VERSION 5.8 ;
BUSBITCHARS "[]" ;
DIVIDERCHAR "/" ;
UNITS
    DATABASE MICRONS 1000 ;
END UNITS

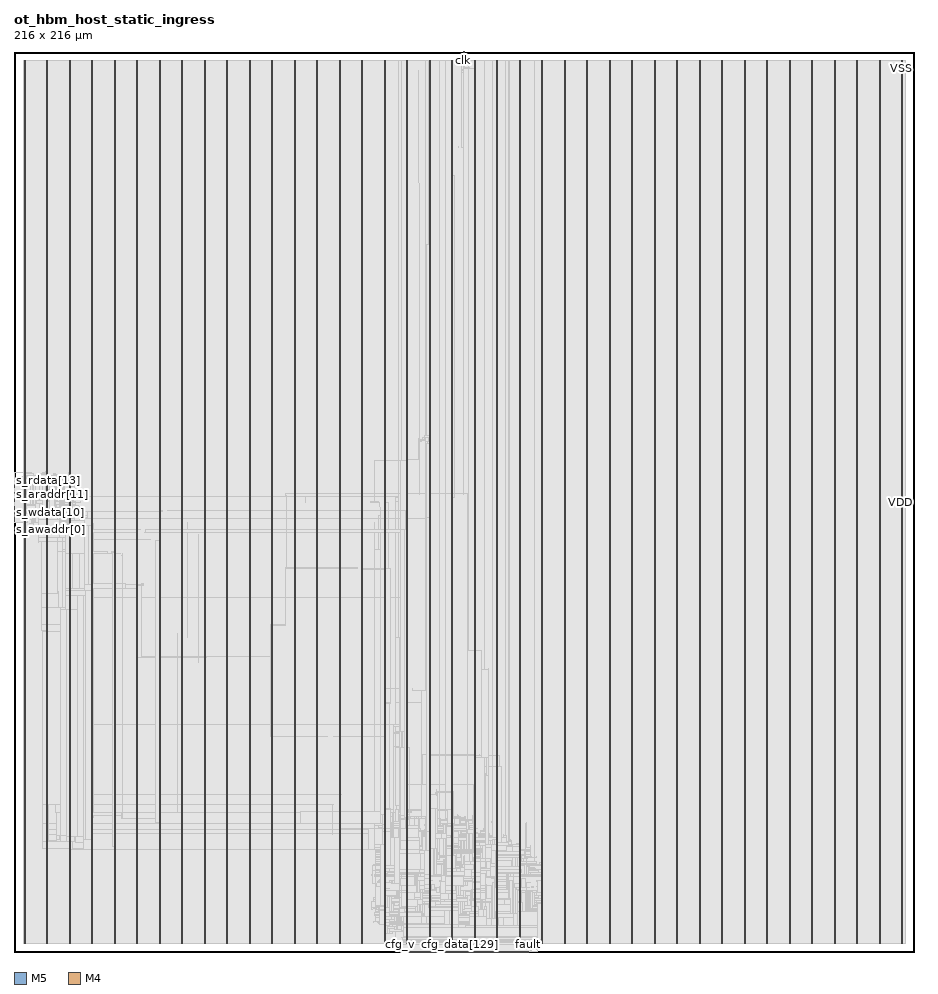
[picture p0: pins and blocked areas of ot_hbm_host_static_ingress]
MACRO ot_hbm_host_static_ingress
  FOREIGN ot_hbm_host_static_ingress 0 0 ;
  CLASS BLOCK ;
  SIZE 216 BY 216 ;
  PIN block_ready
    DIRECTION INPUT ;
    USE SIGNAL ;
    PORT
      LAYER M5 ;
        RECT  108 215.916 108.024 216 ;
    END
  END block_ready
  PIN cfg_addr[0]
    DIRECTION OUTPUT ;
    USE SIGNAL ;
    PORT
      LAYER M5 ;
        RECT  93.504 0 93.528 0.084 ;
    END
  END cfg_addr[0]
  PIN cfg_addr[10]
    DIRECTION OUTPUT ;
    USE SIGNAL ;
    PORT
      LAYER M5 ;
        RECT  94.464 0 94.488 0.084 ;
    END
  END cfg_addr[10]
  PIN cfg_addr[11]
    DIRECTION OUTPUT ;
    USE SIGNAL ;
    PORT
      LAYER M5 ;
        RECT  94.56 0 94.584 0.084 ;
    END
  END cfg_addr[11]
  PIN cfg_addr[1]
    DIRECTION OUTPUT ;
    USE SIGNAL ;
    PORT
      LAYER M5 ;
        RECT  93.6 0 93.624 0.084 ;
    END
  END cfg_addr[1]
  PIN cfg_addr[2]
    DIRECTION OUTPUT ;
    USE SIGNAL ;
    PORT
      LAYER M5 ;
        RECT  93.696 0 93.72 0.084 ;
    END
  END cfg_addr[2]
  PIN cfg_addr[3]
    DIRECTION OUTPUT ;
    USE SIGNAL ;
    PORT
      LAYER M5 ;
        RECT  93.792 0 93.816 0.084 ;
    END
  END cfg_addr[3]
  PIN cfg_addr[4]
    DIRECTION OUTPUT ;
    USE SIGNAL ;
    PORT
      LAYER M5 ;
        RECT  93.888 0 93.912 0.084 ;
    END
  END cfg_addr[4]
  PIN cfg_addr[5]
    DIRECTION OUTPUT ;
    USE SIGNAL ;
    PORT
      LAYER M5 ;
        RECT  93.984 0 94.008 0.084 ;
    END
  END cfg_addr[5]
  PIN cfg_addr[6]
    DIRECTION OUTPUT ;
    USE SIGNAL ;
    PORT
      LAYER M5 ;
        RECT  94.08 0 94.104 0.084 ;
    END
  END cfg_addr[6]
  PIN cfg_addr[7]
    DIRECTION OUTPUT ;
    USE SIGNAL ;
    PORT
      LAYER M5 ;
        RECT  94.176 0 94.2 0.084 ;
    END
  END cfg_addr[7]
  PIN cfg_addr[8]
    DIRECTION OUTPUT ;
    USE SIGNAL ;
    PORT
      LAYER M5 ;
        RECT  94.272 0 94.296 0.084 ;
    END
  END cfg_addr[8]
  PIN cfg_addr[9]
    DIRECTION OUTPUT ;
    USE SIGNAL ;
    PORT
      LAYER M5 ;
        RECT  94.368 0 94.392 0.084 ;
    END
  END cfg_addr[9]
  PIN cfg_data[0]
    DIRECTION OUTPUT ;
    USE SIGNAL ;
    PORT
      LAYER M5 ;
        RECT  94.656 0 94.68 0.084 ;
    END
  END cfg_data[0]
  PIN cfg_data[100]
    DIRECTION OUTPUT ;
    USE SIGNAL ;
    PORT
      LAYER M5 ;
        RECT  104.256 0 104.28 0.084 ;
    END
  END cfg_data[100]
  PIN cfg_data[101]
    DIRECTION OUTPUT ;
    USE SIGNAL ;
    PORT
      LAYER M5 ;
        RECT  104.352 0 104.376 0.084 ;
    END
  END cfg_data[101]
  PIN cfg_data[102]
    DIRECTION OUTPUT ;
    USE SIGNAL ;
    PORT
      LAYER M5 ;
        RECT  104.448 0 104.472 0.084 ;
    END
  END cfg_data[102]
  PIN cfg_data[103]
    DIRECTION OUTPUT ;
    USE SIGNAL ;
    PORT
      LAYER M5 ;
        RECT  104.544 0 104.568 0.084 ;
    END
  END cfg_data[103]
  PIN cfg_data[104]
    DIRECTION OUTPUT ;
    USE SIGNAL ;
    PORT
      LAYER M5 ;
        RECT  104.64 0 104.664 0.084 ;
    END
  END cfg_data[104]
  PIN cfg_data[105]
    DIRECTION OUTPUT ;
    USE SIGNAL ;
    PORT
      LAYER M5 ;
        RECT  104.736 0 104.76 0.084 ;
    END
  END cfg_data[105]
  PIN cfg_data[106]
    DIRECTION OUTPUT ;
    USE SIGNAL ;
    PORT
      LAYER M5 ;
        RECT  104.832 0 104.856 0.084 ;
    END
  END cfg_data[106]
  PIN cfg_data[107]
    DIRECTION OUTPUT ;
    USE SIGNAL ;
    PORT
      LAYER M5 ;
        RECT  104.928 0 104.952 0.084 ;
    END
  END cfg_data[107]
  PIN cfg_data[108]
    DIRECTION OUTPUT ;
    USE SIGNAL ;
    PORT
      LAYER M5 ;
        RECT  105.024 0 105.048 0.084 ;
    END
  END cfg_data[108]
  PIN cfg_data[109]
    DIRECTION OUTPUT ;
    USE SIGNAL ;
    PORT
      LAYER M5 ;
        RECT  105.12 0 105.144 0.084 ;
    END
  END cfg_data[109]
  PIN cfg_data[10]
    DIRECTION OUTPUT ;
    USE SIGNAL ;
    PORT
      LAYER M5 ;
        RECT  95.616 0 95.64 0.084 ;
    END
  END cfg_data[10]
  PIN cfg_data[110]
    DIRECTION OUTPUT ;
    USE SIGNAL ;
    PORT
      LAYER M5 ;
        RECT  105.216 0 105.24 0.084 ;
    END
  END cfg_data[110]
  PIN cfg_data[111]
    DIRECTION OUTPUT ;
    USE SIGNAL ;
    PORT
      LAYER M5 ;
        RECT  105.312 0 105.336 0.084 ;
    END
  END cfg_data[111]
  PIN cfg_data[112]
    DIRECTION OUTPUT ;
    USE SIGNAL ;
    PORT
      LAYER M5 ;
        RECT  105.408 0 105.432 0.084 ;
    END
  END cfg_data[112]
  PIN cfg_data[113]
    DIRECTION OUTPUT ;
    USE SIGNAL ;
    PORT
      LAYER M5 ;
        RECT  105.504 0 105.528 0.084 ;
    END
  END cfg_data[113]
  PIN cfg_data[114]
    DIRECTION OUTPUT ;
    USE SIGNAL ;
    PORT
      LAYER M5 ;
        RECT  105.6 0 105.624 0.084 ;
    END
  END cfg_data[114]
  PIN cfg_data[115]
    DIRECTION OUTPUT ;
    USE SIGNAL ;
    PORT
      LAYER M5 ;
        RECT  105.696 0 105.72 0.084 ;
    END
  END cfg_data[115]
  PIN cfg_data[116]
    DIRECTION OUTPUT ;
    USE SIGNAL ;
    PORT
      LAYER M5 ;
        RECT  105.792 0 105.816 0.084 ;
    END
  END cfg_data[116]
  PIN cfg_data[117]
    DIRECTION OUTPUT ;
    USE SIGNAL ;
    PORT
      LAYER M5 ;
        RECT  105.888 0 105.912 0.084 ;
    END
  END cfg_data[117]
  PIN cfg_data[118]
    DIRECTION OUTPUT ;
    USE SIGNAL ;
    PORT
      LAYER M5 ;
        RECT  105.984 0 106.008 0.084 ;
    END
  END cfg_data[118]
  PIN cfg_data[119]
    DIRECTION OUTPUT ;
    USE SIGNAL ;
    PORT
      LAYER M5 ;
        RECT  106.08 0 106.104 0.084 ;
    END
  END cfg_data[119]
  PIN cfg_data[11]
    DIRECTION OUTPUT ;
    USE SIGNAL ;
    PORT
      LAYER M5 ;
        RECT  95.712 0 95.736 0.084 ;
    END
  END cfg_data[11]
  PIN cfg_data[120]
    DIRECTION OUTPUT ;
    USE SIGNAL ;
    PORT
      LAYER M5 ;
        RECT  106.176 0 106.2 0.084 ;
    END
  END cfg_data[120]
  PIN cfg_data[121]
    DIRECTION OUTPUT ;
    USE SIGNAL ;
    PORT
      LAYER M5 ;
        RECT  106.272 0 106.296 0.084 ;
    END
  END cfg_data[121]
  PIN cfg_data[122]
    DIRECTION OUTPUT ;
    USE SIGNAL ;
    PORT
      LAYER M5 ;
        RECT  106.368 0 106.392 0.084 ;
    END
  END cfg_data[122]
  PIN cfg_data[123]
    DIRECTION OUTPUT ;
    USE SIGNAL ;
    PORT
      LAYER M5 ;
        RECT  106.464 0 106.488 0.084 ;
    END
  END cfg_data[123]
  PIN cfg_data[124]
    DIRECTION OUTPUT ;
    USE SIGNAL ;
    PORT
      LAYER M5 ;
        RECT  106.56 0 106.584 0.084 ;
    END
  END cfg_data[124]
  PIN cfg_data[125]
    DIRECTION OUTPUT ;
    USE SIGNAL ;
    PORT
      LAYER M5 ;
        RECT  106.656 0 106.68 0.084 ;
    END
  END cfg_data[125]
  PIN cfg_data[126]
    DIRECTION OUTPUT ;
    USE SIGNAL ;
    PORT
      LAYER M5 ;
        RECT  106.752 0 106.776 0.084 ;
    END
  END cfg_data[126]
  PIN cfg_data[127]
    DIRECTION OUTPUT ;
    USE SIGNAL ;
    PORT
      LAYER M5 ;
        RECT  106.848 0 106.872 0.084 ;
    END
  END cfg_data[127]
  PIN cfg_data[128]
    DIRECTION OUTPUT ;
    USE SIGNAL ;
    PORT
      LAYER M5 ;
        RECT  106.944 0 106.968 0.084 ;
    END
  END cfg_data[128]
  PIN cfg_data[129]
    DIRECTION OUTPUT ;
    USE SIGNAL ;
    PORT
      LAYER M5 ;
        RECT  107.04 0 107.064 0.084 ;
    END
  END cfg_data[129]
  PIN cfg_data[12]
    DIRECTION OUTPUT ;
    USE SIGNAL ;
    PORT
      LAYER M5 ;
        RECT  95.808 0 95.832 0.084 ;
    END
  END cfg_data[12]
  PIN cfg_data[130]
    DIRECTION OUTPUT ;
    USE SIGNAL ;
    PORT
      LAYER M5 ;
        RECT  107.136 0 107.16 0.084 ;
    END
  END cfg_data[130]
  PIN cfg_data[131]
    DIRECTION OUTPUT ;
    USE SIGNAL ;
    PORT
      LAYER M5 ;
        RECT  107.232 0 107.256 0.084 ;
    END
  END cfg_data[131]
  PIN cfg_data[132]
    DIRECTION OUTPUT ;
    USE SIGNAL ;
    PORT
      LAYER M5 ;
        RECT  107.328 0 107.352 0.084 ;
    END
  END cfg_data[132]
  PIN cfg_data[133]
    DIRECTION OUTPUT ;
    USE SIGNAL ;
    PORT
      LAYER M5 ;
        RECT  107.424 0 107.448 0.084 ;
    END
  END cfg_data[133]
  PIN cfg_data[134]
    DIRECTION OUTPUT ;
    USE SIGNAL ;
    PORT
      LAYER M5 ;
        RECT  107.52 0 107.544 0.084 ;
    END
  END cfg_data[134]
  PIN cfg_data[135]
    DIRECTION OUTPUT ;
    USE SIGNAL ;
    PORT
      LAYER M5 ;
        RECT  107.616 0 107.64 0.084 ;
    END
  END cfg_data[135]
  PIN cfg_data[136]
    DIRECTION OUTPUT ;
    USE SIGNAL ;
    PORT
      LAYER M5 ;
        RECT  107.712 0 107.736 0.084 ;
    END
  END cfg_data[136]
  PIN cfg_data[137]
    DIRECTION OUTPUT ;
    USE SIGNAL ;
    PORT
      LAYER M5 ;
        RECT  107.808 0 107.832 0.084 ;
    END
  END cfg_data[137]
  PIN cfg_data[138]
    DIRECTION OUTPUT ;
    USE SIGNAL ;
    PORT
      LAYER M5 ;
        RECT  107.904 0 107.928 0.084 ;
    END
  END cfg_data[138]
  PIN cfg_data[139]
    DIRECTION OUTPUT ;
    USE SIGNAL ;
    PORT
      LAYER M5 ;
        RECT  108 0 108.024 0.084 ;
    END
  END cfg_data[139]
  PIN cfg_data[13]
    DIRECTION OUTPUT ;
    USE SIGNAL ;
    PORT
      LAYER M5 ;
        RECT  95.904 0 95.928 0.084 ;
    END
  END cfg_data[13]
  PIN cfg_data[140]
    DIRECTION OUTPUT ;
    USE SIGNAL ;
    PORT
      LAYER M5 ;
        RECT  108.096 0 108.12 0.084 ;
    END
  END cfg_data[140]
  PIN cfg_data[141]
    DIRECTION OUTPUT ;
    USE SIGNAL ;
    PORT
      LAYER M5 ;
        RECT  108.192 0 108.216 0.084 ;
    END
  END cfg_data[141]
  PIN cfg_data[142]
    DIRECTION OUTPUT ;
    USE SIGNAL ;
    PORT
      LAYER M5 ;
        RECT  108.288 0 108.312 0.084 ;
    END
  END cfg_data[142]
  PIN cfg_data[143]
    DIRECTION OUTPUT ;
    USE SIGNAL ;
    PORT
      LAYER M5 ;
        RECT  108.384 0 108.408 0.084 ;
    END
  END cfg_data[143]
  PIN cfg_data[144]
    DIRECTION OUTPUT ;
    USE SIGNAL ;
    PORT
      LAYER M5 ;
        RECT  108.48 0 108.504 0.084 ;
    END
  END cfg_data[144]
  PIN cfg_data[145]
    DIRECTION OUTPUT ;
    USE SIGNAL ;
    PORT
      LAYER M5 ;
        RECT  108.576 0 108.6 0.084 ;
    END
  END cfg_data[145]
  PIN cfg_data[146]
    DIRECTION OUTPUT ;
    USE SIGNAL ;
    PORT
      LAYER M5 ;
        RECT  108.672 0 108.696 0.084 ;
    END
  END cfg_data[146]
  PIN cfg_data[147]
    DIRECTION OUTPUT ;
    USE SIGNAL ;
    PORT
      LAYER M5 ;
        RECT  108.768 0 108.792 0.084 ;
    END
  END cfg_data[147]
  PIN cfg_data[148]
    DIRECTION OUTPUT ;
    USE SIGNAL ;
    PORT
      LAYER M5 ;
        RECT  108.864 0 108.888 0.084 ;
    END
  END cfg_data[148]
  PIN cfg_data[149]
    DIRECTION OUTPUT ;
    USE SIGNAL ;
    PORT
      LAYER M5 ;
        RECT  108.96 0 108.984 0.084 ;
    END
  END cfg_data[149]
  PIN cfg_data[14]
    DIRECTION OUTPUT ;
    USE SIGNAL ;
    PORT
      LAYER M5 ;
        RECT  96 0 96.024 0.084 ;
    END
  END cfg_data[14]
  PIN cfg_data[150]
    DIRECTION OUTPUT ;
    USE SIGNAL ;
    PORT
      LAYER M5 ;
        RECT  109.056 0 109.08 0.084 ;
    END
  END cfg_data[150]
  PIN cfg_data[151]
    DIRECTION OUTPUT ;
    USE SIGNAL ;
    PORT
      LAYER M5 ;
        RECT  109.152 0 109.176 0.084 ;
    END
  END cfg_data[151]
  PIN cfg_data[152]
    DIRECTION OUTPUT ;
    USE SIGNAL ;
    PORT
      LAYER M5 ;
        RECT  109.248 0 109.272 0.084 ;
    END
  END cfg_data[152]
  PIN cfg_data[153]
    DIRECTION OUTPUT ;
    USE SIGNAL ;
    PORT
      LAYER M5 ;
        RECT  109.344 0 109.368 0.084 ;
    END
  END cfg_data[153]
  PIN cfg_data[154]
    DIRECTION OUTPUT ;
    USE SIGNAL ;
    PORT
      LAYER M5 ;
        RECT  109.44 0 109.464 0.084 ;
    END
  END cfg_data[154]
  PIN cfg_data[155]
    DIRECTION OUTPUT ;
    USE SIGNAL ;
    PORT
      LAYER M5 ;
        RECT  109.536 0 109.56 0.084 ;
    END
  END cfg_data[155]
  PIN cfg_data[156]
    DIRECTION OUTPUT ;
    USE SIGNAL ;
    PORT
      LAYER M5 ;
        RECT  109.632 0 109.656 0.084 ;
    END
  END cfg_data[156]
  PIN cfg_data[157]
    DIRECTION OUTPUT ;
    USE SIGNAL ;
    PORT
      LAYER M5 ;
        RECT  109.728 0 109.752 0.084 ;
    END
  END cfg_data[157]
  PIN cfg_data[158]
    DIRECTION OUTPUT ;
    USE SIGNAL ;
    PORT
      LAYER M5 ;
        RECT  109.824 0 109.848 0.084 ;
    END
  END cfg_data[158]
  PIN cfg_data[159]
    DIRECTION OUTPUT ;
    USE SIGNAL ;
    PORT
      LAYER M5 ;
        RECT  109.92 0 109.944 0.084 ;
    END
  END cfg_data[159]
  PIN cfg_data[15]
    DIRECTION OUTPUT ;
    USE SIGNAL ;
    PORT
      LAYER M5 ;
        RECT  96.096 0 96.12 0.084 ;
    END
  END cfg_data[15]
  PIN cfg_data[160]
    DIRECTION OUTPUT ;
    USE SIGNAL ;
    PORT
      LAYER M5 ;
        RECT  110.016 0 110.04 0.084 ;
    END
  END cfg_data[160]
  PIN cfg_data[161]
    DIRECTION OUTPUT ;
    USE SIGNAL ;
    PORT
      LAYER M5 ;
        RECT  110.112 0 110.136 0.084 ;
    END
  END cfg_data[161]
  PIN cfg_data[162]
    DIRECTION OUTPUT ;
    USE SIGNAL ;
    PORT
      LAYER M5 ;
        RECT  110.208 0 110.232 0.084 ;
    END
  END cfg_data[162]
  PIN cfg_data[163]
    DIRECTION OUTPUT ;
    USE SIGNAL ;
    PORT
      LAYER M5 ;
        RECT  110.304 0 110.328 0.084 ;
    END
  END cfg_data[163]
  PIN cfg_data[164]
    DIRECTION OUTPUT ;
    USE SIGNAL ;
    PORT
      LAYER M5 ;
        RECT  110.4 0 110.424 0.084 ;
    END
  END cfg_data[164]
  PIN cfg_data[165]
    DIRECTION OUTPUT ;
    USE SIGNAL ;
    PORT
      LAYER M5 ;
        RECT  110.496 0 110.52 0.084 ;
    END
  END cfg_data[165]
  PIN cfg_data[166]
    DIRECTION OUTPUT ;
    USE SIGNAL ;
    PORT
      LAYER M5 ;
        RECT  110.592 0 110.616 0.084 ;
    END
  END cfg_data[166]
  PIN cfg_data[167]
    DIRECTION OUTPUT ;
    USE SIGNAL ;
    PORT
      LAYER M5 ;
        RECT  110.688 0 110.712 0.084 ;
    END
  END cfg_data[167]
  PIN cfg_data[168]
    DIRECTION OUTPUT ;
    USE SIGNAL ;
    PORT
      LAYER M5 ;
        RECT  110.784 0 110.808 0.084 ;
    END
  END cfg_data[168]
  PIN cfg_data[169]
    DIRECTION OUTPUT ;
    USE SIGNAL ;
    PORT
      LAYER M5 ;
        RECT  110.88 0 110.904 0.084 ;
    END
  END cfg_data[169]
  PIN cfg_data[16]
    DIRECTION OUTPUT ;
    USE SIGNAL ;
    PORT
      LAYER M5 ;
        RECT  96.192 0 96.216 0.084 ;
    END
  END cfg_data[16]
  PIN cfg_data[170]
    DIRECTION OUTPUT ;
    USE SIGNAL ;
    PORT
      LAYER M5 ;
        RECT  110.976 0 111 0.084 ;
    END
  END cfg_data[170]
  PIN cfg_data[171]
    DIRECTION OUTPUT ;
    USE SIGNAL ;
    PORT
      LAYER M5 ;
        RECT  111.072 0 111.096 0.084 ;
    END
  END cfg_data[171]
  PIN cfg_data[172]
    DIRECTION OUTPUT ;
    USE SIGNAL ;
    PORT
      LAYER M5 ;
        RECT  111.168 0 111.192 0.084 ;
    END
  END cfg_data[172]
  PIN cfg_data[173]
    DIRECTION OUTPUT ;
    USE SIGNAL ;
    PORT
      LAYER M5 ;
        RECT  111.264 0 111.288 0.084 ;
    END
  END cfg_data[173]
  PIN cfg_data[174]
    DIRECTION OUTPUT ;
    USE SIGNAL ;
    PORT
      LAYER M5 ;
        RECT  111.36 0 111.384 0.084 ;
    END
  END cfg_data[174]
  PIN cfg_data[175]
    DIRECTION OUTPUT ;
    USE SIGNAL ;
    PORT
      LAYER M5 ;
        RECT  111.456 0 111.48 0.084 ;
    END
  END cfg_data[175]
  PIN cfg_data[176]
    DIRECTION OUTPUT ;
    USE SIGNAL ;
    PORT
      LAYER M5 ;
        RECT  111.552 0 111.576 0.084 ;
    END
  END cfg_data[176]
  PIN cfg_data[177]
    DIRECTION OUTPUT ;
    USE SIGNAL ;
    PORT
      LAYER M5 ;
        RECT  111.648 0 111.672 0.084 ;
    END
  END cfg_data[177]
  PIN cfg_data[178]
    DIRECTION OUTPUT ;
    USE SIGNAL ;
    PORT
      LAYER M5 ;
        RECT  111.744 0 111.768 0.084 ;
    END
  END cfg_data[178]
  PIN cfg_data[179]
    DIRECTION OUTPUT ;
    USE SIGNAL ;
    PORT
      LAYER M5 ;
        RECT  111.84 0 111.864 0.084 ;
    END
  END cfg_data[179]
  PIN cfg_data[17]
    DIRECTION OUTPUT ;
    USE SIGNAL ;
    PORT
      LAYER M5 ;
        RECT  96.288 0 96.312 0.084 ;
    END
  END cfg_data[17]
  PIN cfg_data[180]
    DIRECTION OUTPUT ;
    USE SIGNAL ;
    PORT
      LAYER M5 ;
        RECT  111.936 0 111.96 0.084 ;
    END
  END cfg_data[180]
  PIN cfg_data[181]
    DIRECTION OUTPUT ;
    USE SIGNAL ;
    PORT
      LAYER M5 ;
        RECT  112.032 0 112.056 0.084 ;
    END
  END cfg_data[181]
  PIN cfg_data[182]
    DIRECTION OUTPUT ;
    USE SIGNAL ;
    PORT
      LAYER M5 ;
        RECT  112.128 0 112.152 0.084 ;
    END
  END cfg_data[182]
  PIN cfg_data[183]
    DIRECTION OUTPUT ;
    USE SIGNAL ;
    PORT
      LAYER M5 ;
        RECT  112.224 0 112.248 0.084 ;
    END
  END cfg_data[183]
  PIN cfg_data[184]
    DIRECTION OUTPUT ;
    USE SIGNAL ;
    PORT
      LAYER M5 ;
        RECT  112.32 0 112.344 0.084 ;
    END
  END cfg_data[184]
  PIN cfg_data[185]
    DIRECTION OUTPUT ;
    USE SIGNAL ;
    PORT
      LAYER M5 ;
        RECT  112.416 0 112.44 0.084 ;
    END
  END cfg_data[185]
  PIN cfg_data[186]
    DIRECTION OUTPUT ;
    USE SIGNAL ;
    PORT
      LAYER M5 ;
        RECT  112.512 0 112.536 0.084 ;
    END
  END cfg_data[186]
  PIN cfg_data[187]
    DIRECTION OUTPUT ;
    USE SIGNAL ;
    PORT
      LAYER M5 ;
        RECT  112.608 0 112.632 0.084 ;
    END
  END cfg_data[187]
  PIN cfg_data[188]
    DIRECTION OUTPUT ;
    USE SIGNAL ;
    PORT
      LAYER M5 ;
        RECT  112.704 0 112.728 0.084 ;
    END
  END cfg_data[188]
  PIN cfg_data[189]
    DIRECTION OUTPUT ;
    USE SIGNAL ;
    PORT
      LAYER M5 ;
        RECT  112.8 0 112.824 0.084 ;
    END
  END cfg_data[189]
  PIN cfg_data[18]
    DIRECTION OUTPUT ;
    USE SIGNAL ;
    PORT
      LAYER M5 ;
        RECT  96.384 0 96.408 0.084 ;
    END
  END cfg_data[18]
  PIN cfg_data[190]
    DIRECTION OUTPUT ;
    USE SIGNAL ;
    PORT
      LAYER M5 ;
        RECT  112.896 0 112.92 0.084 ;
    END
  END cfg_data[190]
  PIN cfg_data[191]
    DIRECTION OUTPUT ;
    USE SIGNAL ;
    PORT
      LAYER M5 ;
        RECT  112.992 0 113.016 0.084 ;
    END
  END cfg_data[191]
  PIN cfg_data[192]
    DIRECTION OUTPUT ;
    USE SIGNAL ;
    PORT
      LAYER M5 ;
        RECT  113.088 0 113.112 0.084 ;
    END
  END cfg_data[192]
  PIN cfg_data[193]
    DIRECTION OUTPUT ;
    USE SIGNAL ;
    PORT
      LAYER M5 ;
        RECT  113.184 0 113.208 0.084 ;
    END
  END cfg_data[193]
  PIN cfg_data[194]
    DIRECTION OUTPUT ;
    USE SIGNAL ;
    PORT
      LAYER M5 ;
        RECT  113.28 0 113.304 0.084 ;
    END
  END cfg_data[194]
  PIN cfg_data[195]
    DIRECTION OUTPUT ;
    USE SIGNAL ;
    PORT
      LAYER M5 ;
        RECT  113.376 0 113.4 0.084 ;
    END
  END cfg_data[195]
  PIN cfg_data[196]
    DIRECTION OUTPUT ;
    USE SIGNAL ;
    PORT
      LAYER M5 ;
        RECT  113.472 0 113.496 0.084 ;
    END
  END cfg_data[196]
  PIN cfg_data[197]
    DIRECTION OUTPUT ;
    USE SIGNAL ;
    PORT
      LAYER M5 ;
        RECT  113.568 0 113.592 0.084 ;
    END
  END cfg_data[197]
  PIN cfg_data[198]
    DIRECTION OUTPUT ;
    USE SIGNAL ;
    PORT
      LAYER M5 ;
        RECT  113.664 0 113.688 0.084 ;
    END
  END cfg_data[198]
  PIN cfg_data[199]
    DIRECTION OUTPUT ;
    USE SIGNAL ;
    PORT
      LAYER M5 ;
        RECT  113.76 0 113.784 0.084 ;
    END
  END cfg_data[199]
  PIN cfg_data[19]
    DIRECTION OUTPUT ;
    USE SIGNAL ;
    PORT
      LAYER M5 ;
        RECT  96.48 0 96.504 0.084 ;
    END
  END cfg_data[19]
  PIN cfg_data[1]
    DIRECTION OUTPUT ;
    USE SIGNAL ;
    PORT
      LAYER M5 ;
        RECT  94.752 0 94.776 0.084 ;
    END
  END cfg_data[1]
  PIN cfg_data[200]
    DIRECTION OUTPUT ;
    USE SIGNAL ;
    PORT
      LAYER M5 ;
        RECT  113.856 0 113.88 0.084 ;
    END
  END cfg_data[200]
  PIN cfg_data[201]
    DIRECTION OUTPUT ;
    USE SIGNAL ;
    PORT
      LAYER M5 ;
        RECT  113.952 0 113.976 0.084 ;
    END
  END cfg_data[201]
  PIN cfg_data[202]
    DIRECTION OUTPUT ;
    USE SIGNAL ;
    PORT
      LAYER M5 ;
        RECT  114.048 0 114.072 0.084 ;
    END
  END cfg_data[202]
  PIN cfg_data[203]
    DIRECTION OUTPUT ;
    USE SIGNAL ;
    PORT
      LAYER M5 ;
        RECT  114.144 0 114.168 0.084 ;
    END
  END cfg_data[203]
  PIN cfg_data[204]
    DIRECTION OUTPUT ;
    USE SIGNAL ;
    PORT
      LAYER M5 ;
        RECT  114.24 0 114.264 0.084 ;
    END
  END cfg_data[204]
  PIN cfg_data[205]
    DIRECTION OUTPUT ;
    USE SIGNAL ;
    PORT
      LAYER M5 ;
        RECT  114.336 0 114.36 0.084 ;
    END
  END cfg_data[205]
  PIN cfg_data[206]
    DIRECTION OUTPUT ;
    USE SIGNAL ;
    PORT
      LAYER M5 ;
        RECT  114.432 0 114.456 0.084 ;
    END
  END cfg_data[206]
  PIN cfg_data[207]
    DIRECTION OUTPUT ;
    USE SIGNAL ;
    PORT
      LAYER M5 ;
        RECT  114.528 0 114.552 0.084 ;
    END
  END cfg_data[207]
  PIN cfg_data[208]
    DIRECTION OUTPUT ;
    USE SIGNAL ;
    PORT
      LAYER M5 ;
        RECT  114.624 0 114.648 0.084 ;
    END
  END cfg_data[208]
  PIN cfg_data[209]
    DIRECTION OUTPUT ;
    USE SIGNAL ;
    PORT
      LAYER M5 ;
        RECT  114.72 0 114.744 0.084 ;
    END
  END cfg_data[209]
  PIN cfg_data[20]
    DIRECTION OUTPUT ;
    USE SIGNAL ;
    PORT
      LAYER M5 ;
        RECT  96.576 0 96.6 0.084 ;
    END
  END cfg_data[20]
  PIN cfg_data[210]
    DIRECTION OUTPUT ;
    USE SIGNAL ;
    PORT
      LAYER M5 ;
        RECT  114.816 0 114.84 0.084 ;
    END
  END cfg_data[210]
  PIN cfg_data[211]
    DIRECTION OUTPUT ;
    USE SIGNAL ;
    PORT
      LAYER M5 ;
        RECT  114.912 0 114.936 0.084 ;
    END
  END cfg_data[211]
  PIN cfg_data[212]
    DIRECTION OUTPUT ;
    USE SIGNAL ;
    PORT
      LAYER M5 ;
        RECT  115.008 0 115.032 0.084 ;
    END
  END cfg_data[212]
  PIN cfg_data[213]
    DIRECTION OUTPUT ;
    USE SIGNAL ;
    PORT
      LAYER M5 ;
        RECT  115.104 0 115.128 0.084 ;
    END
  END cfg_data[213]
  PIN cfg_data[214]
    DIRECTION OUTPUT ;
    USE SIGNAL ;
    PORT
      LAYER M5 ;
        RECT  115.2 0 115.224 0.084 ;
    END
  END cfg_data[214]
  PIN cfg_data[215]
    DIRECTION OUTPUT ;
    USE SIGNAL ;
    PORT
      LAYER M5 ;
        RECT  115.296 0 115.32 0.084 ;
    END
  END cfg_data[215]
  PIN cfg_data[216]
    DIRECTION OUTPUT ;
    USE SIGNAL ;
    PORT
      LAYER M5 ;
        RECT  115.392 0 115.416 0.084 ;
    END
  END cfg_data[216]
  PIN cfg_data[217]
    DIRECTION OUTPUT ;
    USE SIGNAL ;
    PORT
      LAYER M5 ;
        RECT  115.488 0 115.512 0.084 ;
    END
  END cfg_data[217]
  PIN cfg_data[218]
    DIRECTION OUTPUT ;
    USE SIGNAL ;
    PORT
      LAYER M5 ;
        RECT  115.584 0 115.608 0.084 ;
    END
  END cfg_data[218]
  PIN cfg_data[219]
    DIRECTION OUTPUT ;
    USE SIGNAL ;
    PORT
      LAYER M5 ;
        RECT  115.68 0 115.704 0.084 ;
    END
  END cfg_data[219]
  PIN cfg_data[21]
    DIRECTION OUTPUT ;
    USE SIGNAL ;
    PORT
      LAYER M5 ;
        RECT  96.672 0 96.696 0.084 ;
    END
  END cfg_data[21]
  PIN cfg_data[220]
    DIRECTION OUTPUT ;
    USE SIGNAL ;
    PORT
      LAYER M5 ;
        RECT  115.776 0 115.8 0.084 ;
    END
  END cfg_data[220]
  PIN cfg_data[221]
    DIRECTION OUTPUT ;
    USE SIGNAL ;
    PORT
      LAYER M5 ;
        RECT  115.872 0 115.896 0.084 ;
    END
  END cfg_data[221]
  PIN cfg_data[222]
    DIRECTION OUTPUT ;
    USE SIGNAL ;
    PORT
      LAYER M5 ;
        RECT  115.968 0 115.992 0.084 ;
    END
  END cfg_data[222]
  PIN cfg_data[223]
    DIRECTION OUTPUT ;
    USE SIGNAL ;
    PORT
      LAYER M5 ;
        RECT  116.064 0 116.088 0.084 ;
    END
  END cfg_data[223]
  PIN cfg_data[224]
    DIRECTION OUTPUT ;
    USE SIGNAL ;
    PORT
      LAYER M5 ;
        RECT  116.16 0 116.184 0.084 ;
    END
  END cfg_data[224]
  PIN cfg_data[225]
    DIRECTION OUTPUT ;
    USE SIGNAL ;
    PORT
      LAYER M5 ;
        RECT  116.256 0 116.28 0.084 ;
    END
  END cfg_data[225]
  PIN cfg_data[226]
    DIRECTION OUTPUT ;
    USE SIGNAL ;
    PORT
      LAYER M5 ;
        RECT  116.352 0 116.376 0.084 ;
    END
  END cfg_data[226]
  PIN cfg_data[227]
    DIRECTION OUTPUT ;
    USE SIGNAL ;
    PORT
      LAYER M5 ;
        RECT  116.448 0 116.472 0.084 ;
    END
  END cfg_data[227]
  PIN cfg_data[228]
    DIRECTION OUTPUT ;
    USE SIGNAL ;
    PORT
      LAYER M5 ;
        RECT  116.544 0 116.568 0.084 ;
    END
  END cfg_data[228]
  PIN cfg_data[229]
    DIRECTION OUTPUT ;
    USE SIGNAL ;
    PORT
      LAYER M5 ;
        RECT  116.64 0 116.664 0.084 ;
    END
  END cfg_data[229]
  PIN cfg_data[22]
    DIRECTION OUTPUT ;
    USE SIGNAL ;
    PORT
      LAYER M5 ;
        RECT  96.768 0 96.792 0.084 ;
    END
  END cfg_data[22]
  PIN cfg_data[230]
    DIRECTION OUTPUT ;
    USE SIGNAL ;
    PORT
      LAYER M5 ;
        RECT  116.736 0 116.76 0.084 ;
    END
  END cfg_data[230]
  PIN cfg_data[231]
    DIRECTION OUTPUT ;
    USE SIGNAL ;
    PORT
      LAYER M5 ;
        RECT  116.832 0 116.856 0.084 ;
    END
  END cfg_data[231]
  PIN cfg_data[232]
    DIRECTION OUTPUT ;
    USE SIGNAL ;
    PORT
      LAYER M5 ;
        RECT  116.928 0 116.952 0.084 ;
    END
  END cfg_data[232]
  PIN cfg_data[233]
    DIRECTION OUTPUT ;
    USE SIGNAL ;
    PORT
      LAYER M5 ;
        RECT  117.024 0 117.048 0.084 ;
    END
  END cfg_data[233]
  PIN cfg_data[234]
    DIRECTION OUTPUT ;
    USE SIGNAL ;
    PORT
      LAYER M5 ;
        RECT  117.12 0 117.144 0.084 ;
    END
  END cfg_data[234]
  PIN cfg_data[235]
    DIRECTION OUTPUT ;
    USE SIGNAL ;
    PORT
      LAYER M5 ;
        RECT  117.216 0 117.24 0.084 ;
    END
  END cfg_data[235]
  PIN cfg_data[236]
    DIRECTION OUTPUT ;
    USE SIGNAL ;
    PORT
      LAYER M5 ;
        RECT  117.312 0 117.336 0.084 ;
    END
  END cfg_data[236]
  PIN cfg_data[237]
    DIRECTION OUTPUT ;
    USE SIGNAL ;
    PORT
      LAYER M5 ;
        RECT  117.408 0 117.432 0.084 ;
    END
  END cfg_data[237]
  PIN cfg_data[238]
    DIRECTION OUTPUT ;
    USE SIGNAL ;
    PORT
      LAYER M5 ;
        RECT  117.504 0 117.528 0.084 ;
    END
  END cfg_data[238]
  PIN cfg_data[239]
    DIRECTION OUTPUT ;
    USE SIGNAL ;
    PORT
      LAYER M5 ;
        RECT  117.6 0 117.624 0.084 ;
    END
  END cfg_data[239]
  PIN cfg_data[23]
    DIRECTION OUTPUT ;
    USE SIGNAL ;
    PORT
      LAYER M5 ;
        RECT  96.864 0 96.888 0.084 ;
    END
  END cfg_data[23]
  PIN cfg_data[240]
    DIRECTION OUTPUT ;
    USE SIGNAL ;
    PORT
      LAYER M5 ;
        RECT  117.696 0 117.72 0.084 ;
    END
  END cfg_data[240]
  PIN cfg_data[241]
    DIRECTION OUTPUT ;
    USE SIGNAL ;
    PORT
      LAYER M5 ;
        RECT  117.792 0 117.816 0.084 ;
    END
  END cfg_data[241]
  PIN cfg_data[242]
    DIRECTION OUTPUT ;
    USE SIGNAL ;
    PORT
      LAYER M5 ;
        RECT  117.888 0 117.912 0.084 ;
    END
  END cfg_data[242]
  PIN cfg_data[243]
    DIRECTION OUTPUT ;
    USE SIGNAL ;
    PORT
      LAYER M5 ;
        RECT  117.984 0 118.008 0.084 ;
    END
  END cfg_data[243]
  PIN cfg_data[244]
    DIRECTION OUTPUT ;
    USE SIGNAL ;
    PORT
      LAYER M5 ;
        RECT  118.08 0 118.104 0.084 ;
    END
  END cfg_data[244]
  PIN cfg_data[245]
    DIRECTION OUTPUT ;
    USE SIGNAL ;
    PORT
      LAYER M5 ;
        RECT  118.176 0 118.2 0.084 ;
    END
  END cfg_data[245]
  PIN cfg_data[246]
    DIRECTION OUTPUT ;
    USE SIGNAL ;
    PORT
      LAYER M5 ;
        RECT  118.272 0 118.296 0.084 ;
    END
  END cfg_data[246]
  PIN cfg_data[247]
    DIRECTION OUTPUT ;
    USE SIGNAL ;
    PORT
      LAYER M5 ;
        RECT  118.368 0 118.392 0.084 ;
    END
  END cfg_data[247]
  PIN cfg_data[248]
    DIRECTION OUTPUT ;
    USE SIGNAL ;
    PORT
      LAYER M5 ;
        RECT  118.464 0 118.488 0.084 ;
    END
  END cfg_data[248]
  PIN cfg_data[249]
    DIRECTION OUTPUT ;
    USE SIGNAL ;
    PORT
      LAYER M5 ;
        RECT  118.56 0 118.584 0.084 ;
    END
  END cfg_data[249]
  PIN cfg_data[24]
    DIRECTION OUTPUT ;
    USE SIGNAL ;
    PORT
      LAYER M5 ;
        RECT  96.96 0 96.984 0.084 ;
    END
  END cfg_data[24]
  PIN cfg_data[250]
    DIRECTION OUTPUT ;
    USE SIGNAL ;
    PORT
      LAYER M5 ;
        RECT  118.656 0 118.68 0.084 ;
    END
  END cfg_data[250]
  PIN cfg_data[251]
    DIRECTION OUTPUT ;
    USE SIGNAL ;
    PORT
      LAYER M5 ;
        RECT  118.752 0 118.776 0.084 ;
    END
  END cfg_data[251]
  PIN cfg_data[252]
    DIRECTION OUTPUT ;
    USE SIGNAL ;
    PORT
      LAYER M5 ;
        RECT  118.848 0 118.872 0.084 ;
    END
  END cfg_data[252]
  PIN cfg_data[253]
    DIRECTION OUTPUT ;
    USE SIGNAL ;
    PORT
      LAYER M5 ;
        RECT  118.944 0 118.968 0.084 ;
    END
  END cfg_data[253]
  PIN cfg_data[254]
    DIRECTION OUTPUT ;
    USE SIGNAL ;
    PORT
      LAYER M5 ;
        RECT  119.04 0 119.064 0.084 ;
    END
  END cfg_data[254]
  PIN cfg_data[255]
    DIRECTION OUTPUT ;
    USE SIGNAL ;
    PORT
      LAYER M5 ;
        RECT  119.136 0 119.16 0.084 ;
    END
  END cfg_data[255]
  PIN cfg_data[25]
    DIRECTION OUTPUT ;
    USE SIGNAL ;
    PORT
      LAYER M5 ;
        RECT  97.056 0 97.08 0.084 ;
    END
  END cfg_data[25]
  PIN cfg_data[26]
    DIRECTION OUTPUT ;
    USE SIGNAL ;
    PORT
      LAYER M5 ;
        RECT  97.152 0 97.176 0.084 ;
    END
  END cfg_data[26]
  PIN cfg_data[27]
    DIRECTION OUTPUT ;
    USE SIGNAL ;
    PORT
      LAYER M5 ;
        RECT  97.248 0 97.272 0.084 ;
    END
  END cfg_data[27]
  PIN cfg_data[28]
    DIRECTION OUTPUT ;
    USE SIGNAL ;
    PORT
      LAYER M5 ;
        RECT  97.344 0 97.368 0.084 ;
    END
  END cfg_data[28]
  PIN cfg_data[29]
    DIRECTION OUTPUT ;
    USE SIGNAL ;
    PORT
      LAYER M5 ;
        RECT  97.44 0 97.464 0.084 ;
    END
  END cfg_data[29]
  PIN cfg_data[2]
    DIRECTION OUTPUT ;
    USE SIGNAL ;
    PORT
      LAYER M5 ;
        RECT  94.848 0 94.872 0.084 ;
    END
  END cfg_data[2]
  PIN cfg_data[30]
    DIRECTION OUTPUT ;
    USE SIGNAL ;
    PORT
      LAYER M5 ;
        RECT  97.536 0 97.56 0.084 ;
    END
  END cfg_data[30]
  PIN cfg_data[31]
    DIRECTION OUTPUT ;
    USE SIGNAL ;
    PORT
      LAYER M5 ;
        RECT  97.632 0 97.656 0.084 ;
    END
  END cfg_data[31]
  PIN cfg_data[32]
    DIRECTION OUTPUT ;
    USE SIGNAL ;
    PORT
      LAYER M5 ;
        RECT  97.728 0 97.752 0.084 ;
    END
  END cfg_data[32]
  PIN cfg_data[33]
    DIRECTION OUTPUT ;
    USE SIGNAL ;
    PORT
      LAYER M5 ;
        RECT  97.824 0 97.848 0.084 ;
    END
  END cfg_data[33]
  PIN cfg_data[34]
    DIRECTION OUTPUT ;
    USE SIGNAL ;
    PORT
      LAYER M5 ;
        RECT  97.92 0 97.944 0.084 ;
    END
  END cfg_data[34]
  PIN cfg_data[35]
    DIRECTION OUTPUT ;
    USE SIGNAL ;
    PORT
      LAYER M5 ;
        RECT  98.016 0 98.04 0.084 ;
    END
  END cfg_data[35]
  PIN cfg_data[36]
    DIRECTION OUTPUT ;
    USE SIGNAL ;
    PORT
      LAYER M5 ;
        RECT  98.112 0 98.136 0.084 ;
    END
  END cfg_data[36]
  PIN cfg_data[37]
    DIRECTION OUTPUT ;
    USE SIGNAL ;
    PORT
      LAYER M5 ;
        RECT  98.208 0 98.232 0.084 ;
    END
  END cfg_data[37]
  PIN cfg_data[38]
    DIRECTION OUTPUT ;
    USE SIGNAL ;
    PORT
      LAYER M5 ;
        RECT  98.304 0 98.328 0.084 ;
    END
  END cfg_data[38]
  PIN cfg_data[39]
    DIRECTION OUTPUT ;
    USE SIGNAL ;
    PORT
      LAYER M5 ;
        RECT  98.4 0 98.424 0.084 ;
    END
  END cfg_data[39]
  PIN cfg_data[3]
    DIRECTION OUTPUT ;
    USE SIGNAL ;
    PORT
      LAYER M5 ;
        RECT  94.944 0 94.968 0.084 ;
    END
  END cfg_data[3]
  PIN cfg_data[40]
    DIRECTION OUTPUT ;
    USE SIGNAL ;
    PORT
      LAYER M5 ;
        RECT  98.496 0 98.52 0.084 ;
    END
  END cfg_data[40]
  PIN cfg_data[41]
    DIRECTION OUTPUT ;
    USE SIGNAL ;
    PORT
      LAYER M5 ;
        RECT  98.592 0 98.616 0.084 ;
    END
  END cfg_data[41]
  PIN cfg_data[42]
    DIRECTION OUTPUT ;
    USE SIGNAL ;
    PORT
      LAYER M5 ;
        RECT  98.688 0 98.712 0.084 ;
    END
  END cfg_data[42]
  PIN cfg_data[43]
    DIRECTION OUTPUT ;
    USE SIGNAL ;
    PORT
      LAYER M5 ;
        RECT  98.784 0 98.808 0.084 ;
    END
  END cfg_data[43]
  PIN cfg_data[44]
    DIRECTION OUTPUT ;
    USE SIGNAL ;
    PORT
      LAYER M5 ;
        RECT  98.88 0 98.904 0.084 ;
    END
  END cfg_data[44]
  PIN cfg_data[45]
    DIRECTION OUTPUT ;
    USE SIGNAL ;
    PORT
      LAYER M5 ;
        RECT  98.976 0 99 0.084 ;
    END
  END cfg_data[45]
  PIN cfg_data[46]
    DIRECTION OUTPUT ;
    USE SIGNAL ;
    PORT
      LAYER M5 ;
        RECT  99.072 0 99.096 0.084 ;
    END
  END cfg_data[46]
  PIN cfg_data[47]
    DIRECTION OUTPUT ;
    USE SIGNAL ;
    PORT
      LAYER M5 ;
        RECT  99.168 0 99.192 0.084 ;
    END
  END cfg_data[47]
  PIN cfg_data[48]
    DIRECTION OUTPUT ;
    USE SIGNAL ;
    PORT
      LAYER M5 ;
        RECT  99.264 0 99.288 0.084 ;
    END
  END cfg_data[48]
  PIN cfg_data[49]
    DIRECTION OUTPUT ;
    USE SIGNAL ;
    PORT
      LAYER M5 ;
        RECT  99.36 0 99.384 0.084 ;
    END
  END cfg_data[49]
  PIN cfg_data[4]
    DIRECTION OUTPUT ;
    USE SIGNAL ;
    PORT
      LAYER M5 ;
        RECT  95.04 0 95.064 0.084 ;
    END
  END cfg_data[4]
  PIN cfg_data[50]
    DIRECTION OUTPUT ;
    USE SIGNAL ;
    PORT
      LAYER M5 ;
        RECT  99.456 0 99.48 0.084 ;
    END
  END cfg_data[50]
  PIN cfg_data[51]
    DIRECTION OUTPUT ;
    USE SIGNAL ;
    PORT
      LAYER M5 ;
        RECT  99.552 0 99.576 0.084 ;
    END
  END cfg_data[51]
  PIN cfg_data[52]
    DIRECTION OUTPUT ;
    USE SIGNAL ;
    PORT
      LAYER M5 ;
        RECT  99.648 0 99.672 0.084 ;
    END
  END cfg_data[52]
  PIN cfg_data[53]
    DIRECTION OUTPUT ;
    USE SIGNAL ;
    PORT
      LAYER M5 ;
        RECT  99.744 0 99.768 0.084 ;
    END
  END cfg_data[53]
  PIN cfg_data[54]
    DIRECTION OUTPUT ;
    USE SIGNAL ;
    PORT
      LAYER M5 ;
        RECT  99.84 0 99.864 0.084 ;
    END
  END cfg_data[54]
  PIN cfg_data[55]
    DIRECTION OUTPUT ;
    USE SIGNAL ;
    PORT
      LAYER M5 ;
        RECT  99.936 0 99.96 0.084 ;
    END
  END cfg_data[55]
  PIN cfg_data[56]
    DIRECTION OUTPUT ;
    USE SIGNAL ;
    PORT
      LAYER M5 ;
        RECT  100.032 0 100.056 0.084 ;
    END
  END cfg_data[56]
  PIN cfg_data[57]
    DIRECTION OUTPUT ;
    USE SIGNAL ;
    PORT
      LAYER M5 ;
        RECT  100.128 0 100.152 0.084 ;
    END
  END cfg_data[57]
  PIN cfg_data[58]
    DIRECTION OUTPUT ;
    USE SIGNAL ;
    PORT
      LAYER M5 ;
        RECT  100.224 0 100.248 0.084 ;
    END
  END cfg_data[58]
  PIN cfg_data[59]
    DIRECTION OUTPUT ;
    USE SIGNAL ;
    PORT
      LAYER M5 ;
        RECT  100.32 0 100.344 0.084 ;
    END
  END cfg_data[59]
  PIN cfg_data[5]
    DIRECTION OUTPUT ;
    USE SIGNAL ;
    PORT
      LAYER M5 ;
        RECT  95.136 0 95.16 0.084 ;
    END
  END cfg_data[5]
  PIN cfg_data[60]
    DIRECTION OUTPUT ;
    USE SIGNAL ;
    PORT
      LAYER M5 ;
        RECT  100.416 0 100.44 0.084 ;
    END
  END cfg_data[60]
  PIN cfg_data[61]
    DIRECTION OUTPUT ;
    USE SIGNAL ;
    PORT
      LAYER M5 ;
        RECT  100.512 0 100.536 0.084 ;
    END
  END cfg_data[61]
  PIN cfg_data[62]
    DIRECTION OUTPUT ;
    USE SIGNAL ;
    PORT
      LAYER M5 ;
        RECT  100.608 0 100.632 0.084 ;
    END
  END cfg_data[62]
  PIN cfg_data[63]
    DIRECTION OUTPUT ;
    USE SIGNAL ;
    PORT
      LAYER M5 ;
        RECT  100.704 0 100.728 0.084 ;
    END
  END cfg_data[63]
  PIN cfg_data[64]
    DIRECTION OUTPUT ;
    USE SIGNAL ;
    PORT
      LAYER M5 ;
        RECT  100.8 0 100.824 0.084 ;
    END
  END cfg_data[64]
  PIN cfg_data[65]
    DIRECTION OUTPUT ;
    USE SIGNAL ;
    PORT
      LAYER M5 ;
        RECT  100.896 0 100.92 0.084 ;
    END
  END cfg_data[65]
  PIN cfg_data[66]
    DIRECTION OUTPUT ;
    USE SIGNAL ;
    PORT
      LAYER M5 ;
        RECT  100.992 0 101.016 0.084 ;
    END
  END cfg_data[66]
  PIN cfg_data[67]
    DIRECTION OUTPUT ;
    USE SIGNAL ;
    PORT
      LAYER M5 ;
        RECT  101.088 0 101.112 0.084 ;
    END
  END cfg_data[67]
  PIN cfg_data[68]
    DIRECTION OUTPUT ;
    USE SIGNAL ;
    PORT
      LAYER M5 ;
        RECT  101.184 0 101.208 0.084 ;
    END
  END cfg_data[68]
  PIN cfg_data[69]
    DIRECTION OUTPUT ;
    USE SIGNAL ;
    PORT
      LAYER M5 ;
        RECT  101.28 0 101.304 0.084 ;
    END
  END cfg_data[69]
  PIN cfg_data[6]
    DIRECTION OUTPUT ;
    USE SIGNAL ;
    PORT
      LAYER M5 ;
        RECT  95.232 0 95.256 0.084 ;
    END
  END cfg_data[6]
  PIN cfg_data[70]
    DIRECTION OUTPUT ;
    USE SIGNAL ;
    PORT
      LAYER M5 ;
        RECT  101.376 0 101.4 0.084 ;
    END
  END cfg_data[70]
  PIN cfg_data[71]
    DIRECTION OUTPUT ;
    USE SIGNAL ;
    PORT
      LAYER M5 ;
        RECT  101.472 0 101.496 0.084 ;
    END
  END cfg_data[71]
  PIN cfg_data[72]
    DIRECTION OUTPUT ;
    USE SIGNAL ;
    PORT
      LAYER M5 ;
        RECT  101.568 0 101.592 0.084 ;
    END
  END cfg_data[72]
  PIN cfg_data[73]
    DIRECTION OUTPUT ;
    USE SIGNAL ;
    PORT
      LAYER M5 ;
        RECT  101.664 0 101.688 0.084 ;
    END
  END cfg_data[73]
  PIN cfg_data[74]
    DIRECTION OUTPUT ;
    USE SIGNAL ;
    PORT
      LAYER M5 ;
        RECT  101.76 0 101.784 0.084 ;
    END
  END cfg_data[74]
  PIN cfg_data[75]
    DIRECTION OUTPUT ;
    USE SIGNAL ;
    PORT
      LAYER M5 ;
        RECT  101.856 0 101.88 0.084 ;
    END
  END cfg_data[75]
  PIN cfg_data[76]
    DIRECTION OUTPUT ;
    USE SIGNAL ;
    PORT
      LAYER M5 ;
        RECT  101.952 0 101.976 0.084 ;
    END
  END cfg_data[76]
  PIN cfg_data[77]
    DIRECTION OUTPUT ;
    USE SIGNAL ;
    PORT
      LAYER M5 ;
        RECT  102.048 0 102.072 0.084 ;
    END
  END cfg_data[77]
  PIN cfg_data[78]
    DIRECTION OUTPUT ;
    USE SIGNAL ;
    PORT
      LAYER M5 ;
        RECT  102.144 0 102.168 0.084 ;
    END
  END cfg_data[78]
  PIN cfg_data[79]
    DIRECTION OUTPUT ;
    USE SIGNAL ;
    PORT
      LAYER M5 ;
        RECT  102.24 0 102.264 0.084 ;
    END
  END cfg_data[79]
  PIN cfg_data[7]
    DIRECTION OUTPUT ;
    USE SIGNAL ;
    PORT
      LAYER M5 ;
        RECT  95.328 0 95.352 0.084 ;
    END
  END cfg_data[7]
  PIN cfg_data[80]
    DIRECTION OUTPUT ;
    USE SIGNAL ;
    PORT
      LAYER M5 ;
        RECT  102.336 0 102.36 0.084 ;
    END
  END cfg_data[80]
  PIN cfg_data[81]
    DIRECTION OUTPUT ;
    USE SIGNAL ;
    PORT
      LAYER M5 ;
        RECT  102.432 0 102.456 0.084 ;
    END
  END cfg_data[81]
  PIN cfg_data[82]
    DIRECTION OUTPUT ;
    USE SIGNAL ;
    PORT
      LAYER M5 ;
        RECT  102.528 0 102.552 0.084 ;
    END
  END cfg_data[82]
  PIN cfg_data[83]
    DIRECTION OUTPUT ;
    USE SIGNAL ;
    PORT
      LAYER M5 ;
        RECT  102.624 0 102.648 0.084 ;
    END
  END cfg_data[83]
  PIN cfg_data[84]
    DIRECTION OUTPUT ;
    USE SIGNAL ;
    PORT
      LAYER M5 ;
        RECT  102.72 0 102.744 0.084 ;
    END
  END cfg_data[84]
  PIN cfg_data[85]
    DIRECTION OUTPUT ;
    USE SIGNAL ;
    PORT
      LAYER M5 ;
        RECT  102.816 0 102.84 0.084 ;
    END
  END cfg_data[85]
  PIN cfg_data[86]
    DIRECTION OUTPUT ;
    USE SIGNAL ;
    PORT
      LAYER M5 ;
        RECT  102.912 0 102.936 0.084 ;
    END
  END cfg_data[86]
  PIN cfg_data[87]
    DIRECTION OUTPUT ;
    USE SIGNAL ;
    PORT
      LAYER M5 ;
        RECT  103.008 0 103.032 0.084 ;
    END
  END cfg_data[87]
  PIN cfg_data[88]
    DIRECTION OUTPUT ;
    USE SIGNAL ;
    PORT
      LAYER M5 ;
        RECT  103.104 0 103.128 0.084 ;
    END
  END cfg_data[88]
  PIN cfg_data[89]
    DIRECTION OUTPUT ;
    USE SIGNAL ;
    PORT
      LAYER M5 ;
        RECT  103.2 0 103.224 0.084 ;
    END
  END cfg_data[89]
  PIN cfg_data[8]
    DIRECTION OUTPUT ;
    USE SIGNAL ;
    PORT
      LAYER M5 ;
        RECT  95.424 0 95.448 0.084 ;
    END
  END cfg_data[8]
  PIN cfg_data[90]
    DIRECTION OUTPUT ;
    USE SIGNAL ;
    PORT
      LAYER M5 ;
        RECT  103.296 0 103.32 0.084 ;
    END
  END cfg_data[90]
  PIN cfg_data[91]
    DIRECTION OUTPUT ;
    USE SIGNAL ;
    PORT
      LAYER M5 ;
        RECT  103.392 0 103.416 0.084 ;
    END
  END cfg_data[91]
  PIN cfg_data[92]
    DIRECTION OUTPUT ;
    USE SIGNAL ;
    PORT
      LAYER M5 ;
        RECT  103.488 0 103.512 0.084 ;
    END
  END cfg_data[92]
  PIN cfg_data[93]
    DIRECTION OUTPUT ;
    USE SIGNAL ;
    PORT
      LAYER M5 ;
        RECT  103.584 0 103.608 0.084 ;
    END
  END cfg_data[93]
  PIN cfg_data[94]
    DIRECTION OUTPUT ;
    USE SIGNAL ;
    PORT
      LAYER M5 ;
        RECT  103.68 0 103.704 0.084 ;
    END
  END cfg_data[94]
  PIN cfg_data[95]
    DIRECTION OUTPUT ;
    USE SIGNAL ;
    PORT
      LAYER M5 ;
        RECT  103.776 0 103.8 0.084 ;
    END
  END cfg_data[95]
  PIN cfg_data[96]
    DIRECTION OUTPUT ;
    USE SIGNAL ;
    PORT
      LAYER M5 ;
        RECT  103.872 0 103.896 0.084 ;
    END
  END cfg_data[96]
  PIN cfg_data[97]
    DIRECTION OUTPUT ;
    USE SIGNAL ;
    PORT
      LAYER M5 ;
        RECT  103.968 0 103.992 0.084 ;
    END
  END cfg_data[97]
  PIN cfg_data[98]
    DIRECTION OUTPUT ;
    USE SIGNAL ;
    PORT
      LAYER M5 ;
        RECT  104.064 0 104.088 0.084 ;
    END
  END cfg_data[98]
  PIN cfg_data[99]
    DIRECTION OUTPUT ;
    USE SIGNAL ;
    PORT
      LAYER M5 ;
        RECT  104.16 0 104.184 0.084 ;
    END
  END cfg_data[99]
  PIN cfg_data[9]
    DIRECTION OUTPUT ;
    USE SIGNAL ;
    PORT
      LAYER M5 ;
        RECT  95.52 0 95.544 0.084 ;
    END
  END cfg_data[9]
  PIN cfg_target[0]
    DIRECTION OUTPUT ;
    USE SIGNAL ;
    PORT
      LAYER M5 ;
        RECT  92.736 0 92.76 0.084 ;
    END
  END cfg_target[0]
  PIN cfg_target[1]
    DIRECTION OUTPUT ;
    USE SIGNAL ;
    PORT
      LAYER M5 ;
        RECT  92.832 0 92.856 0.084 ;
    END
  END cfg_target[1]
  PIN cfg_target[2]
    DIRECTION OUTPUT ;
    USE SIGNAL ;
    PORT
      LAYER M5 ;
        RECT  92.928 0 92.952 0.084 ;
    END
  END cfg_target[2]
  PIN cfg_target[3]
    DIRECTION OUTPUT ;
    USE SIGNAL ;
    PORT
      LAYER M5 ;
        RECT  93.024 0 93.048 0.084 ;
    END
  END cfg_target[3]
  PIN cfg_target[4]
    DIRECTION OUTPUT ;
    USE SIGNAL ;
    PORT
      LAYER M5 ;
        RECT  93.12 0 93.144 0.084 ;
    END
  END cfg_target[4]
  PIN cfg_target[5]
    DIRECTION OUTPUT ;
    USE SIGNAL ;
    PORT
      LAYER M5 ;
        RECT  93.216 0 93.24 0.084 ;
    END
  END cfg_target[5]
  PIN cfg_target[6]
    DIRECTION OUTPUT ;
    USE SIGNAL ;
    PORT
      LAYER M5 ;
        RECT  93.312 0 93.336 0.084 ;
    END
  END cfg_target[6]
  PIN cfg_target[7]
    DIRECTION OUTPUT ;
    USE SIGNAL ;
    PORT
      LAYER M5 ;
        RECT  93.408 0 93.432 0.084 ;
    END
  END cfg_target[7]
  PIN cfg_v
    DIRECTION OUTPUT ;
    USE SIGNAL ;
    PORT
      LAYER M5 ;
        RECT  92.64 0 92.664 0.084 ;
    END
  END cfg_v
  PIN clk
    DIRECTION INPUT ;
    USE SIGNAL ;
    PORT
      LAYER M5 ;
        RECT  107.808 215.916 107.832 216 ;
    END
  END clk
  PIN desc_base[0]
    DIRECTION OUTPUT ;
    USE SIGNAL ;
    PORT
      LAYER M5 ;
        RECT  119.328 0 119.352 0.084 ;
    END
  END desc_base[0]
  PIN desc_base[10]
    DIRECTION OUTPUT ;
    USE SIGNAL ;
    PORT
      LAYER M5 ;
        RECT  120.288 0 120.312 0.084 ;
    END
  END desc_base[10]
  PIN desc_base[11]
    DIRECTION OUTPUT ;
    USE SIGNAL ;
    PORT
      LAYER M5 ;
        RECT  120.384 0 120.408 0.084 ;
    END
  END desc_base[11]
  PIN desc_base[1]
    DIRECTION OUTPUT ;
    USE SIGNAL ;
    PORT
      LAYER M5 ;
        RECT  119.424 0 119.448 0.084 ;
    END
  END desc_base[1]
  PIN desc_base[2]
    DIRECTION OUTPUT ;
    USE SIGNAL ;
    PORT
      LAYER M5 ;
        RECT  119.52 0 119.544 0.084 ;
    END
  END desc_base[2]
  PIN desc_base[3]
    DIRECTION OUTPUT ;
    USE SIGNAL ;
    PORT
      LAYER M5 ;
        RECT  119.616 0 119.64 0.084 ;
    END
  END desc_base[3]
  PIN desc_base[4]
    DIRECTION OUTPUT ;
    USE SIGNAL ;
    PORT
      LAYER M5 ;
        RECT  119.712 0 119.736 0.084 ;
    END
  END desc_base[4]
  PIN desc_base[5]
    DIRECTION OUTPUT ;
    USE SIGNAL ;
    PORT
      LAYER M5 ;
        RECT  119.808 0 119.832 0.084 ;
    END
  END desc_base[5]
  PIN desc_base[6]
    DIRECTION OUTPUT ;
    USE SIGNAL ;
    PORT
      LAYER M5 ;
        RECT  119.904 0 119.928 0.084 ;
    END
  END desc_base[6]
  PIN desc_base[7]
    DIRECTION OUTPUT ;
    USE SIGNAL ;
    PORT
      LAYER M5 ;
        RECT  120 0 120.024 0.084 ;
    END
  END desc_base[7]
  PIN desc_base[8]
    DIRECTION OUTPUT ;
    USE SIGNAL ;
    PORT
      LAYER M5 ;
        RECT  120.096 0 120.12 0.084 ;
    END
  END desc_base[8]
  PIN desc_base[9]
    DIRECTION OUTPUT ;
    USE SIGNAL ;
    PORT
      LAYER M5 ;
        RECT  120.192 0 120.216 0.084 ;
    END
  END desc_base[9]
  PIN desc_limit[0]
    DIRECTION OUTPUT ;
    USE SIGNAL ;
    PORT
      LAYER M5 ;
        RECT  120.48 0 120.504 0.084 ;
    END
  END desc_limit[0]
  PIN desc_limit[10]
    DIRECTION OUTPUT ;
    USE SIGNAL ;
    PORT
      LAYER M5 ;
        RECT  121.44 0 121.464 0.084 ;
    END
  END desc_limit[10]
  PIN desc_limit[11]
    DIRECTION OUTPUT ;
    USE SIGNAL ;
    PORT
      LAYER M5 ;
        RECT  121.536 0 121.56 0.084 ;
    END
  END desc_limit[11]
  PIN desc_limit[12]
    DIRECTION OUTPUT ;
    USE SIGNAL ;
    PORT
      LAYER M5 ;
        RECT  121.632 0 121.656 0.084 ;
    END
  END desc_limit[12]
  PIN desc_limit[1]
    DIRECTION OUTPUT ;
    USE SIGNAL ;
    PORT
      LAYER M5 ;
        RECT  120.576 0 120.6 0.084 ;
    END
  END desc_limit[1]
  PIN desc_limit[2]
    DIRECTION OUTPUT ;
    USE SIGNAL ;
    PORT
      LAYER M5 ;
        RECT  120.672 0 120.696 0.084 ;
    END
  END desc_limit[2]
  PIN desc_limit[3]
    DIRECTION OUTPUT ;
    USE SIGNAL ;
    PORT
      LAYER M5 ;
        RECT  120.768 0 120.792 0.084 ;
    END
  END desc_limit[3]
  PIN desc_limit[4]
    DIRECTION OUTPUT ;
    USE SIGNAL ;
    PORT
      LAYER M5 ;
        RECT  120.864 0 120.888 0.084 ;
    END
  END desc_limit[4]
  PIN desc_limit[5]
    DIRECTION OUTPUT ;
    USE SIGNAL ;
    PORT
      LAYER M5 ;
        RECT  120.96 0 120.984 0.084 ;
    END
  END desc_limit[5]
  PIN desc_limit[6]
    DIRECTION OUTPUT ;
    USE SIGNAL ;
    PORT
      LAYER M5 ;
        RECT  121.056 0 121.08 0.084 ;
    END
  END desc_limit[6]
  PIN desc_limit[7]
    DIRECTION OUTPUT ;
    USE SIGNAL ;
    PORT
      LAYER M5 ;
        RECT  121.152 0 121.176 0.084 ;
    END
  END desc_limit[7]
  PIN desc_limit[8]
    DIRECTION OUTPUT ;
    USE SIGNAL ;
    PORT
      LAYER M5 ;
        RECT  121.248 0 121.272 0.084 ;
    END
  END desc_limit[8]
  PIN desc_limit[9]
    DIRECTION OUTPUT ;
    USE SIGNAL ;
    PORT
      LAYER M5 ;
        RECT  121.344 0 121.368 0.084 ;
    END
  END desc_limit[9]
  PIN desc_loops[0]
    DIRECTION OUTPUT ;
    USE SIGNAL ;
    PORT
      LAYER M5 ;
        RECT  121.728 0 121.752 0.084 ;
    END
  END desc_loops[0]
  PIN desc_loops[10]
    DIRECTION OUTPUT ;
    USE SIGNAL ;
    PORT
      LAYER M5 ;
        RECT  122.688 0 122.712 0.084 ;
    END
  END desc_loops[10]
  PIN desc_loops[11]
    DIRECTION OUTPUT ;
    USE SIGNAL ;
    PORT
      LAYER M5 ;
        RECT  122.784 0 122.808 0.084 ;
    END
  END desc_loops[11]
  PIN desc_loops[12]
    DIRECTION OUTPUT ;
    USE SIGNAL ;
    PORT
      LAYER M5 ;
        RECT  122.88 0 122.904 0.084 ;
    END
  END desc_loops[12]
  PIN desc_loops[13]
    DIRECTION OUTPUT ;
    USE SIGNAL ;
    PORT
      LAYER M5 ;
        RECT  122.976 0 123 0.084 ;
    END
  END desc_loops[13]
  PIN desc_loops[14]
    DIRECTION OUTPUT ;
    USE SIGNAL ;
    PORT
      LAYER M5 ;
        RECT  123.072 0 123.096 0.084 ;
    END
  END desc_loops[14]
  PIN desc_loops[15]
    DIRECTION OUTPUT ;
    USE SIGNAL ;
    PORT
      LAYER M5 ;
        RECT  123.168 0 123.192 0.084 ;
    END
  END desc_loops[15]
  PIN desc_loops[1]
    DIRECTION OUTPUT ;
    USE SIGNAL ;
    PORT
      LAYER M5 ;
        RECT  121.824 0 121.848 0.084 ;
    END
  END desc_loops[1]
  PIN desc_loops[2]
    DIRECTION OUTPUT ;
    USE SIGNAL ;
    PORT
      LAYER M5 ;
        RECT  121.92 0 121.944 0.084 ;
    END
  END desc_loops[2]
  PIN desc_loops[3]
    DIRECTION OUTPUT ;
    USE SIGNAL ;
    PORT
      LAYER M5 ;
        RECT  122.016 0 122.04 0.084 ;
    END
  END desc_loops[3]
  PIN desc_loops[4]
    DIRECTION OUTPUT ;
    USE SIGNAL ;
    PORT
      LAYER M5 ;
        RECT  122.112 0 122.136 0.084 ;
    END
  END desc_loops[4]
  PIN desc_loops[5]
    DIRECTION OUTPUT ;
    USE SIGNAL ;
    PORT
      LAYER M5 ;
        RECT  122.208 0 122.232 0.084 ;
    END
  END desc_loops[5]
  PIN desc_loops[6]
    DIRECTION OUTPUT ;
    USE SIGNAL ;
    PORT
      LAYER M5 ;
        RECT  122.304 0 122.328 0.084 ;
    END
  END desc_loops[6]
  PIN desc_loops[7]
    DIRECTION OUTPUT ;
    USE SIGNAL ;
    PORT
      LAYER M5 ;
        RECT  122.4 0 122.424 0.084 ;
    END
  END desc_loops[7]
  PIN desc_loops[8]
    DIRECTION OUTPUT ;
    USE SIGNAL ;
    PORT
      LAYER M5 ;
        RECT  122.496 0 122.52 0.084 ;
    END
  END desc_loops[8]
  PIN desc_loops[9]
    DIRECTION OUTPUT ;
    USE SIGNAL ;
    PORT
      LAYER M5 ;
        RECT  122.592 0 122.616 0.084 ;
    END
  END desc_loops[9]
  PIN desc_v
    DIRECTION OUTPUT ;
    USE SIGNAL ;
    PORT
      LAYER M5 ;
        RECT  119.232 0 119.256 0.084 ;
    END
  END desc_v
  PIN fault
    DIRECTION OUTPUT ;
    USE SIGNAL ;
    PORT
      LAYER M5 ;
        RECT  123.36 0 123.384 0.084 ;
    END
  END fault
  PIN launch_v
    DIRECTION OUTPUT ;
    USE SIGNAL ;
    PORT
      LAYER M5 ;
        RECT  123.264 0 123.288 0.084 ;
    END
  END launch_v
  PIN program_active
    DIRECTION INPUT ;
    USE SIGNAL ;
    PORT
      LAYER M5 ;
        RECT  108.096 215.916 108.12 216 ;
    END
  END program_active
  PIN program_fault
    DIRECTION INPUT ;
    USE SIGNAL ;
    PORT
      LAYER M5 ;
        RECT  108.192 215.916 108.216 216 ;
    END
  END program_fault
  PIN rst_n
    DIRECTION INPUT ;
    USE SIGNAL ;
    PORT
      LAYER M5 ;
        RECT  107.904 215.916 107.928 216 ;
    END
  END rst_n
  PIN s_araddr[0]
    DIRECTION INPUT ;
    USE SIGNAL ;
    PORT
      LAYER M4 ;
        RECT  0 108.624 0.084 108.648 ;
    END
  END s_araddr[0]
  PIN s_araddr[10]
    DIRECTION INPUT ;
    USE SIGNAL ;
    PORT
      LAYER M4 ;
        RECT  0 109.584 0.084 109.608 ;
    END
  END s_araddr[10]
  PIN s_araddr[11]
    DIRECTION INPUT ;
    USE SIGNAL ;
    PORT
      LAYER M4 ;
        RECT  0 109.68 0.084 109.704 ;
    END
  END s_araddr[11]
  PIN s_araddr[1]
    DIRECTION INPUT ;
    USE SIGNAL ;
    PORT
      LAYER M4 ;
        RECT  0 108.72 0.084 108.744 ;
    END
  END s_araddr[1]
  PIN s_araddr[2]
    DIRECTION INPUT ;
    USE SIGNAL ;
    PORT
      LAYER M4 ;
        RECT  0 108.816 0.084 108.84 ;
    END
  END s_araddr[2]
  PIN s_araddr[3]
    DIRECTION INPUT ;
    USE SIGNAL ;
    PORT
      LAYER M4 ;
        RECT  0 108.912 0.084 108.936 ;
    END
  END s_araddr[3]
  PIN s_araddr[4]
    DIRECTION INPUT ;
    USE SIGNAL ;
    PORT
      LAYER M4 ;
        RECT  0 109.008 0.084 109.032 ;
    END
  END s_araddr[4]
  PIN s_araddr[5]
    DIRECTION INPUT ;
    USE SIGNAL ;
    PORT
      LAYER M4 ;
        RECT  0 109.104 0.084 109.128 ;
    END
  END s_araddr[5]
  PIN s_araddr[6]
    DIRECTION INPUT ;
    USE SIGNAL ;
    PORT
      LAYER M4 ;
        RECT  0 109.2 0.084 109.224 ;
    END
  END s_araddr[6]
  PIN s_araddr[7]
    DIRECTION INPUT ;
    USE SIGNAL ;
    PORT
      LAYER M4 ;
        RECT  0 109.296 0.084 109.32 ;
    END
  END s_araddr[7]
  PIN s_araddr[8]
    DIRECTION INPUT ;
    USE SIGNAL ;
    PORT
      LAYER M4 ;
        RECT  0 109.392 0.084 109.416 ;
    END
  END s_araddr[8]
  PIN s_araddr[9]
    DIRECTION INPUT ;
    USE SIGNAL ;
    PORT
      LAYER M4 ;
        RECT  0 109.488 0.084 109.512 ;
    END
  END s_araddr[9]
  PIN s_arready
    DIRECTION OUTPUT ;
    USE SIGNAL ;
    PORT
      LAYER M4 ;
        RECT  0 108.528 0.084 108.552 ;
    END
  END s_arready
  PIN s_arvalid
    DIRECTION INPUT ;
    USE SIGNAL ;
    PORT
      LAYER M4 ;
        RECT  0 108.432 0.084 108.456 ;
    END
  END s_arvalid
  PIN s_awaddr[0]
    DIRECTION INPUT ;
    USE SIGNAL ;
    PORT
      LAYER M4 ;
        RECT  0 103.248 0.084 103.272 ;
    END
  END s_awaddr[0]
  PIN s_awaddr[10]
    DIRECTION INPUT ;
    USE SIGNAL ;
    PORT
      LAYER M4 ;
        RECT  0 104.208 0.084 104.232 ;
    END
  END s_awaddr[10]
  PIN s_awaddr[11]
    DIRECTION INPUT ;
    USE SIGNAL ;
    PORT
      LAYER M4 ;
        RECT  0 104.304 0.084 104.328 ;
    END
  END s_awaddr[11]
  PIN s_awaddr[1]
    DIRECTION INPUT ;
    USE SIGNAL ;
    PORT
      LAYER M4 ;
        RECT  0 103.344 0.084 103.368 ;
    END
  END s_awaddr[1]
  PIN s_awaddr[2]
    DIRECTION INPUT ;
    USE SIGNAL ;
    PORT
      LAYER M4 ;
        RECT  0 103.44 0.084 103.464 ;
    END
  END s_awaddr[2]
  PIN s_awaddr[3]
    DIRECTION INPUT ;
    USE SIGNAL ;
    PORT
      LAYER M4 ;
        RECT  0 103.536 0.084 103.56 ;
    END
  END s_awaddr[3]
  PIN s_awaddr[4]
    DIRECTION INPUT ;
    USE SIGNAL ;
    PORT
      LAYER M4 ;
        RECT  0 103.632 0.084 103.656 ;
    END
  END s_awaddr[4]
  PIN s_awaddr[5]
    DIRECTION INPUT ;
    USE SIGNAL ;
    PORT
      LAYER M4 ;
        RECT  0 103.728 0.084 103.752 ;
    END
  END s_awaddr[5]
  PIN s_awaddr[6]
    DIRECTION INPUT ;
    USE SIGNAL ;
    PORT
      LAYER M4 ;
        RECT  0 103.824 0.084 103.848 ;
    END
  END s_awaddr[6]
  PIN s_awaddr[7]
    DIRECTION INPUT ;
    USE SIGNAL ;
    PORT
      LAYER M4 ;
        RECT  0 103.92 0.084 103.944 ;
    END
  END s_awaddr[7]
  PIN s_awaddr[8]
    DIRECTION INPUT ;
    USE SIGNAL ;
    PORT
      LAYER M4 ;
        RECT  0 104.016 0.084 104.04 ;
    END
  END s_awaddr[8]
  PIN s_awaddr[9]
    DIRECTION INPUT ;
    USE SIGNAL ;
    PORT
      LAYER M4 ;
        RECT  0 104.112 0.084 104.136 ;
    END
  END s_awaddr[9]
  PIN s_awready
    DIRECTION OUTPUT ;
    USE SIGNAL ;
    PORT
      LAYER M4 ;
        RECT  0 103.152 0.084 103.176 ;
    END
  END s_awready
  PIN s_awvalid
    DIRECTION INPUT ;
    USE SIGNAL ;
    PORT
      LAYER M4 ;
        RECT  0 103.056 0.084 103.08 ;
    END
  END s_awvalid
  PIN s_bready
    DIRECTION INPUT ;
    USE SIGNAL ;
    PORT
      LAYER M4 ;
        RECT  0 108.144 0.084 108.168 ;
    END
  END s_bready
  PIN s_bresp[0]
    DIRECTION OUTPUT ;
    USE SIGNAL ;
    PORT
      LAYER M4 ;
        RECT  0 108.24 0.084 108.264 ;
    END
  END s_bresp[0]
  PIN s_bresp[1]
    DIRECTION OUTPUT ;
    USE SIGNAL ;
    PORT
      LAYER M4 ;
        RECT  0 108.336 0.084 108.36 ;
    END
  END s_bresp[1]
  PIN s_bvalid
    DIRECTION OUTPUT ;
    USE SIGNAL ;
    PORT
      LAYER M4 ;
        RECT  0 108.048 0.084 108.072 ;
    END
  END s_bvalid
  PIN s_rdata[0]
    DIRECTION OUTPUT ;
    USE SIGNAL ;
    PORT
      LAYER M4 ;
        RECT  0 109.968 0.084 109.992 ;
    END
  END s_rdata[0]
  PIN s_rdata[10]
    DIRECTION OUTPUT ;
    USE SIGNAL ;
    PORT
      LAYER M4 ;
        RECT  0 110.928 0.084 110.952 ;
    END
  END s_rdata[10]
  PIN s_rdata[11]
    DIRECTION OUTPUT ;
    USE SIGNAL ;
    PORT
      LAYER M4 ;
        RECT  0 111.024 0.084 111.048 ;
    END
  END s_rdata[11]
  PIN s_rdata[12]
    DIRECTION OUTPUT ;
    USE SIGNAL ;
    PORT
      LAYER M4 ;
        RECT  0 111.12 0.084 111.144 ;
    END
  END s_rdata[12]
  PIN s_rdata[13]
    DIRECTION OUTPUT ;
    USE SIGNAL ;
    PORT
      LAYER M4 ;
        RECT  0 111.216 0.084 111.24 ;
    END
  END s_rdata[13]
  PIN s_rdata[14]
    DIRECTION OUTPUT ;
    USE SIGNAL ;
    PORT
      LAYER M4 ;
        RECT  0 111.312 0.084 111.336 ;
    END
  END s_rdata[14]
  PIN s_rdata[15]
    DIRECTION OUTPUT ;
    USE SIGNAL ;
    PORT
      LAYER M4 ;
        RECT  0 111.408 0.084 111.432 ;
    END
  END s_rdata[15]
  PIN s_rdata[16]
    DIRECTION OUTPUT ;
    USE SIGNAL ;
    PORT
      LAYER M4 ;
        RECT  0 111.504 0.084 111.528 ;
    END
  END s_rdata[16]
  PIN s_rdata[17]
    DIRECTION OUTPUT ;
    USE SIGNAL ;
    PORT
      LAYER M4 ;
        RECT  0 111.6 0.084 111.624 ;
    END
  END s_rdata[17]
  PIN s_rdata[18]
    DIRECTION OUTPUT ;
    USE SIGNAL ;
    PORT
      LAYER M4 ;
        RECT  0 111.696 0.084 111.72 ;
    END
  END s_rdata[18]
  PIN s_rdata[19]
    DIRECTION OUTPUT ;
    USE SIGNAL ;
    PORT
      LAYER M4 ;
        RECT  0 111.792 0.084 111.816 ;
    END
  END s_rdata[19]
  PIN s_rdata[1]
    DIRECTION OUTPUT ;
    USE SIGNAL ;
    PORT
      LAYER M4 ;
        RECT  0 110.064 0.084 110.088 ;
    END
  END s_rdata[1]
  PIN s_rdata[20]
    DIRECTION OUTPUT ;
    USE SIGNAL ;
    PORT
      LAYER M4 ;
        RECT  0 111.888 0.084 111.912 ;
    END
  END s_rdata[20]
  PIN s_rdata[21]
    DIRECTION OUTPUT ;
    USE SIGNAL ;
    PORT
      LAYER M4 ;
        RECT  0 111.984 0.084 112.008 ;
    END
  END s_rdata[21]
  PIN s_rdata[22]
    DIRECTION OUTPUT ;
    USE SIGNAL ;
    PORT
      LAYER M4 ;
        RECT  0 112.08 0.084 112.104 ;
    END
  END s_rdata[22]
  PIN s_rdata[23]
    DIRECTION OUTPUT ;
    USE SIGNAL ;
    PORT
      LAYER M4 ;
        RECT  0 112.176 0.084 112.2 ;
    END
  END s_rdata[23]
  PIN s_rdata[24]
    DIRECTION OUTPUT ;
    USE SIGNAL ;
    PORT
      LAYER M4 ;
        RECT  0 112.272 0.084 112.296 ;
    END
  END s_rdata[24]
  PIN s_rdata[25]
    DIRECTION OUTPUT ;
    USE SIGNAL ;
    PORT
      LAYER M4 ;
        RECT  0 112.368 0.084 112.392 ;
    END
  END s_rdata[25]
  PIN s_rdata[26]
    DIRECTION OUTPUT ;
    USE SIGNAL ;
    PORT
      LAYER M4 ;
        RECT  0 112.464 0.084 112.488 ;
    END
  END s_rdata[26]
  PIN s_rdata[27]
    DIRECTION OUTPUT ;
    USE SIGNAL ;
    PORT
      LAYER M4 ;
        RECT  0 112.56 0.084 112.584 ;
    END
  END s_rdata[27]
  PIN s_rdata[28]
    DIRECTION OUTPUT ;
    USE SIGNAL ;
    PORT
      LAYER M4 ;
        RECT  0 112.656 0.084 112.68 ;
    END
  END s_rdata[28]
  PIN s_rdata[29]
    DIRECTION OUTPUT ;
    USE SIGNAL ;
    PORT
      LAYER M4 ;
        RECT  0 112.752 0.084 112.776 ;
    END
  END s_rdata[29]
  PIN s_rdata[2]
    DIRECTION OUTPUT ;
    USE SIGNAL ;
    PORT
      LAYER M4 ;
        RECT  0 110.16 0.084 110.184 ;
    END
  END s_rdata[2]
  PIN s_rdata[30]
    DIRECTION OUTPUT ;
    USE SIGNAL ;
    PORT
      LAYER M4 ;
        RECT  0 112.848 0.084 112.872 ;
    END
  END s_rdata[30]
  PIN s_rdata[31]
    DIRECTION OUTPUT ;
    USE SIGNAL ;
    PORT
      LAYER M4 ;
        RECT  0 112.944 0.084 112.968 ;
    END
  END s_rdata[31]
  PIN s_rdata[3]
    DIRECTION OUTPUT ;
    USE SIGNAL ;
    PORT
      LAYER M4 ;
        RECT  0 110.256 0.084 110.28 ;
    END
  END s_rdata[3]
  PIN s_rdata[4]
    DIRECTION OUTPUT ;
    USE SIGNAL ;
    PORT
      LAYER M4 ;
        RECT  0 110.352 0.084 110.376 ;
    END
  END s_rdata[4]
  PIN s_rdata[5]
    DIRECTION OUTPUT ;
    USE SIGNAL ;
    PORT
      LAYER M4 ;
        RECT  0 110.448 0.084 110.472 ;
    END
  END s_rdata[5]
  PIN s_rdata[6]
    DIRECTION OUTPUT ;
    USE SIGNAL ;
    PORT
      LAYER M4 ;
        RECT  0 110.544 0.084 110.568 ;
    END
  END s_rdata[6]
  PIN s_rdata[7]
    DIRECTION OUTPUT ;
    USE SIGNAL ;
    PORT
      LAYER M4 ;
        RECT  0 110.64 0.084 110.664 ;
    END
  END s_rdata[7]
  PIN s_rdata[8]
    DIRECTION OUTPUT ;
    USE SIGNAL ;
    PORT
      LAYER M4 ;
        RECT  0 110.736 0.084 110.76 ;
    END
  END s_rdata[8]
  PIN s_rdata[9]
    DIRECTION OUTPUT ;
    USE SIGNAL ;
    PORT
      LAYER M4 ;
        RECT  0 110.832 0.084 110.856 ;
    END
  END s_rdata[9]
  PIN s_rready
    DIRECTION INPUT ;
    USE SIGNAL ;
    PORT
      LAYER M4 ;
        RECT  0 109.872 0.084 109.896 ;
    END
  END s_rready
  PIN s_rvalid
    DIRECTION OUTPUT ;
    USE SIGNAL ;
    PORT
      LAYER M4 ;
        RECT  0 109.776 0.084 109.8 ;
    END
  END s_rvalid
  PIN s_wdata[0]
    DIRECTION INPUT ;
    USE SIGNAL ;
    PORT
      LAYER M4 ;
        RECT  0 104.592 0.084 104.616 ;
    END
  END s_wdata[0]
  PIN s_wdata[10]
    DIRECTION INPUT ;
    USE SIGNAL ;
    PORT
      LAYER M4 ;
        RECT  0 105.552 0.084 105.576 ;
    END
  END s_wdata[10]
  PIN s_wdata[11]
    DIRECTION INPUT ;
    USE SIGNAL ;
    PORT
      LAYER M4 ;
        RECT  0 105.648 0.084 105.672 ;
    END
  END s_wdata[11]
  PIN s_wdata[12]
    DIRECTION INPUT ;
    USE SIGNAL ;
    PORT
      LAYER M4 ;
        RECT  0 105.744 0.084 105.768 ;
    END
  END s_wdata[12]
  PIN s_wdata[13]
    DIRECTION INPUT ;
    USE SIGNAL ;
    PORT
      LAYER M4 ;
        RECT  0 105.84 0.084 105.864 ;
    END
  END s_wdata[13]
  PIN s_wdata[14]
    DIRECTION INPUT ;
    USE SIGNAL ;
    PORT
      LAYER M4 ;
        RECT  0 105.936 0.084 105.96 ;
    END
  END s_wdata[14]
  PIN s_wdata[15]
    DIRECTION INPUT ;
    USE SIGNAL ;
    PORT
      LAYER M4 ;
        RECT  0 106.032 0.084 106.056 ;
    END
  END s_wdata[15]
  PIN s_wdata[16]
    DIRECTION INPUT ;
    USE SIGNAL ;
    PORT
      LAYER M4 ;
        RECT  0 106.128 0.084 106.152 ;
    END
  END s_wdata[16]
  PIN s_wdata[17]
    DIRECTION INPUT ;
    USE SIGNAL ;
    PORT
      LAYER M4 ;
        RECT  0 106.224 0.084 106.248 ;
    END
  END s_wdata[17]
  PIN s_wdata[18]
    DIRECTION INPUT ;
    USE SIGNAL ;
    PORT
      LAYER M4 ;
        RECT  0 106.32 0.084 106.344 ;
    END
  END s_wdata[18]
  PIN s_wdata[19]
    DIRECTION INPUT ;
    USE SIGNAL ;
    PORT
      LAYER M4 ;
        RECT  0 106.416 0.084 106.44 ;
    END
  END s_wdata[19]
  PIN s_wdata[1]
    DIRECTION INPUT ;
    USE SIGNAL ;
    PORT
      LAYER M4 ;
        RECT  0 104.688 0.084 104.712 ;
    END
  END s_wdata[1]
  PIN s_wdata[20]
    DIRECTION INPUT ;
    USE SIGNAL ;
    PORT
      LAYER M4 ;
        RECT  0 106.512 0.084 106.536 ;
    END
  END s_wdata[20]
  PIN s_wdata[21]
    DIRECTION INPUT ;
    USE SIGNAL ;
    PORT
      LAYER M4 ;
        RECT  0 106.608 0.084 106.632 ;
    END
  END s_wdata[21]
  PIN s_wdata[22]
    DIRECTION INPUT ;
    USE SIGNAL ;
    PORT
      LAYER M4 ;
        RECT  0 106.704 0.084 106.728 ;
    END
  END s_wdata[22]
  PIN s_wdata[23]
    DIRECTION INPUT ;
    USE SIGNAL ;
    PORT
      LAYER M4 ;
        RECT  0 106.8 0.084 106.824 ;
    END
  END s_wdata[23]
  PIN s_wdata[24]
    DIRECTION INPUT ;
    USE SIGNAL ;
    PORT
      LAYER M4 ;
        RECT  0 106.896 0.084 106.92 ;
    END
  END s_wdata[24]
  PIN s_wdata[25]
    DIRECTION INPUT ;
    USE SIGNAL ;
    PORT
      LAYER M4 ;
        RECT  0 106.992 0.084 107.016 ;
    END
  END s_wdata[25]
  PIN s_wdata[26]
    DIRECTION INPUT ;
    USE SIGNAL ;
    PORT
      LAYER M4 ;
        RECT  0 107.088 0.084 107.112 ;
    END
  END s_wdata[26]
  PIN s_wdata[27]
    DIRECTION INPUT ;
    USE SIGNAL ;
    PORT
      LAYER M4 ;
        RECT  0 107.184 0.084 107.208 ;
    END
  END s_wdata[27]
  PIN s_wdata[28]
    DIRECTION INPUT ;
    USE SIGNAL ;
    PORT
      LAYER M4 ;
        RECT  0 107.28 0.084 107.304 ;
    END
  END s_wdata[28]
  PIN s_wdata[29]
    DIRECTION INPUT ;
    USE SIGNAL ;
    PORT
      LAYER M4 ;
        RECT  0 107.376 0.084 107.4 ;
    END
  END s_wdata[29]
  PIN s_wdata[2]
    DIRECTION INPUT ;
    USE SIGNAL ;
    PORT
      LAYER M4 ;
        RECT  0 104.784 0.084 104.808 ;
    END
  END s_wdata[2]
  PIN s_wdata[30]
    DIRECTION INPUT ;
    USE SIGNAL ;
    PORT
      LAYER M4 ;
        RECT  0 107.472 0.084 107.496 ;
    END
  END s_wdata[30]
  PIN s_wdata[31]
    DIRECTION INPUT ;
    USE SIGNAL ;
    PORT
      LAYER M4 ;
        RECT  0 107.568 0.084 107.592 ;
    END
  END s_wdata[31]
  PIN s_wdata[3]
    DIRECTION INPUT ;
    USE SIGNAL ;
    PORT
      LAYER M4 ;
        RECT  0 104.88 0.084 104.904 ;
    END
  END s_wdata[3]
  PIN s_wdata[4]
    DIRECTION INPUT ;
    USE SIGNAL ;
    PORT
      LAYER M4 ;
        RECT  0 104.976 0.084 105 ;
    END
  END s_wdata[4]
  PIN s_wdata[5]
    DIRECTION INPUT ;
    USE SIGNAL ;
    PORT
      LAYER M4 ;
        RECT  0 105.072 0.084 105.096 ;
    END
  END s_wdata[5]
  PIN s_wdata[6]
    DIRECTION INPUT ;
    USE SIGNAL ;
    PORT
      LAYER M4 ;
        RECT  0 105.168 0.084 105.192 ;
    END
  END s_wdata[6]
  PIN s_wdata[7]
    DIRECTION INPUT ;
    USE SIGNAL ;
    PORT
      LAYER M4 ;
        RECT  0 105.264 0.084 105.288 ;
    END
  END s_wdata[7]
  PIN s_wdata[8]
    DIRECTION INPUT ;
    USE SIGNAL ;
    PORT
      LAYER M4 ;
        RECT  0 105.36 0.084 105.384 ;
    END
  END s_wdata[8]
  PIN s_wdata[9]
    DIRECTION INPUT ;
    USE SIGNAL ;
    PORT
      LAYER M4 ;
        RECT  0 105.456 0.084 105.48 ;
    END
  END s_wdata[9]
  PIN s_wready
    DIRECTION OUTPUT ;
    USE SIGNAL ;
    PORT
      LAYER M4 ;
        RECT  0 104.496 0.084 104.52 ;
    END
  END s_wready
  PIN s_wstrb[0]
    DIRECTION INPUT ;
    USE SIGNAL ;
    PORT
      LAYER M4 ;
        RECT  0 107.664 0.084 107.688 ;
    END
  END s_wstrb[0]
  PIN s_wstrb[1]
    DIRECTION INPUT ;
    USE SIGNAL ;
    PORT
      LAYER M4 ;
        RECT  0 107.76 0.084 107.784 ;
    END
  END s_wstrb[1]
  PIN s_wstrb[2]
    DIRECTION INPUT ;
    USE SIGNAL ;
    PORT
      LAYER M4 ;
        RECT  0 107.856 0.084 107.88 ;
    END
  END s_wstrb[2]
  PIN s_wstrb[3]
    DIRECTION INPUT ;
    USE SIGNAL ;
    PORT
      LAYER M4 ;
        RECT  0 107.952 0.084 107.976 ;
    END
  END s_wstrb[3]
  PIN s_wvalid
    DIRECTION INPUT ;
    USE SIGNAL ;
    PORT
      LAYER M4 ;
        RECT  0 104.4 0.084 104.424 ;
    END
  END s_wvalid
  PIN VDD
    DIRECTION INOUT ;
    USE POWER ;
    PORT
      LAYER M5 ;
        RECT  213.192 2.151 213.312 213.849 ;
        RECT  207.792 2.151 207.912 213.849 ;
        RECT  202.392 2.151 202.512 213.849 ;
        RECT  196.992 2.151 197.112 213.849 ;
        RECT  191.592 2.151 191.712 213.849 ;
        RECT  186.192 2.151 186.312 213.849 ;
        RECT  180.792 2.151 180.912 213.849 ;
        RECT  175.392 2.151 175.512 213.849 ;
        RECT  169.992 2.151 170.112 213.849 ;
        RECT  164.592 2.151 164.712 213.849 ;
        RECT  159.192 2.151 159.312 213.849 ;
        RECT  153.792 2.151 153.912 213.849 ;
        RECT  148.392 2.151 148.512 213.849 ;
        RECT  142.992 2.151 143.112 213.849 ;
        RECT  137.592 2.151 137.712 213.849 ;
        RECT  132.192 2.151 132.312 213.849 ;
        RECT  126.792 2.151 126.912 213.849 ;
        RECT  121.392 2.151 121.512 213.849 ;
        RECT  115.992 2.151 116.112 213.849 ;
        RECT  110.592 2.151 110.712 213.849 ;
        RECT  105.192 2.151 105.312 213.849 ;
        RECT  99.792 2.151 99.912 213.849 ;
        RECT  94.392 2.151 94.512 213.849 ;
        RECT  88.992 2.151 89.112 213.849 ;
        RECT  83.592 2.151 83.712 213.849 ;
        RECT  78.192 2.151 78.312 213.849 ;
        RECT  72.792 2.151 72.912 213.849 ;
        RECT  67.392 2.151 67.512 213.849 ;
        RECT  61.992 2.151 62.112 213.849 ;
        RECT  56.592 2.151 56.712 213.849 ;
        RECT  51.192 2.151 51.312 213.849 ;
        RECT  45.792 2.151 45.912 213.849 ;
        RECT  40.392 2.151 40.512 213.849 ;
        RECT  34.992 2.151 35.112 213.849 ;
        RECT  29.592 2.151 29.712 213.849 ;
        RECT  24.192 2.151 24.312 213.849 ;
        RECT  18.792 2.151 18.912 213.849 ;
        RECT  13.392 2.151 13.512 213.849 ;
        RECT  7.992 2.151 8.112 213.849 ;
        RECT  2.592 2.151 2.712 213.849 ;
    END
  END VDD
  PIN VSS
    DIRECTION INOUT ;
    USE GROUND ;
    PORT
      LAYER M5 ;
        RECT  213 2.137 213.12 213.863 ;
        RECT  207.6 2.137 207.72 213.863 ;
        RECT  202.2 2.137 202.32 213.863 ;
        RECT  196.8 2.137 196.92 213.863 ;
        RECT  191.4 2.137 191.52 213.863 ;
        RECT  186 2.137 186.12 213.863 ;
        RECT  180.6 2.137 180.72 213.863 ;
        RECT  175.2 2.137 175.32 213.863 ;
        RECT  169.8 2.137 169.92 213.863 ;
        RECT  164.4 2.137 164.52 213.863 ;
        RECT  159 2.137 159.12 213.863 ;
        RECT  153.6 2.137 153.72 213.863 ;
        RECT  148.2 2.137 148.32 213.863 ;
        RECT  142.8 2.137 142.92 213.863 ;
        RECT  137.4 2.137 137.52 213.863 ;
        RECT  132 2.137 132.12 213.863 ;
        RECT  126.6 2.137 126.72 213.863 ;
        RECT  121.2 2.137 121.32 213.863 ;
        RECT  115.8 2.137 115.92 213.863 ;
        RECT  110.4 2.137 110.52 213.863 ;
        RECT  105 2.137 105.12 213.863 ;
        RECT  99.6 2.137 99.72 213.863 ;
        RECT  94.2 2.137 94.32 213.863 ;
        RECT  88.8 2.137 88.92 213.863 ;
        RECT  83.4 2.137 83.52 213.863 ;
        RECT  78 2.137 78.12 213.863 ;
        RECT  72.6 2.137 72.72 213.863 ;
        RECT  67.2 2.137 67.32 213.863 ;
        RECT  61.8 2.137 61.92 213.863 ;
        RECT  56.4 2.137 56.52 213.863 ;
        RECT  51 2.137 51.12 213.863 ;
        RECT  45.6 2.137 45.72 213.863 ;
        RECT  40.2 2.137 40.32 213.863 ;
        RECT  34.8 2.137 34.92 213.863 ;
        RECT  29.4 2.137 29.52 213.863 ;
        RECT  24 2.137 24.12 213.863 ;
        RECT  18.6 2.137 18.72 213.863 ;
        RECT  13.2 2.137 13.32 213.863 ;
        RECT  7.8 2.137 7.92 213.863 ;
        RECT  2.4 2.137 2.52 213.863 ;
    END
  END VSS
  # OT_OBS_CLOSED layer=M5 d_um=1.536 added=171
  OBS
    LAYER RVTN ;
     RECT  2.16 2.16 213.84 2.295 ;
     RECT  2.16 2.565 213.84 2.835 ;
     RECT  2.16 3.105 213.84 3.375 ;
     RECT  2.16 3.645 213.84 3.915 ;
     RECT  2.16 4.185 213.84 4.455 ;
     RECT  2.16 4.725 213.84 4.995 ;
     RECT  2.16 5.265 213.84 5.535 ;
     RECT  2.16 5.805 213.84 6.075 ;
     RECT  2.16 6.345 213.84 6.615 ;
     RECT  2.16 6.885 213.84 7.155 ;
     RECT  2.16 7.425 213.84 7.695 ;
     RECT  2.16 7.965 213.84 8.235 ;
     RECT  2.16 8.505 213.84 8.775 ;
     RECT  2.16 9.045 213.84 9.315 ;
     RECT  2.16 9.585 213.84 9.855 ;
     RECT  2.16 10.125 213.84 10.395 ;
     RECT  2.16 10.665 213.84 10.935 ;
     RECT  2.16 11.205 213.84 11.475 ;
     RECT  2.16 11.745 213.84 12.015 ;
     RECT  2.16 12.285 213.84 12.555 ;
     RECT  2.16 12.825 213.84 13.095 ;
     RECT  2.16 13.365 213.84 13.635 ;
     RECT  2.16 13.905 213.84 14.175 ;
     RECT  2.16 14.445 213.84 14.715 ;
     RECT  2.16 14.985 213.84 15.255 ;
     RECT  2.16 15.525 213.84 15.795 ;
     RECT  2.16 16.065 213.84 16.335 ;
     RECT  2.16 16.605 213.84 16.875 ;
     RECT  2.16 17.145 213.84 17.415 ;
     RECT  2.16 17.685 213.84 17.955 ;
     RECT  2.16 18.225 213.84 18.495 ;
     RECT  2.16 18.765 213.84 19.035 ;
     RECT  2.16 19.305 213.84 19.575 ;
     RECT  2.16 19.845 213.84 20.115 ;
     RECT  2.16 20.385 213.84 20.655 ;
     RECT  2.16 20.925 213.84 21.195 ;
     RECT  2.16 21.465 213.84 21.735 ;
     RECT  2.16 22.005 213.84 22.275 ;
     RECT  2.16 22.545 213.84 22.815 ;
     RECT  2.16 23.085 213.84 23.355 ;
     RECT  2.16 23.625 213.84 23.895 ;
     RECT  2.16 24.165 213.84 24.435 ;
     RECT  2.16 24.705 213.84 24.975 ;
     RECT  2.16 25.245 213.84 25.515 ;
     RECT  2.16 25.785 213.84 26.055 ;
     RECT  2.16 26.325 213.84 26.595 ;
     RECT  2.16 26.865 213.84 27.135 ;
     RECT  2.16 27.405 213.84 27.675 ;
     RECT  2.16 27.945 213.84 28.215 ;
     RECT  2.16 28.485 213.84 28.755 ;
     RECT  2.16 29.025 213.84 29.295 ;
     RECT  2.16 29.565 213.84 29.835 ;
     RECT  2.16 30.105 213.84 30.375 ;
     RECT  2.16 30.645 213.84 30.915 ;
     RECT  2.16 31.185 213.84 31.455 ;
     RECT  2.16 31.725 213.84 31.995 ;
     RECT  2.16 32.265 213.84 32.535 ;
     RECT  2.16 32.805 213.84 33.075 ;
     RECT  2.16 33.345 213.84 33.615 ;
     RECT  2.16 33.885 213.84 34.155 ;
     RECT  2.16 34.425 213.84 34.695 ;
     RECT  2.16 34.965 213.84 35.235 ;
     RECT  2.16 35.505 213.84 35.775 ;
     RECT  2.16 36.045 213.84 36.315 ;
     RECT  2.16 36.585 213.84 36.855 ;
     RECT  2.16 37.125 213.84 37.395 ;
     RECT  2.16 37.665 213.84 37.935 ;
     RECT  2.16 38.205 213.84 38.475 ;
     RECT  2.16 38.745 213.84 39.015 ;
     RECT  2.16 39.285 213.84 39.555 ;
     RECT  2.16 39.825 213.84 40.095 ;
     RECT  2.16 40.365 213.84 40.635 ;
     RECT  2.16 40.905 213.84 41.175 ;
     RECT  2.16 41.445 213.84 41.715 ;
     RECT  2.16 41.985 213.84 42.255 ;
     RECT  2.16 42.525 213.84 42.795 ;
     RECT  2.16 43.065 213.84 43.335 ;
     RECT  2.16 43.605 213.84 43.875 ;
     RECT  2.16 44.145 213.84 44.415 ;
     RECT  2.16 44.685 213.84 44.955 ;
     RECT  2.16 45.225 213.84 45.495 ;
     RECT  2.16 45.765 213.84 46.035 ;
     RECT  2.16 46.305 213.84 46.575 ;
     RECT  2.16 46.845 213.84 47.115 ;
     RECT  2.16 47.385 213.84 47.655 ;
     RECT  2.16 47.925 213.84 48.195 ;
     RECT  2.16 48.465 213.84 48.735 ;
     RECT  2.16 49.005 213.84 49.275 ;
     RECT  2.16 49.545 213.84 49.815 ;
     RECT  2.16 50.085 213.84 50.355 ;
     RECT  2.16 50.625 213.84 50.895 ;
     RECT  2.16 51.165 213.84 51.435 ;
     RECT  2.16 51.705 213.84 51.975 ;
     RECT  2.16 52.245 213.84 52.515 ;
     RECT  2.16 52.785 213.84 53.055 ;
     RECT  2.16 53.325 213.84 53.595 ;
     RECT  2.16 53.865 213.84 54.135 ;
     RECT  2.16 54.405 213.84 54.675 ;
     RECT  2.16 54.945 213.84 55.215 ;
     RECT  2.16 55.485 213.84 55.755 ;
     RECT  2.16 56.025 213.84 56.295 ;
     RECT  2.16 56.565 213.84 56.835 ;
     RECT  2.16 57.105 213.84 57.375 ;
     RECT  2.16 57.645 213.84 57.915 ;
     RECT  2.16 58.185 213.84 58.455 ;
     RECT  2.16 58.725 213.84 58.995 ;
     RECT  2.16 59.265 213.84 59.535 ;
     RECT  2.16 59.805 213.84 60.075 ;
     RECT  2.16 60.345 213.84 60.615 ;
     RECT  2.16 60.885 213.84 61.155 ;
     RECT  2.16 61.425 213.84 61.695 ;
     RECT  2.16 61.965 213.84 62.235 ;
     RECT  2.16 62.505 213.84 62.775 ;
     RECT  2.16 63.045 213.84 63.315 ;
     RECT  2.16 63.585 213.84 63.855 ;
     RECT  2.16 64.125 213.84 64.395 ;
     RECT  2.16 64.665 213.84 64.935 ;
     RECT  2.16 65.205 213.84 65.475 ;
     RECT  2.16 65.745 213.84 66.015 ;
     RECT  2.16 66.285 213.84 66.555 ;
     RECT  2.16 66.825 213.84 67.095 ;
     RECT  2.16 67.365 213.84 67.635 ;
     RECT  2.16 67.905 213.84 68.175 ;
     RECT  2.16 68.445 213.84 68.715 ;
     RECT  2.16 68.985 213.84 69.255 ;
     RECT  2.16 69.525 213.84 69.795 ;
     RECT  2.16 70.065 213.84 70.335 ;
     RECT  2.16 70.605 213.84 70.875 ;
     RECT  2.16 71.145 213.84 71.415 ;
     RECT  2.16 71.685 213.84 71.955 ;
     RECT  2.16 72.225 213.84 72.495 ;
     RECT  2.16 72.765 213.84 73.035 ;
     RECT  2.16 73.305 213.84 73.575 ;
     RECT  2.16 73.845 213.84 74.115 ;
     RECT  2.16 74.385 213.84 74.655 ;
     RECT  2.16 74.925 213.84 75.195 ;
     RECT  2.16 75.465 213.84 75.735 ;
     RECT  2.16 76.005 213.84 76.275 ;
     RECT  2.16 76.545 213.84 76.815 ;
     RECT  2.16 77.085 213.84 77.355 ;
     RECT  2.16 77.625 213.84 77.895 ;
     RECT  2.16 78.165 213.84 78.435 ;
     RECT  2.16 78.705 213.84 78.975 ;
     RECT  2.16 79.245 213.84 79.515 ;
     RECT  2.16 79.785 213.84 80.055 ;
     RECT  2.16 80.325 213.84 80.595 ;
     RECT  2.16 80.865 213.84 81.135 ;
     RECT  2.16 81.405 213.84 81.675 ;
     RECT  2.16 81.945 213.84 82.215 ;
     RECT  2.16 82.485 213.84 82.755 ;
     RECT  2.16 83.025 213.84 83.295 ;
     RECT  2.16 83.565 213.84 83.835 ;
     RECT  2.16 84.105 213.84 84.375 ;
     RECT  2.16 84.645 213.84 84.915 ;
     RECT  2.16 85.185 213.84 85.455 ;
     RECT  2.16 85.725 213.84 85.995 ;
     RECT  2.16 86.265 213.84 86.535 ;
     RECT  2.16 86.805 213.84 87.075 ;
     RECT  2.16 87.345 213.84 87.615 ;
     RECT  2.16 87.885 213.84 88.155 ;
     RECT  2.16 88.425 213.84 88.695 ;
     RECT  2.16 88.965 213.84 89.235 ;
     RECT  2.16 89.505 213.84 89.775 ;
     RECT  2.16 90.045 213.84 90.315 ;
     RECT  2.16 90.585 213.84 90.855 ;
     RECT  2.16 91.125 213.84 91.395 ;
     RECT  2.16 91.665 213.84 91.935 ;
     RECT  2.16 92.205 213.84 92.475 ;
     RECT  2.16 92.745 213.84 93.015 ;
     RECT  2.16 93.285 213.84 93.555 ;
     RECT  2.16 93.825 213.84 94.095 ;
     RECT  2.16 94.365 213.84 94.635 ;
     RECT  2.16 94.905 213.84 95.175 ;
     RECT  2.16 95.445 213.84 95.715 ;
     RECT  2.16 95.985 213.84 96.255 ;
     RECT  2.16 96.525 213.84 96.795 ;
     RECT  2.16 97.065 213.84 97.335 ;
     RECT  2.16 97.605 213.84 97.875 ;
     RECT  2.16 98.145 213.84 98.415 ;
     RECT  2.16 98.685 213.84 98.955 ;
     RECT  2.16 99.225 213.84 99.495 ;
     RECT  2.16 99.765 213.84 100.035 ;
     RECT  2.16 100.305 213.84 100.575 ;
     RECT  2.16 100.845 213.84 101.115 ;
     RECT  2.16 101.385 213.84 101.655 ;
     RECT  2.16 101.925 213.84 102.195 ;
     RECT  2.16 102.465 213.84 102.735 ;
     RECT  2.16 103.005 213.84 103.275 ;
     RECT  2.16 103.545 213.84 103.815 ;
     RECT  2.16 104.085 213.84 104.355 ;
     RECT  2.16 104.625 213.84 104.895 ;
     RECT  2.16 105.165 213.84 105.435 ;
     RECT  2.16 105.705 213.84 105.975 ;
     RECT  2.16 106.245 213.84 106.515 ;
     RECT  2.16 106.785 213.84 107.055 ;
     RECT  2.16 107.325 213.84 107.595 ;
     RECT  2.16 107.865 213.84 108.135 ;
     RECT  2.16 108.405 213.84 108.675 ;
     RECT  2.16 108.945 213.84 109.215 ;
     RECT  2.16 109.485 213.84 109.755 ;
     RECT  2.16 110.025 213.84 110.295 ;
     RECT  2.16 110.565 213.84 110.835 ;
     RECT  2.16 111.105 213.84 111.375 ;
     RECT  2.16 111.645 213.84 111.915 ;
     RECT  2.16 112.185 213.84 112.455 ;
     RECT  2.16 112.725 213.84 112.995 ;
     RECT  2.16 113.265 213.84 113.535 ;
     RECT  2.16 113.805 213.84 114.075 ;
     RECT  2.16 114.345 213.84 114.615 ;
     RECT  2.16 114.885 213.84 115.155 ;
     RECT  2.16 115.425 213.84 115.695 ;
     RECT  2.16 115.965 213.84 116.235 ;
     RECT  2.16 116.505 213.84 116.775 ;
     RECT  2.16 117.045 213.84 117.315 ;
     RECT  2.16 117.585 213.84 117.855 ;
     RECT  2.16 118.125 213.84 118.395 ;
     RECT  2.16 118.665 213.84 118.935 ;
     RECT  2.16 119.205 213.84 119.475 ;
     RECT  2.16 119.745 213.84 120.015 ;
     RECT  2.16 120.285 213.84 120.555 ;
     RECT  2.16 120.825 213.84 121.095 ;
     RECT  2.16 121.365 213.84 121.635 ;
     RECT  2.16 121.905 213.84 122.175 ;
     RECT  2.16 122.445 213.84 122.715 ;
     RECT  2.16 122.985 213.84 123.255 ;
     RECT  2.16 123.525 213.84 123.795 ;
     RECT  2.16 124.065 213.84 124.335 ;
     RECT  2.16 124.605 213.84 124.875 ;
     RECT  2.16 125.145 213.84 125.415 ;
     RECT  2.16 125.685 213.84 125.955 ;
     RECT  2.16 126.225 213.84 126.495 ;
     RECT  2.16 126.765 213.84 127.035 ;
     RECT  2.16 127.305 213.84 127.575 ;
     RECT  2.16 127.845 213.84 128.115 ;
     RECT  2.16 128.385 213.84 128.655 ;
     RECT  2.16 128.925 213.84 129.195 ;
     RECT  2.16 129.465 213.84 129.735 ;
     RECT  2.16 130.005 213.84 130.275 ;
     RECT  2.16 130.545 213.84 130.815 ;
     RECT  2.16 131.085 213.84 131.355 ;
     RECT  2.16 131.625 213.84 131.895 ;
     RECT  2.16 132.165 213.84 132.435 ;
     RECT  2.16 132.705 213.84 132.975 ;
     RECT  2.16 133.245 213.84 133.515 ;
     RECT  2.16 133.785 213.84 134.055 ;
     RECT  2.16 134.325 213.84 134.595 ;
     RECT  2.16 134.865 213.84 135.135 ;
     RECT  2.16 135.405 213.84 135.675 ;
     RECT  2.16 135.945 213.84 136.215 ;
     RECT  2.16 136.485 213.84 136.755 ;
     RECT  2.16 137.025 213.84 137.295 ;
     RECT  2.16 137.565 213.84 137.835 ;
     RECT  2.16 138.105 213.84 138.375 ;
     RECT  2.16 138.645 213.84 138.915 ;
     RECT  2.16 139.185 213.84 139.455 ;
     RECT  2.16 139.725 213.84 139.995 ;
     RECT  2.16 140.265 213.84 140.535 ;
     RECT  2.16 140.805 213.84 141.075 ;
     RECT  2.16 141.345 213.84 141.615 ;
     RECT  2.16 141.885 213.84 142.155 ;
     RECT  2.16 142.425 213.84 142.695 ;
     RECT  2.16 142.965 213.84 143.235 ;
     RECT  2.16 143.505 213.84 143.775 ;
     RECT  2.16 144.045 213.84 144.315 ;
     RECT  2.16 144.585 213.84 144.855 ;
     RECT  2.16 145.125 213.84 145.395 ;
     RECT  2.16 145.665 213.84 145.935 ;
     RECT  2.16 146.205 213.84 146.475 ;
     RECT  2.16 146.745 213.84 147.015 ;
     RECT  2.16 147.285 213.84 147.555 ;
     RECT  2.16 147.825 213.84 148.095 ;
     RECT  2.16 148.365 213.84 148.635 ;
     RECT  2.16 148.905 213.84 149.175 ;
     RECT  2.16 149.445 213.84 149.715 ;
     RECT  2.16 149.985 213.84 150.255 ;
     RECT  2.16 150.525 213.84 150.795 ;
     RECT  2.16 151.065 213.84 151.335 ;
     RECT  2.16 151.605 213.84 151.875 ;
     RECT  2.16 152.145 213.84 152.415 ;
     RECT  2.16 152.685 213.84 152.955 ;
     RECT  2.16 153.225 213.84 153.495 ;
     RECT  2.16 153.765 213.84 154.035 ;
     RECT  2.16 154.305 213.84 154.575 ;
     RECT  2.16 154.845 213.84 155.115 ;
     RECT  2.16 155.385 213.84 155.655 ;
     RECT  2.16 155.925 213.84 156.195 ;
     RECT  2.16 156.465 213.84 156.735 ;
     RECT  2.16 157.005 213.84 157.275 ;
     RECT  2.16 157.545 213.84 157.815 ;
     RECT  2.16 158.085 213.84 158.355 ;
     RECT  2.16 158.625 213.84 158.895 ;
     RECT  2.16 159.165 213.84 159.435 ;
     RECT  2.16 159.705 213.84 159.975 ;
     RECT  2.16 160.245 213.84 160.515 ;
     RECT  2.16 160.785 213.84 161.055 ;
     RECT  2.16 161.325 213.84 161.595 ;
     RECT  2.16 161.865 213.84 162.135 ;
     RECT  2.16 162.405 213.84 162.675 ;
     RECT  2.16 162.945 213.84 163.215 ;
     RECT  2.16 163.485 213.84 163.755 ;
     RECT  2.16 164.025 213.84 164.295 ;
     RECT  2.16 164.565 213.84 164.835 ;
     RECT  2.16 165.105 213.84 165.375 ;
     RECT  2.16 165.645 213.84 165.915 ;
     RECT  2.16 166.185 213.84 166.455 ;
     RECT  2.16 166.725 213.84 166.995 ;
     RECT  2.16 167.265 213.84 167.535 ;
     RECT  2.16 167.805 213.84 168.075 ;
     RECT  2.16 168.345 213.84 168.615 ;
     RECT  2.16 168.885 213.84 169.155 ;
     RECT  2.16 169.425 213.84 169.695 ;
     RECT  2.16 169.965 213.84 170.235 ;
     RECT  2.16 170.505 213.84 170.775 ;
     RECT  2.16 171.045 213.84 171.315 ;
     RECT  2.16 171.585 213.84 171.855 ;
     RECT  2.16 172.125 213.84 172.395 ;
     RECT  2.16 172.665 213.84 172.935 ;
     RECT  2.16 173.205 213.84 173.475 ;
     RECT  2.16 173.745 213.84 174.015 ;
     RECT  2.16 174.285 213.84 174.555 ;
     RECT  2.16 174.825 213.84 175.095 ;
     RECT  2.16 175.365 213.84 175.635 ;
     RECT  2.16 175.905 213.84 176.175 ;
     RECT  2.16 176.445 213.84 176.715 ;
     RECT  2.16 176.985 213.84 177.255 ;
     RECT  2.16 177.525 213.84 177.795 ;
     RECT  2.16 178.065 213.84 178.335 ;
     RECT  2.16 178.605 213.84 178.875 ;
     RECT  2.16 179.145 213.84 179.415 ;
     RECT  2.16 179.685 213.84 179.955 ;
     RECT  2.16 180.225 213.84 180.495 ;
     RECT  2.16 180.765 213.84 181.035 ;
     RECT  2.16 181.305 213.84 181.575 ;
     RECT  2.16 181.845 213.84 182.115 ;
     RECT  2.16 182.385 213.84 182.655 ;
     RECT  2.16 182.925 213.84 183.195 ;
     RECT  2.16 183.465 213.84 183.735 ;
     RECT  2.16 184.005 213.84 184.275 ;
     RECT  2.16 184.545 213.84 184.815 ;
     RECT  2.16 185.085 213.84 185.355 ;
     RECT  2.16 185.625 213.84 185.895 ;
     RECT  2.16 186.165 213.84 186.435 ;
     RECT  2.16 186.705 213.84 186.975 ;
     RECT  2.16 187.245 213.84 187.515 ;
     RECT  2.16 187.785 213.84 188.055 ;
     RECT  2.16 188.325 213.84 188.595 ;
     RECT  2.16 188.865 213.84 189.135 ;
     RECT  2.16 189.405 213.84 189.675 ;
     RECT  2.16 189.945 213.84 190.215 ;
     RECT  2.16 190.485 213.84 190.755 ;
     RECT  2.16 191.025 213.84 191.295 ;
     RECT  2.16 191.565 213.84 191.835 ;
     RECT  2.16 192.105 213.84 192.375 ;
     RECT  2.16 192.645 213.84 192.915 ;
     RECT  2.16 193.185 213.84 193.455 ;
     RECT  2.16 193.725 213.84 193.995 ;
     RECT  2.16 194.265 213.84 194.535 ;
     RECT  2.16 194.805 213.84 195.075 ;
     RECT  2.16 195.345 213.84 195.615 ;
     RECT  2.16 195.885 213.84 196.155 ;
     RECT  2.16 196.425 213.84 196.695 ;
     RECT  2.16 196.965 213.84 197.235 ;
     RECT  2.16 197.505 213.84 197.775 ;
     RECT  2.16 198.045 213.84 198.315 ;
     RECT  2.16 198.585 213.84 198.855 ;
     RECT  2.16 199.125 213.84 199.395 ;
     RECT  2.16 199.665 213.84 199.935 ;
     RECT  2.16 200.205 213.84 200.475 ;
     RECT  2.16 200.745 213.84 201.015 ;
     RECT  2.16 201.285 213.84 201.555 ;
     RECT  2.16 201.825 213.84 202.095 ;
     RECT  2.16 202.365 213.84 202.635 ;
     RECT  2.16 202.905 213.84 203.175 ;
     RECT  2.16 203.445 213.84 203.715 ;
     RECT  2.16 203.985 213.84 204.255 ;
     RECT  2.16 204.525 213.84 204.795 ;
     RECT  2.16 205.065 213.84 205.335 ;
     RECT  2.16 205.605 213.84 205.875 ;
     RECT  2.16 206.145 213.84 206.415 ;
     RECT  2.16 206.685 213.84 206.955 ;
     RECT  2.16 207.225 213.84 207.495 ;
     RECT  2.16 207.765 213.84 208.035 ;
     RECT  2.16 208.305 213.84 208.575 ;
     RECT  2.16 208.845 213.84 209.115 ;
     RECT  2.16 209.385 213.84 209.655 ;
     RECT  2.16 209.925 213.84 210.195 ;
     RECT  2.16 210.465 213.84 210.735 ;
     RECT  2.16 211.005 213.84 211.275 ;
     RECT  2.16 211.545 213.84 211.815 ;
     RECT  2.16 212.085 213.84 212.355 ;
     RECT  2.16 212.625 213.84 212.895 ;
     RECT  2.16 213.165 213.84 213.435 ;
     RECT  2.16 213.705 213.84 213.84 ;
    LAYER RVTP ;
     RECT  2.16 2.295 213.84 2.565 ;
     RECT  2.16 2.835 213.84 3.105 ;
     RECT  2.16 3.375 213.84 3.645 ;
     RECT  2.16 3.915 213.84 4.185 ;
     RECT  2.16 4.455 213.84 4.725 ;
     RECT  2.16 4.995 213.84 5.265 ;
     RECT  2.16 5.535 213.84 5.805 ;
     RECT  2.16 6.075 213.84 6.345 ;
     RECT  2.16 6.615 213.84 6.885 ;
     RECT  2.16 7.155 213.84 7.425 ;
     RECT  2.16 7.695 213.84 7.965 ;
     RECT  2.16 8.235 213.84 8.505 ;
     RECT  2.16 8.775 213.84 9.045 ;
     RECT  2.16 9.315 213.84 9.585 ;
     RECT  2.16 9.855 213.84 10.125 ;
     RECT  2.16 10.395 213.84 10.665 ;
     RECT  2.16 10.935 213.84 11.205 ;
     RECT  2.16 11.475 213.84 11.745 ;
     RECT  2.16 12.015 213.84 12.285 ;
     RECT  2.16 12.555 213.84 12.825 ;
     RECT  2.16 13.095 213.84 13.365 ;
     RECT  2.16 13.635 213.84 13.905 ;
     RECT  2.16 14.175 213.84 14.445 ;
     RECT  2.16 14.715 213.84 14.985 ;
     RECT  2.16 15.255 213.84 15.525 ;
     RECT  2.16 15.795 213.84 16.065 ;
     RECT  2.16 16.335 213.84 16.605 ;
     RECT  2.16 16.875 213.84 17.145 ;
     RECT  2.16 17.415 213.84 17.685 ;
     RECT  2.16 17.955 213.84 18.225 ;
     RECT  2.16 18.495 213.84 18.765 ;
     RECT  2.16 19.035 213.84 19.305 ;
     RECT  2.16 19.575 213.84 19.845 ;
     RECT  2.16 20.115 213.84 20.385 ;
     RECT  2.16 20.655 213.84 20.925 ;
     RECT  2.16 21.195 213.84 21.465 ;
     RECT  2.16 21.735 213.84 22.005 ;
     RECT  2.16 22.275 213.84 22.545 ;
     RECT  2.16 22.815 213.84 23.085 ;
     RECT  2.16 23.355 213.84 23.625 ;
     RECT  2.16 23.895 213.84 24.165 ;
     RECT  2.16 24.435 213.84 24.705 ;
     RECT  2.16 24.975 213.84 25.245 ;
     RECT  2.16 25.515 213.84 25.785 ;
     RECT  2.16 26.055 213.84 26.325 ;
     RECT  2.16 26.595 213.84 26.865 ;
     RECT  2.16 27.135 213.84 27.405 ;
     RECT  2.16 27.675 213.84 27.945 ;
     RECT  2.16 28.215 213.84 28.485 ;
     RECT  2.16 28.755 213.84 29.025 ;
     RECT  2.16 29.295 213.84 29.565 ;
     RECT  2.16 29.835 213.84 30.105 ;
     RECT  2.16 30.375 213.84 30.645 ;
     RECT  2.16 30.915 213.84 31.185 ;
     RECT  2.16 31.455 213.84 31.725 ;
     RECT  2.16 31.995 213.84 32.265 ;
     RECT  2.16 32.535 213.84 32.805 ;
     RECT  2.16 33.075 213.84 33.345 ;
     RECT  2.16 33.615 213.84 33.885 ;
     RECT  2.16 34.155 213.84 34.425 ;
     RECT  2.16 34.695 213.84 34.965 ;
     RECT  2.16 35.235 213.84 35.505 ;
     RECT  2.16 35.775 213.84 36.045 ;
     RECT  2.16 36.315 213.84 36.585 ;
     RECT  2.16 36.855 213.84 37.125 ;
     RECT  2.16 37.395 213.84 37.665 ;
     RECT  2.16 37.935 213.84 38.205 ;
     RECT  2.16 38.475 213.84 38.745 ;
     RECT  2.16 39.015 213.84 39.285 ;
     RECT  2.16 39.555 213.84 39.825 ;
     RECT  2.16 40.095 213.84 40.365 ;
     RECT  2.16 40.635 213.84 40.905 ;
     RECT  2.16 41.175 213.84 41.445 ;
     RECT  2.16 41.715 213.84 41.985 ;
     RECT  2.16 42.255 213.84 42.525 ;
     RECT  2.16 42.795 213.84 43.065 ;
     RECT  2.16 43.335 213.84 43.605 ;
     RECT  2.16 43.875 213.84 44.145 ;
     RECT  2.16 44.415 213.84 44.685 ;
     RECT  2.16 44.955 213.84 45.225 ;
     RECT  2.16 45.495 213.84 45.765 ;
     RECT  2.16 46.035 213.84 46.305 ;
     RECT  2.16 46.575 213.84 46.845 ;
     RECT  2.16 47.115 213.84 47.385 ;
     RECT  2.16 47.655 213.84 47.925 ;
     RECT  2.16 48.195 213.84 48.465 ;
     RECT  2.16 48.735 213.84 49.005 ;
     RECT  2.16 49.275 213.84 49.545 ;
     RECT  2.16 49.815 213.84 50.085 ;
     RECT  2.16 50.355 213.84 50.625 ;
     RECT  2.16 50.895 213.84 51.165 ;
     RECT  2.16 51.435 213.84 51.705 ;
     RECT  2.16 51.975 213.84 52.245 ;
     RECT  2.16 52.515 213.84 52.785 ;
     RECT  2.16 53.055 213.84 53.325 ;
     RECT  2.16 53.595 213.84 53.865 ;
     RECT  2.16 54.135 213.84 54.405 ;
     RECT  2.16 54.675 213.84 54.945 ;
     RECT  2.16 55.215 213.84 55.485 ;
     RECT  2.16 55.755 213.84 56.025 ;
     RECT  2.16 56.295 213.84 56.565 ;
     RECT  2.16 56.835 213.84 57.105 ;
     RECT  2.16 57.375 213.84 57.645 ;
     RECT  2.16 57.915 213.84 58.185 ;
     RECT  2.16 58.455 213.84 58.725 ;
     RECT  2.16 58.995 213.84 59.265 ;
     RECT  2.16 59.535 213.84 59.805 ;
     RECT  2.16 60.075 213.84 60.345 ;
     RECT  2.16 60.615 213.84 60.885 ;
     RECT  2.16 61.155 213.84 61.425 ;
     RECT  2.16 61.695 213.84 61.965 ;
     RECT  2.16 62.235 213.84 62.505 ;
     RECT  2.16 62.775 213.84 63.045 ;
     RECT  2.16 63.315 213.84 63.585 ;
     RECT  2.16 63.855 213.84 64.125 ;
     RECT  2.16 64.395 213.84 64.665 ;
     RECT  2.16 64.935 213.84 65.205 ;
     RECT  2.16 65.475 213.84 65.745 ;
     RECT  2.16 66.015 213.84 66.285 ;
     RECT  2.16 66.555 213.84 66.825 ;
     RECT  2.16 67.095 213.84 67.365 ;
     RECT  2.16 67.635 213.84 67.905 ;
     RECT  2.16 68.175 213.84 68.445 ;
     RECT  2.16 68.715 213.84 68.985 ;
     RECT  2.16 69.255 213.84 69.525 ;
     RECT  2.16 69.795 213.84 70.065 ;
     RECT  2.16 70.335 213.84 70.605 ;
     RECT  2.16 70.875 213.84 71.145 ;
     RECT  2.16 71.415 213.84 71.685 ;
     RECT  2.16 71.955 213.84 72.225 ;
     RECT  2.16 72.495 213.84 72.765 ;
     RECT  2.16 73.035 213.84 73.305 ;
     RECT  2.16 73.575 213.84 73.845 ;
     RECT  2.16 74.115 213.84 74.385 ;
     RECT  2.16 74.655 213.84 74.925 ;
     RECT  2.16 75.195 213.84 75.465 ;
     RECT  2.16 75.735 213.84 76.005 ;
     RECT  2.16 76.275 213.84 76.545 ;
     RECT  2.16 76.815 213.84 77.085 ;
     RECT  2.16 77.355 213.84 77.625 ;
     RECT  2.16 77.895 213.84 78.165 ;
     RECT  2.16 78.435 213.84 78.705 ;
     RECT  2.16 78.975 213.84 79.245 ;
     RECT  2.16 79.515 213.84 79.785 ;
     RECT  2.16 80.055 213.84 80.325 ;
     RECT  2.16 80.595 213.84 80.865 ;
     RECT  2.16 81.135 213.84 81.405 ;
     RECT  2.16 81.675 213.84 81.945 ;
     RECT  2.16 82.215 213.84 82.485 ;
     RECT  2.16 82.755 213.84 83.025 ;
     RECT  2.16 83.295 213.84 83.565 ;
     RECT  2.16 83.835 213.84 84.105 ;
     RECT  2.16 84.375 213.84 84.645 ;
     RECT  2.16 84.915 213.84 85.185 ;
     RECT  2.16 85.455 213.84 85.725 ;
     RECT  2.16 85.995 213.84 86.265 ;
     RECT  2.16 86.535 213.84 86.805 ;
     RECT  2.16 87.075 213.84 87.345 ;
     RECT  2.16 87.615 213.84 87.885 ;
     RECT  2.16 88.155 213.84 88.425 ;
     RECT  2.16 88.695 213.84 88.965 ;
     RECT  2.16 89.235 213.84 89.505 ;
     RECT  2.16 89.775 213.84 90.045 ;
     RECT  2.16 90.315 213.84 90.585 ;
     RECT  2.16 90.855 213.84 91.125 ;
     RECT  2.16 91.395 213.84 91.665 ;
     RECT  2.16 91.935 213.84 92.205 ;
     RECT  2.16 92.475 213.84 92.745 ;
     RECT  2.16 93.015 213.84 93.285 ;
     RECT  2.16 93.555 213.84 93.825 ;
     RECT  2.16 94.095 213.84 94.365 ;
     RECT  2.16 94.635 213.84 94.905 ;
     RECT  2.16 95.175 213.84 95.445 ;
     RECT  2.16 95.715 213.84 95.985 ;
     RECT  2.16 96.255 213.84 96.525 ;
     RECT  2.16 96.795 213.84 97.065 ;
     RECT  2.16 97.335 213.84 97.605 ;
     RECT  2.16 97.875 213.84 98.145 ;
     RECT  2.16 98.415 213.84 98.685 ;
     RECT  2.16 98.955 213.84 99.225 ;
     RECT  2.16 99.495 213.84 99.765 ;
     RECT  2.16 100.035 213.84 100.305 ;
     RECT  2.16 100.575 213.84 100.845 ;
     RECT  2.16 101.115 213.84 101.385 ;
     RECT  2.16 101.655 213.84 101.925 ;
     RECT  2.16 102.195 213.84 102.465 ;
     RECT  2.16 102.735 213.84 103.005 ;
     RECT  2.16 103.275 213.84 103.545 ;
     RECT  2.16 103.815 213.84 104.085 ;
     RECT  2.16 104.355 213.84 104.625 ;
     RECT  2.16 104.895 213.84 105.165 ;
     RECT  2.16 105.435 213.84 105.705 ;
     RECT  2.16 105.975 213.84 106.245 ;
     RECT  2.16 106.515 213.84 106.785 ;
     RECT  2.16 107.055 213.84 107.325 ;
     RECT  2.16 107.595 213.84 107.865 ;
     RECT  2.16 108.135 213.84 108.405 ;
     RECT  2.16 108.675 213.84 108.945 ;
     RECT  2.16 109.215 213.84 109.485 ;
     RECT  2.16 109.755 213.84 110.025 ;
     RECT  2.16 110.295 213.84 110.565 ;
     RECT  2.16 110.835 213.84 111.105 ;
     RECT  2.16 111.375 213.84 111.645 ;
     RECT  2.16 111.915 213.84 112.185 ;
     RECT  2.16 112.455 213.84 112.725 ;
     RECT  2.16 112.995 213.84 113.265 ;
     RECT  2.16 113.535 213.84 113.805 ;
     RECT  2.16 114.075 213.84 114.345 ;
     RECT  2.16 114.615 213.84 114.885 ;
     RECT  2.16 115.155 213.84 115.425 ;
     RECT  2.16 115.695 213.84 115.965 ;
     RECT  2.16 116.235 213.84 116.505 ;
     RECT  2.16 116.775 213.84 117.045 ;
     RECT  2.16 117.315 213.84 117.585 ;
     RECT  2.16 117.855 213.84 118.125 ;
     RECT  2.16 118.395 213.84 118.665 ;
     RECT  2.16 118.935 213.84 119.205 ;
     RECT  2.16 119.475 213.84 119.745 ;
     RECT  2.16 120.015 213.84 120.285 ;
     RECT  2.16 120.555 213.84 120.825 ;
     RECT  2.16 121.095 213.84 121.365 ;
     RECT  2.16 121.635 213.84 121.905 ;
     RECT  2.16 122.175 213.84 122.445 ;
     RECT  2.16 122.715 213.84 122.985 ;
     RECT  2.16 123.255 213.84 123.525 ;
     RECT  2.16 123.795 213.84 124.065 ;
     RECT  2.16 124.335 213.84 124.605 ;
     RECT  2.16 124.875 213.84 125.145 ;
     RECT  2.16 125.415 213.84 125.685 ;
     RECT  2.16 125.955 213.84 126.225 ;
     RECT  2.16 126.495 213.84 126.765 ;
     RECT  2.16 127.035 213.84 127.305 ;
     RECT  2.16 127.575 213.84 127.845 ;
     RECT  2.16 128.115 213.84 128.385 ;
     RECT  2.16 128.655 213.84 128.925 ;
     RECT  2.16 129.195 213.84 129.465 ;
     RECT  2.16 129.735 213.84 130.005 ;
     RECT  2.16 130.275 213.84 130.545 ;
     RECT  2.16 130.815 213.84 131.085 ;
     RECT  2.16 131.355 213.84 131.625 ;
     RECT  2.16 131.895 213.84 132.165 ;
     RECT  2.16 132.435 213.84 132.705 ;
     RECT  2.16 132.975 213.84 133.245 ;
     RECT  2.16 133.515 213.84 133.785 ;
     RECT  2.16 134.055 213.84 134.325 ;
     RECT  2.16 134.595 213.84 134.865 ;
     RECT  2.16 135.135 213.84 135.405 ;
     RECT  2.16 135.675 213.84 135.945 ;
     RECT  2.16 136.215 213.84 136.485 ;
     RECT  2.16 136.755 213.84 137.025 ;
     RECT  2.16 137.295 213.84 137.565 ;
     RECT  2.16 137.835 213.84 138.105 ;
     RECT  2.16 138.375 213.84 138.645 ;
     RECT  2.16 138.915 213.84 139.185 ;
     RECT  2.16 139.455 213.84 139.725 ;
     RECT  2.16 139.995 213.84 140.265 ;
     RECT  2.16 140.535 213.84 140.805 ;
     RECT  2.16 141.075 213.84 141.345 ;
     RECT  2.16 141.615 213.84 141.885 ;
     RECT  2.16 142.155 213.84 142.425 ;
     RECT  2.16 142.695 213.84 142.965 ;
     RECT  2.16 143.235 213.84 143.505 ;
     RECT  2.16 143.775 213.84 144.045 ;
     RECT  2.16 144.315 213.84 144.585 ;
     RECT  2.16 144.855 213.84 145.125 ;
     RECT  2.16 145.395 213.84 145.665 ;
     RECT  2.16 145.935 213.84 146.205 ;
     RECT  2.16 146.475 213.84 146.745 ;
     RECT  2.16 147.015 213.84 147.285 ;
     RECT  2.16 147.555 213.84 147.825 ;
     RECT  2.16 148.095 213.84 148.365 ;
     RECT  2.16 148.635 213.84 148.905 ;
     RECT  2.16 149.175 213.84 149.445 ;
     RECT  2.16 149.715 213.84 149.985 ;
     RECT  2.16 150.255 213.84 150.525 ;
     RECT  2.16 150.795 213.84 151.065 ;
     RECT  2.16 151.335 213.84 151.605 ;
     RECT  2.16 151.875 213.84 152.145 ;
     RECT  2.16 152.415 213.84 152.685 ;
     RECT  2.16 152.955 213.84 153.225 ;
     RECT  2.16 153.495 213.84 153.765 ;
     RECT  2.16 154.035 213.84 154.305 ;
     RECT  2.16 154.575 213.84 154.845 ;
     RECT  2.16 155.115 213.84 155.385 ;
     RECT  2.16 155.655 213.84 155.925 ;
     RECT  2.16 156.195 213.84 156.465 ;
     RECT  2.16 156.735 213.84 157.005 ;
     RECT  2.16 157.275 213.84 157.545 ;
     RECT  2.16 157.815 213.84 158.085 ;
     RECT  2.16 158.355 213.84 158.625 ;
     RECT  2.16 158.895 213.84 159.165 ;
     RECT  2.16 159.435 213.84 159.705 ;
     RECT  2.16 159.975 213.84 160.245 ;
     RECT  2.16 160.515 213.84 160.785 ;
     RECT  2.16 161.055 213.84 161.325 ;
     RECT  2.16 161.595 213.84 161.865 ;
     RECT  2.16 162.135 213.84 162.405 ;
     RECT  2.16 162.675 213.84 162.945 ;
     RECT  2.16 163.215 213.84 163.485 ;
     RECT  2.16 163.755 213.84 164.025 ;
     RECT  2.16 164.295 213.84 164.565 ;
     RECT  2.16 164.835 213.84 165.105 ;
     RECT  2.16 165.375 213.84 165.645 ;
     RECT  2.16 165.915 213.84 166.185 ;
     RECT  2.16 166.455 213.84 166.725 ;
     RECT  2.16 166.995 213.84 167.265 ;
     RECT  2.16 167.535 213.84 167.805 ;
     RECT  2.16 168.075 213.84 168.345 ;
     RECT  2.16 168.615 213.84 168.885 ;
     RECT  2.16 169.155 213.84 169.425 ;
     RECT  2.16 169.695 213.84 169.965 ;
     RECT  2.16 170.235 213.84 170.505 ;
     RECT  2.16 170.775 213.84 171.045 ;
     RECT  2.16 171.315 213.84 171.585 ;
     RECT  2.16 171.855 213.84 172.125 ;
     RECT  2.16 172.395 213.84 172.665 ;
     RECT  2.16 172.935 213.84 173.205 ;
     RECT  2.16 173.475 213.84 173.745 ;
     RECT  2.16 174.015 213.84 174.285 ;
     RECT  2.16 174.555 213.84 174.825 ;
     RECT  2.16 175.095 213.84 175.365 ;
     RECT  2.16 175.635 213.84 175.905 ;
     RECT  2.16 176.175 213.84 176.445 ;
     RECT  2.16 176.715 213.84 176.985 ;
     RECT  2.16 177.255 213.84 177.525 ;
     RECT  2.16 177.795 213.84 178.065 ;
     RECT  2.16 178.335 213.84 178.605 ;
     RECT  2.16 178.875 213.84 179.145 ;
     RECT  2.16 179.415 213.84 179.685 ;
     RECT  2.16 179.955 213.84 180.225 ;
     RECT  2.16 180.495 213.84 180.765 ;
     RECT  2.16 181.035 213.84 181.305 ;
     RECT  2.16 181.575 213.84 181.845 ;
     RECT  2.16 182.115 213.84 182.385 ;
     RECT  2.16 182.655 213.84 182.925 ;
     RECT  2.16 183.195 213.84 183.465 ;
     RECT  2.16 183.735 213.84 184.005 ;
     RECT  2.16 184.275 213.84 184.545 ;
     RECT  2.16 184.815 213.84 185.085 ;
     RECT  2.16 185.355 213.84 185.625 ;
     RECT  2.16 185.895 213.84 186.165 ;
     RECT  2.16 186.435 213.84 186.705 ;
     RECT  2.16 186.975 213.84 187.245 ;
     RECT  2.16 187.515 213.84 187.785 ;
     RECT  2.16 188.055 213.84 188.325 ;
     RECT  2.16 188.595 213.84 188.865 ;
     RECT  2.16 189.135 213.84 189.405 ;
     RECT  2.16 189.675 213.84 189.945 ;
     RECT  2.16 190.215 213.84 190.485 ;
     RECT  2.16 190.755 213.84 191.025 ;
     RECT  2.16 191.295 213.84 191.565 ;
     RECT  2.16 191.835 213.84 192.105 ;
     RECT  2.16 192.375 213.84 192.645 ;
     RECT  2.16 192.915 213.84 193.185 ;
     RECT  2.16 193.455 213.84 193.725 ;
     RECT  2.16 193.995 213.84 194.265 ;
     RECT  2.16 194.535 213.84 194.805 ;
     RECT  2.16 195.075 213.84 195.345 ;
     RECT  2.16 195.615 213.84 195.885 ;
     RECT  2.16 196.155 213.84 196.425 ;
     RECT  2.16 196.695 213.84 196.965 ;
     RECT  2.16 197.235 213.84 197.505 ;
     RECT  2.16 197.775 213.84 198.045 ;
     RECT  2.16 198.315 213.84 198.585 ;
     RECT  2.16 198.855 213.84 199.125 ;
     RECT  2.16 199.395 213.84 199.665 ;
     RECT  2.16 199.935 213.84 200.205 ;
     RECT  2.16 200.475 213.84 200.745 ;
     RECT  2.16 201.015 213.84 201.285 ;
     RECT  2.16 201.555 213.84 201.825 ;
     RECT  2.16 202.095 213.84 202.365 ;
     RECT  2.16 202.635 213.84 202.905 ;
     RECT  2.16 203.175 213.84 203.445 ;
     RECT  2.16 203.715 213.84 203.985 ;
     RECT  2.16 204.255 213.84 204.525 ;
     RECT  2.16 204.795 213.84 205.065 ;
     RECT  2.16 205.335 213.84 205.605 ;
     RECT  2.16 205.875 213.84 206.145 ;
     RECT  2.16 206.415 213.84 206.685 ;
     RECT  2.16 206.955 213.84 207.225 ;
     RECT  2.16 207.495 213.84 207.765 ;
     RECT  2.16 208.035 213.84 208.305 ;
     RECT  2.16 208.575 213.84 208.845 ;
     RECT  2.16 209.115 213.84 209.385 ;
     RECT  2.16 209.655 213.84 209.925 ;
     RECT  2.16 210.195 213.84 210.465 ;
     RECT  2.16 210.735 213.84 211.005 ;
     RECT  2.16 211.275 213.84 211.545 ;
     RECT  2.16 211.815 213.84 212.085 ;
     RECT  2.16 212.355 213.84 212.625 ;
     RECT  2.16 212.895 213.84 213.165 ;
     RECT  2.16 213.435 213.84 213.705 ;
    LAYER M1 ;
     RECT  2.16 2.151 213.84 213.849 ;
    LAYER M2 ;
     RECT  0.031 114.552 0.131 114.984 ;
     RECT  0.103 107.1 0.463 107.118 ;
     RECT  0.463 107.1 0.499 107.424 ;
     RECT  0.463 109.224 0.499 109.242 ;
     RECT  0.463 103.014 0.535 103.032 ;
     RECT  0.499 107.1 0.535 107.658 ;
     RECT  0.499 109.188 0.535 109.242 ;
     RECT  1.147 113.508 1.723 113.526 ;
     RECT  0.535 103.014 2.16 103.068 ;
     RECT  0.535 104.292 2.16 104.31 ;
     RECT  0.535 106.452 2.16 108.198 ;
     RECT  0.535 109.188 2.16 109.674 ;
     RECT  1.723 113.508 2.16 114.174 ;
     RECT  0.131 114.966 2.16 114.984 ;
     RECT  2.16 2.151 92.263 213.849 ;
     RECT  92.263 2.034 92.911 213.849 ;
     RECT  92.911 1.998 98.771 213.849 ;
     RECT  98.771 2.106 99.383 213.849 ;
     RECT  99.383 2.151 102.199 213.849 ;
     RECT  102.199 2.106 103.559 213.849 ;
     RECT  103.559 2.151 108.931 213.849 ;
     RECT  108.931 1.926 112.955 213.849 ;
     RECT  112.955 1.998 114.727 213.849 ;
     RECT  116.491 1.152 116.591 1.17 ;
     RECT  114.727 1.962 117.995 213.849 ;
     RECT  117.995 1.998 118.643 213.849 ;
     RECT  118.643 2.07 118.967 213.849 ;
     RECT  118.867 0.072 119.551 0.09 ;
     RECT  119.551 0.036 120.415 0.09 ;
     RECT  120.415 0.036 120.703 0.126 ;
     RECT  120.703 0.036 122.611 0.162 ;
     RECT  122.611 0.036 124.223 0.549 ;
     RECT  118.967 2.106 124.871 213.849 ;
     RECT  124.223 0.036 125.627 0.054 ;
     RECT  124.871 2.151 213.84 213.849 ;
    LAYER M3 ;
     RECT  119.556 0.031 119.574 0.067 ;
     RECT  118.872 0.067 119.574 0.091 ;
     RECT  123.696 0.067 123.714 0.103 ;
     RECT  118.872 0.091 120.726 0.125 ;
     RECT  94.176 0.091 94.194 0.139 ;
     RECT  117.54 0.091 117.558 0.139 ;
     RECT  122.868 0.091 122.886 0.139 ;
     RECT  123.696 0.103 123.966 0.139 ;
     RECT  120.276 0.125 120.726 0.167 ;
     RECT  94.104 0.139 94.194 0.187 ;
     RECT  104.796 0.091 104.814 0.187 ;
     RECT  109.044 0.091 109.278 0.187 ;
     RECT  122.868 0.139 123.966 0.187 ;
     RECT  103.176 0.091 103.194 0.221 ;
     RECT  108.972 0.187 109.278 0.221 ;
     RECT  113.292 0.091 113.31 0.221 ;
     RECT  97.056 0.139 97.074 0.269 ;
     RECT  110.88 0.091 110.898 0.269 ;
     RECT  99.756 0.091 99.774 0.317 ;
     RECT  104.796 0.187 105.534 0.317 ;
     RECT  108.972 0.221 109.206 0.317 ;
     RECT  108.972 0.317 108.99 0.461 ;
     RECT  122.004 0.091 122.022 0.52 ;
     RECT  122.796 0.187 123.966 0.52 ;
     RECT  94.104 0.187 94.374 0.523 ;
     RECT  122.004 0.52 123.966 0.526 ;
     RECT  92.556 0.523 92.574 0.571 ;
     RECT  93.348 0.523 93.366 0.571 ;
     RECT  117.324 0.139 117.558 0.571 ;
     RECT  122.004 0.526 124.218 0.571 ;
     RECT  125.604 0.031 125.622 0.571 ;
     RECT  122.004 0.571 125.622 0.605 ;
     RECT  122.004 0.605 122.562 0.701 ;
     RECT  116.496 0.523 116.514 1.147 ;
     RECT  94.104 0.523 94.554 1.675 ;
     RECT  92.556 0.571 93.366 1.723 ;
     RECT  94.104 1.675 94.59 1.723 ;
     RECT  95.832 0.091 95.85 1.723 ;
     RECT  100.656 0.091 100.674 1.723 ;
     RECT  101.88 0.091 101.898 1.723 ;
     RECT  104.796 0.317 104.814 1.723 ;
     RECT  116.496 1.147 116.586 1.723 ;
     RECT  117.324 0.571 117.666 1.723 ;
     RECT  120.276 0.167 120.294 1.723 ;
     RECT  123.804 0.605 125.622 1.723 ;
     RECT  100.584 1.723 101.898 1.771 ;
     RECT  103.392 1.723 103.41 1.771 ;
     RECT  110.016 1.723 110.142 1.771 ;
     RECT  112.284 1.723 112.446 1.771 ;
     RECT  113.4 1.723 113.418 1.771 ;
     RECT  115.164 1.723 115.182 1.771 ;
     RECT  116.496 1.723 118.026 1.771 ;
     RECT  99.936 1.771 101.898 1.819 ;
     RECT  103.176 1.771 103.41 1.819 ;
     RECT  106.524 1.147 106.542 1.819 ;
     RECT  107.496 1.723 107.514 1.819 ;
     RECT  120.276 1.723 120.366 1.867 ;
     RECT  121.176 1.723 121.194 1.867 ;
     RECT  122.004 0.701 122.022 1.867 ;
     RECT  123.12 1.723 125.622 1.867 ;
     RECT  97.164 1.723 99.018 1.915 ;
     RECT  118.764 1.771 118.782 1.915 ;
     RECT  110.016 1.771 112.446 1.921 ;
     RECT  113.292 1.771 113.418 1.921 ;
     RECT  115.164 1.771 118.026 1.957 ;
     RECT  114.732 1.957 118.026 1.993 ;
     RECT  118.764 1.915 119.358 1.993 ;
     RECT  92.556 1.723 94.59 2.029 ;
     RECT  106.524 1.819 107.514 2.059 ;
     RECT  114.732 1.993 119.358 2.059 ;
     RECT  120.276 1.867 125.622 2.059 ;
     RECT  110.016 1.921 113.418 2.065 ;
     RECT  97.164 1.915 99.198 2.101 ;
     RECT  99.936 1.819 103.41 2.101 ;
     RECT  92.268 2.029 94.59 2.191 ;
     RECT  95.652 1.723 96.318 2.191 ;
     RECT  97.092 2.101 103.554 2.191 ;
     RECT  104.544 1.723 105.642 2.191 ;
     RECT  106.524 2.059 107.658 2.191 ;
     RECT  108.936 1.921 108.954 2.191 ;
     RECT  110.016 2.065 113.634 2.191 ;
     RECT  114.732 2.059 125.622 2.191 ;
     RECT  92.268 2.191 103.734 2.227 ;
     RECT  104.544 2.191 108.09 2.227 ;
     RECT  104.472 2.227 108.09 2.263 ;
     RECT  108.936 2.191 109.062 2.263 ;
     RECT  109.98 2.191 125.622 2.263 ;
     RECT  104.472 2.263 125.622 2.299 ;
     RECT  92.052 2.227 103.734 2.371 ;
     RECT  104.472 2.299 125.766 2.371 ;
     RECT  104.472 2.371 125.874 2.395 ;
     RECT  126.615 2.143 126.705 2.395 ;
     RECT  2.415 2.143 2.505 2.413 ;
     RECT  7.815 2.143 7.905 2.413 ;
     RECT  13.215 2.143 13.305 2.413 ;
     RECT  18.615 2.143 18.705 2.413 ;
     RECT  24.015 2.143 24.105 2.413 ;
     RECT  29.415 2.143 29.505 2.413 ;
     RECT  34.815 2.143 34.905 2.413 ;
     RECT  40.215 2.143 40.305 2.413 ;
     RECT  45.615 2.143 45.705 2.413 ;
     RECT  51.015 2.143 51.105 2.413 ;
     RECT  56.415 2.143 56.505 2.413 ;
     RECT  61.815 2.143 61.905 2.413 ;
     RECT  67.215 2.143 67.305 2.413 ;
     RECT  72.615 2.143 72.705 2.413 ;
     RECT  78.015 2.143 78.105 2.413 ;
     RECT  83.415 2.143 83.505 2.413 ;
     RECT  88.815 2.143 88.905 2.413 ;
     RECT  104.472 2.395 126.705 2.413 ;
     RECT  132.015 2.143 132.105 2.413 ;
     RECT  137.415 2.143 137.505 2.413 ;
     RECT  142.815 2.143 142.905 2.413 ;
     RECT  148.215 2.143 148.305 2.413 ;
     RECT  153.615 2.143 153.705 2.413 ;
     RECT  159.015 2.143 159.105 2.413 ;
     RECT  164.415 2.143 164.505 2.413 ;
     RECT  169.815 2.143 169.905 2.413 ;
     RECT  175.215 2.143 175.305 2.413 ;
     RECT  180.615 2.143 180.705 2.413 ;
     RECT  186.015 2.143 186.105 2.413 ;
     RECT  191.415 2.143 191.505 2.413 ;
     RECT  196.815 2.143 196.905 2.413 ;
     RECT  202.215 2.143 202.305 2.413 ;
     RECT  207.615 2.143 207.705 2.413 ;
     RECT  213.015 2.143 213.105 2.413 ;
     RECT  91.512 2.371 103.734 2.461 ;
     RECT  104.472 2.413 126.897 2.461 ;
     RECT  88.815 2.413 89.097 4.495 ;
     RECT  90.36 4.459 90.378 4.495 ;
     RECT  88.815 4.495 90.378 4.531 ;
     RECT  88.815 4.531 90.774 4.541 ;
     RECT  90.036 4.541 90.774 4.891 ;
     RECT  91.512 2.461 126.897 4.891 ;
     RECT  88.815 4.541 89.097 5.563 ;
     RECT  90.036 4.891 126.897 5.563 ;
     RECT  88.815 5.563 126.897 6.619 ;
     RECT  88.632 6.619 126.897 6.655 ;
     RECT  87.408 6.817 87.57 6.853 ;
     RECT  88.308 6.655 126.897 6.853 ;
     RECT  87.408 6.853 126.897 7.051 ;
     RECT  86.364 6.961 86.382 7.195 ;
     RECT  87.264 7.051 126.897 7.195 ;
     RECT  86.22 7.195 86.382 7.321 ;
     RECT  87.12 7.195 126.897 7.321 ;
     RECT  86.22 7.321 126.897 7.349 ;
     RECT  86.616 7.349 126.897 7.373 ;
     RECT  86.688 7.373 126.897 8.339 ;
     RECT  86.688 8.339 125.874 8.779 ;
     RECT  86.58 8.779 125.874 9.049 ;
     RECT  86.544 9.049 125.874 9.581 ;
     RECT  86.652 9.581 125.874 9.751 ;
     RECT  126.615 8.339 126.897 9.751 ;
     RECT  85.896 10.165 85.914 10.253 ;
     RECT  86.652 9.751 126.897 10.471 ;
     RECT  86.184 10.471 126.897 11.129 ;
     RECT  85.788 11.131 85.806 11.171 ;
     RECT  86.796 11.129 126.897 11.201 ;
     RECT  86.796 11.201 125.694 11.983 ;
     RECT  86.364 11.983 125.694 11.995 ;
     RECT  86.22 11.995 125.694 12.091 ;
     RECT  126.468 11.201 126.897 12.091 ;
     RECT  86.22 12.091 126.897 12.749 ;
     RECT  86.22 12.749 125.766 12.989 ;
     RECT  86.76 12.989 125.766 13.055 ;
     RECT  86.796 13.055 125.766 13.639 ;
     RECT  126.615 12.749 126.897 13.639 ;
     RECT  86.796 13.639 126.897 14.791 ;
     RECT  86.724 14.791 126.897 18.031 ;
     RECT  86.436 18.031 126.897 18.419 ;
     RECT  85.824 18.427 85.842 18.491 ;
     RECT  86.58 18.419 126.897 18.563 ;
     RECT  86.724 18.563 126.897 19.031 ;
     RECT  86.724 19.031 125.766 19.579 ;
     RECT  86.22 19.579 125.766 19.643 ;
     RECT  86.724 19.643 125.766 19.885 ;
     RECT  126.615 19.031 126.897 19.885 ;
     RECT  86.724 19.885 126.897 20.731 ;
     RECT  86.436 20.731 126.897 20.827 ;
     RECT  86.256 20.827 126.897 20.885 ;
     RECT  86.724 20.885 126.897 21.119 ;
     RECT  86.724 21.119 125.406 21.263 ;
     RECT  126.144 21.119 126.897 21.533 ;
     RECT  86.724 21.263 125.298 21.767 ;
     RECT  86.724 21.767 124.902 22.621 ;
     RECT  86.724 22.621 125.37 22.739 ;
     RECT  125.352 22.739 125.37 22.811 ;
     RECT  86.724 22.739 124.218 23.009 ;
     RECT  86.724 23.009 123.93 23.315 ;
     RECT  86.724 23.315 121.914 23.947 ;
     RECT  86.688 23.947 121.914 24.205 ;
     RECT  122.796 23.315 123.93 24.205 ;
     RECT  86.688 24.205 123.93 24.331 ;
     RECT  86.652 24.331 123.93 24.503 ;
     RECT  86.652 24.503 121.497 24.619 ;
     RECT  86.076 24.619 121.497 24.665 ;
     RECT  122.796 24.503 123.93 25.079 ;
     RECT  24.015 2.413 24.297 25.147 ;
     RECT  24.015 25.147 24.39 25.277 ;
     RECT  82.656 25.147 82.674 25.277 ;
     RECT  86.472 24.665 121.497 25.277 ;
     RECT  123.912 25.079 123.93 25.619 ;
     RECT  86.652 25.277 121.497 25.709 ;
     RECT  120.276 25.709 121.497 25.781 ;
     RECT  101.844 25.709 119.538 25.817 ;
     RECT  101.844 25.817 119.43 25.853 ;
     RECT  120.564 25.781 121.497 25.979 ;
     RECT  120.672 25.979 121.497 26.159 ;
     RECT  86.652 25.709 101.07 26.203 ;
     RECT  18.615 2.413 18.897 26.347 ;
     RECT  34.815 2.413 35.097 26.485 ;
     RECT  24.015 25.277 24.297 26.491 ;
     RECT  45.615 2.413 45.897 26.491 ;
     RECT  56.415 2.413 56.697 26.491 ;
     RECT  67.215 2.413 67.497 26.491 ;
     RECT  78.015 2.413 78.297 26.491 ;
     RECT  34.704 26.485 35.097 26.525 ;
     RECT  23.904 26.491 24.297 26.528 ;
     RECT  45.504 26.491 45.897 26.528 ;
     RECT  56.304 26.491 56.697 26.528 ;
     RECT  67.104 26.491 67.497 26.528 ;
     RECT  77.904 26.491 78.297 26.528 ;
     RECT  101.844 25.853 119.286 26.555 ;
     RECT  14.832 26.347 14.85 26.621 ;
     RECT  18.615 26.347 18.918 26.621 ;
     RECT  86.616 26.203 101.07 26.671 ;
     RECT  101.844 26.555 118.134 26.671 ;
     RECT  119.016 26.555 119.286 26.789 ;
     RECT  86.616 26.671 118.134 26.824 ;
     RECT  119.124 26.789 119.178 26.825 ;
     RECT  86.076 26.824 118.134 26.861 ;
     RECT  119.124 26.825 119.142 26.933 ;
     RECT  13.215 2.413 13.497 27.115 ;
     RECT  13.215 27.115 13.59 27.341 ;
     RECT  86.58 26.861 118.134 27.473 ;
     RECT  86.58 27.473 114.894 27.599 ;
     RECT  86.58 27.599 114.75 27.635 ;
     RECT  115.74 27.473 116.694 27.779 ;
     RECT  115.74 27.779 116.622 27.869 ;
     RECT  117.432 27.473 118.134 27.869 ;
     RECT  86.58 27.635 114.606 27.917 ;
     RECT  115.74 27.869 116.586 27.917 ;
     RECT  86.688 27.917 114.606 27.941 ;
     RECT  117.432 27.869 117.738 27.941 ;
     RECT  117.432 27.941 117.45 28.175 ;
     RECT  86.688 27.941 114.066 28.319 ;
     RECT  115.74 27.917 116.097 28.319 ;
     RECT  88.704 28.319 114.066 28.409 ;
     RECT  88.776 28.409 113.814 28.541 ;
     RECT  86.688 28.319 87.966 28.679 ;
     RECT  88.776 28.541 111.258 28.787 ;
     RECT  88.776 28.787 110.862 28.859 ;
     RECT  90.612 28.859 110.862 28.949 ;
     RECT  111.996 28.541 113.814 28.985 ;
     RECT  90.612 28.949 100.602 29.021 ;
     RECT  111.996 28.985 112.626 29.057 ;
     RECT  113.436 28.985 113.454 29.057 ;
     RECT  86.472 28.795 86.598 29.219 ;
     RECT  90.612 29.021 99.954 29.219 ;
     RECT  101.34 28.949 110.862 29.219 ;
     RECT  85.032 29.191 85.05 29.261 ;
     RECT  98.532 29.219 99.954 29.363 ;
     RECT  98.964 29.363 99.954 29.561 ;
     RECT  87.48 28.679 87.966 29.569 ;
     RECT  88.776 28.859 89.838 29.569 ;
     RECT  101.448 29.219 110.862 29.597 ;
     RECT  101.556 29.597 110.862 29.605 ;
     RECT  99.615 29.561 99.954 29.633 ;
     RECT  87.48 29.569 89.838 29.641 ;
     RECT  90.612 29.219 97.506 29.641 ;
     RECT  112.608 29.057 112.626 29.669 ;
     RECT  87.48 29.641 97.506 29.759 ;
     RECT  101.556 29.605 111.222 29.759 ;
     RECT  87.48 29.759 97.254 29.903 ;
     RECT  96.588 29.903 97.254 30.029 ;
     RECT  86.472 29.219 86.49 30.073 ;
     RECT  101.556 29.759 110.826 30.269 ;
     RECT  101.556 30.269 101.718 30.299 ;
     RECT  86.472 30.073 86.562 30.307 ;
     RECT  87.48 29.903 95.418 30.307 ;
     RECT  101.556 30.299 101.574 30.335 ;
     RECT  98.604 30.451 98.622 30.713 ;
     RECT  86.472 30.307 95.418 30.749 ;
     RECT  102.456 30.269 110.826 30.749 ;
     RECT  115.815 28.319 116.097 30.811 ;
     RECT  122.796 25.079 123.066 30.839 ;
     RECT  13.215 27.341 13.497 30.847 ;
     RECT  123.048 30.839 123.066 30.991 ;
     RECT  123.048 30.991 123.102 31.019 ;
     RECT  122.22 30.991 122.238 31.109 ;
     RECT  115.815 30.811 116.622 31.117 ;
     RECT  115.815 31.117 116.838 31.145 ;
     RECT  123.084 31.019 123.102 31.145 ;
     RECT  109.944 30.749 110.826 31.181 ;
     RECT  114.588 31.117 114.606 31.217 ;
     RECT  116.82 31.145 116.838 31.217 ;
     RECT  102.456 30.749 109.098 31.531 ;
     RECT  109.944 31.181 110.697 31.531 ;
     RECT  102.456 31.531 110.697 31.685 ;
     RECT  96.876 30.029 97.254 31.765 ;
     RECT  96.876 31.765 97.326 31.793 ;
     RECT  102.456 31.685 109.026 31.793 ;
     RECT  97.236 31.793 97.326 31.829 ;
     RECT  102.456 31.793 108.954 31.829 ;
     RECT  86.472 30.749 95.382 31.919 ;
     RECT  97.308 31.829 97.326 31.919 ;
     RECT  102.456 31.829 108.306 31.919 ;
     RECT  102.42 31.927 102.438 31.997 ;
     RECT  103.5 31.919 103.518 32.063 ;
     RECT  104.256 31.919 108.306 32.063 ;
     RECT  96.192 31.915 96.426 32.189 ;
     RECT  104.796 32.063 108.306 32.189 ;
     RECT  18.615 26.621 18.897 32.197 ;
     RECT  104.904 32.189 108.306 32.261 ;
     RECT  104.904 32.261 107.046 32.333 ;
     RECT  96.192 32.189 96.21 32.459 ;
     RECT  105.015 32.333 107.046 32.459 ;
     RECT  108.18 32.261 108.306 32.459 ;
     RECT  86.472 31.919 95.166 32.477 ;
     RECT  105.015 32.459 105.426 32.495 ;
     RECT  108.18 32.459 108.198 32.495 ;
     RECT  7.815 2.413 8.097 32.737 ;
     RECT  106.524 32.459 106.65 32.765 ;
     RECT  109.944 31.685 110.697 32.801 ;
     RECT  86.472 32.477 94.986 32.909 ;
     RECT  106.524 32.765 106.542 32.909 ;
     RECT  86.472 32.909 90.486 32.957 ;
     RECT  88.815 32.957 90.486 32.999 ;
     RECT  91.62 32.909 94.986 33.035 ;
     RECT  91.836 33.035 94.986 33.413 ;
     RECT  93.24 33.413 94.986 33.421 ;
     RECT  68.832 33.511 69.138 33.581 ;
     RECT  93.24 33.421 95.346 33.611 ;
     RECT  68.832 33.581 68.85 33.629 ;
     RECT  91.836 33.413 92.502 34.051 ;
     RECT  91.584 34.051 92.502 34.109 ;
     RECT  88.815 32.999 90.27 34.219 ;
     RECT  88.815 34.219 90.378 34.349 ;
     RECT  98.028 34.459 98.046 34.889 ;
     RECT  91.836 34.109 92.502 35.041 ;
     RECT  97.776 35.035 97.794 35.075 ;
     RECT  76.32 35.323 76.338 35.401 ;
     RECT  76.32 35.401 76.662 35.429 ;
     RECT  76.644 35.429 76.662 35.453 ;
     RECT  78.015 26.528 78.297 37.627 ;
     RECT  78.015 37.627 78.354 37.831 ;
     RECT  101.484 37.471 101.502 37.861 ;
     RECT  78.015 37.831 78.642 37.901 ;
     RECT  101.268 37.861 101.502 38.399 ;
     RECT  102.816 38.371 102.834 38.429 ;
     RECT  101.484 38.399 101.502 38.939 ;
     RECT  93.24 33.611 94.986 40.253 ;
     RECT  105.015 32.495 105.297 40.261 ;
     RECT  98.28 40.219 98.298 40.289 ;
     RECT  103.392 40.261 103.41 40.301 ;
     RECT  105.015 40.261 105.426 40.301 ;
     RECT  97.992 40.411 98.01 40.469 ;
     RECT  113.4 42.421 113.418 42.461 ;
     RECT  113.112 42.601 113.13 42.749 ;
     RECT  115.815 31.145 116.097 44.539 ;
     RECT  115.38 44.539 116.097 44.609 ;
     RECT  116.928 44.443 116.946 44.609 ;
     RECT  110.415 32.801 110.697 47.191 ;
     RECT  114.588 47.083 114.606 47.213 ;
     RECT  99.615 29.633 99.897 47.275 ;
     RECT  105.015 40.301 105.297 47.275 ;
     RECT  111.636 46.747 111.654 47.309 ;
     RECT  99.615 47.275 99.99 47.315 ;
     RECT  105.015 47.275 105.39 47.315 ;
     RECT  110.088 47.191 110.697 47.315 ;
     RECT  91.656 35.041 92.502 49.003 ;
     RECT  93.24 40.253 94.914 49.003 ;
     RECT  91.656 49.003 94.914 49.085 ;
     RECT  91.656 49.085 94.497 49.199 ;
     RECT  76.788 51.601 76.806 51.677 ;
     RECT  75.24 51.691 75.258 51.737 ;
     RECT  91.656 49.199 92.502 52.459 ;
     RECT  91.188 52.459 92.502 52.709 ;
     RECT  91.656 52.709 92.502 52.861 ;
     RECT  93.24 49.199 94.497 52.861 ;
     RECT  91.656 52.861 94.497 53.021 ;
     RECT  91.656 53.021 92.502 54.139 ;
     RECT  34.815 26.525 35.097 54.565 ;
     RECT  24.015 26.528 24.297 54.571 ;
     RECT  45.615 26.528 45.897 54.571 ;
     RECT  56.415 26.528 56.697 54.571 ;
     RECT  67.215 26.528 67.497 54.571 ;
     RECT  78.015 37.901 78.297 54.571 ;
     RECT  88.815 34.349 90.126 54.571 ;
     RECT  90.972 54.139 92.502 54.599 ;
     RECT  34.704 54.565 35.097 54.605 ;
     RECT  23.904 54.571 24.297 54.608 ;
     RECT  45.504 54.571 45.897 54.608 ;
     RECT  56.304 54.571 56.697 54.608 ;
     RECT  67.104 54.571 67.497 54.608 ;
     RECT  77.904 54.571 78.297 54.608 ;
     RECT  88.704 54.571 90.126 54.608 ;
     RECT  91.26 54.599 92.502 54.608 ;
     RECT  88.815 54.608 90.126 59.701 ;
     RECT  88.815 59.701 90.342 59.837 ;
     RECT  95.544 62.731 95.562 63.239 ;
     RECT  113.796 67.819 113.814 68.099 ;
     RECT  112.248 68.245 112.266 68.285 ;
     RECT  88.815 59.837 90.126 69.989 ;
     RECT  45.615 54.608 45.897 70.771 ;
     RECT  45.615 70.771 46.134 70.829 ;
     RECT  110.415 47.315 110.697 72.379 ;
     RECT  110.415 72.379 111.402 72.391 ;
     RECT  110.415 72.391 111.69 72.419 ;
     RECT  111.672 72.419 111.69 72.461 ;
     RECT  13.215 30.847 14.202 74.317 ;
     RECT  15.012 28.957 15.03 74.317 ;
     RECT  91.656 54.608 92.502 75.389 ;
     RECT  39.276 31.621 39.294 76.469 ;
     RECT  13.215 74.317 15.03 76.477 ;
     RECT  7.308 32.737 8.097 76.939 ;
     RECT  6.912 76.939 8.097 77.009 ;
     RECT  6.552 77.161 6.57 77.213 ;
     RECT  7.308 77.009 8.097 78.091 ;
     RECT  61.815 2.413 62.097 78.475 ;
     RECT  7.308 78.091 8.298 78.601 ;
     RECT  7.164 78.601 8.298 78.629 ;
     RECT  61.524 78.475 62.097 78.629 ;
     RECT  7.164 78.629 8.097 78.653 ;
     RECT  7.308 78.653 8.097 80.395 ;
     RECT  10.008 80.923 10.026 81.059 ;
     RECT  7.308 80.395 8.226 81.211 ;
     RECT  7.308 81.211 8.91 81.485 ;
     RECT  11.592 69.997 11.61 81.499 ;
     RECT  10.908 81.499 11.61 81.599 ;
     RECT  10.548 81.751 10.566 81.821 ;
     RECT  12.384 32.233 12.402 82.075 ;
     RECT  13.215 76.477 15.246 82.075 ;
     RECT  7.308 81.485 8.298 82.139 ;
     RECT  7.308 82.139 8.097 82.291 ;
     RECT  11.592 81.599 11.61 82.291 ;
     RECT  12.384 82.075 15.246 82.291 ;
     RECT  11.592 82.291 15.246 82.349 ;
     RECT  7.164 82.291 8.097 82.637 ;
     RECT  12.384 82.349 15.246 82.637 ;
     RECT  11.592 82.349 11.61 82.651 ;
     RECT  10.008 82.651 10.026 82.688 ;
     RECT  11.196 82.651 11.61 82.688 ;
     RECT  8.892 82.831 8.91 82.973 ;
     RECT  10.08 82.831 10.098 83.213 ;
     RECT  16.956 29.029 16.974 85.099 ;
     RECT  12.384 82.637 12.402 85.261 ;
     RECT  13.215 82.637 15.246 85.261 ;
     RECT  12.384 85.261 15.714 85.325 ;
     RECT  16.812 85.099 16.974 85.483 ;
     RECT  13.215 85.325 15.714 85.517 ;
     RECT  16.596 85.483 16.974 85.999 ;
     RECT  10.548 86.059 10.566 86.459 ;
     RECT  16.272 85.999 16.974 86.621 ;
     RECT  16.812 86.621 16.974 86.635 ;
     RECT  9.432 86.587 9.45 86.639 ;
     RECT  16.812 86.635 17.154 86.999 ;
     RECT  16.812 86.999 16.974 87.197 ;
     RECT  29.415 2.413 29.697 87.211 ;
     RECT  29.415 87.211 29.898 87.241 ;
     RECT  29.415 87.241 30.222 87.581 ;
     RECT  30.636 88.027 30.654 88.051 ;
     RECT  24.015 54.608 24.297 88.315 ;
     RECT  26.784 88.171 26.802 88.349 ;
     RECT  30.636 88.051 30.978 88.349 ;
     RECT  24.015 88.315 24.39 88.355 ;
     RECT  83.415 2.413 83.697 91.915 ;
     RECT  83.415 91.915 83.934 92.129 ;
     RECT  82.368 92.155 82.386 92.201 ;
     RECT  25.92 95.179 25.938 95.639 ;
     RECT  22.824 95.611 22.842 95.741 ;
     RECT  25.56 95.707 25.578 95.747 ;
     RECT  24.015 88.355 24.297 95.755 ;
     RECT  23.508 95.755 24.297 96.179 ;
     RECT  22.392 96.151 22.41 96.221 ;
     RECT  11.592 82.688 11.61 96.601 ;
     RECT  12.384 85.325 12.402 96.601 ;
     RECT  86.472 32.957 87.894 96.629 ;
     RECT  13.215 85.517 15.246 96.989 ;
     RECT  7.308 82.637 8.097 97.483 ;
     RECT  7.02 97.483 8.097 97.915 ;
     RECT  6.732 97.915 8.097 98.069 ;
     RECT  13.215 96.989 14.454 98.443 ;
     RECT  15.228 96.989 15.246 98.443 ;
     RECT  13.215 98.443 15.246 98.609 ;
     RECT  10.836 98.443 10.854 98.621 ;
     RECT  13.215 98.609 14.454 98.645 ;
     RECT  16.956 87.197 16.974 98.761 ;
     RECT  16.956 98.761 17.262 98.879 ;
     RECT  33.876 98.635 33.894 98.879 ;
     RECT  15.228 98.609 15.246 98.995 ;
     RECT  32.76 99.019 32.778 99.059 ;
     RECT  15.228 98.995 15.894 99.121 ;
     RECT  15.228 99.121 16.11 99.691 ;
     RECT  9.612 96.997 9.63 99.739 ;
     RECT  15.192 99.691 16.11 99.841 ;
     RECT  10.836 99.931 10.854 100.061 ;
     RECT  13.215 98.645 14.382 100.111 ;
     RECT  15.192 99.841 16.146 100.111 ;
     RECT  11.592 96.601 12.402 100.201 ;
     RECT  8.928 99.739 9.63 100.229 ;
     RECT  7.815 98.069 8.097 100.237 ;
     RECT  13.215 100.111 16.146 100.265 ;
     RECT  44.352 69.493 44.37 100.265 ;
     RECT  31.392 100.741 31.41 100.781 ;
     RECT  11.412 100.201 12.402 100.849 ;
     RECT  13.215 100.265 15.894 100.849 ;
     RECT  7.815 100.237 8.802 100.891 ;
     RECT  16.956 98.879 16.974 100.891 ;
     RECT  7.632 100.891 8.802 101.039 ;
     RECT  9.612 100.229 9.63 101.047 ;
     RECT  5.76 98.185 5.778 101.155 ;
     RECT  6.732 98.069 6.75 101.155 ;
     RECT  9.612 101.047 10.098 101.155 ;
     RECT  9.612 101.155 10.35 101.191 ;
     RECT  11.196 100.849 15.894 101.191 ;
     RECT  16.812 100.891 16.974 101.281 ;
     RECT  29.415 87.581 29.697 101.281 ;
     RECT  16.812 101.281 17.154 101.309 ;
     RECT  16.956 101.309 17.154 101.357 ;
     RECT  31.5 101.317 31.518 101.357 ;
     RECT  29.415 101.281 30.402 101.405 ;
     RECT  9.612 101.191 15.894 101.453 ;
     RECT  9.612 101.453 14.994 101.695 ;
     RECT  16.956 101.357 17.082 101.759 ;
     RECT  7.815 101.039 8.802 101.929 ;
     RECT  9.54 101.695 14.994 101.929 ;
     RECT  7.815 101.929 14.994 102.043 ;
     RECT  5.76 101.155 6.75 102.091 ;
     RECT  7.596 102.043 14.994 102.091 ;
     RECT  5.76 102.091 14.994 102.119 ;
     RECT  15.876 101.453 15.894 102.271 ;
     RECT  5.76 102.119 14.562 102.299 ;
     RECT  18.615 32.197 19.134 102.331 ;
     RECT  15.336 102.271 15.894 102.389 ;
     RECT  18 102.331 19.134 102.389 ;
     RECT  18.324 102.389 19.134 102.413 ;
     RECT  2.415 2.413 2.697 102.739 ;
     RECT  4.572 102.505 4.59 102.811 ;
     RECT  3.6 102.811 4.59 102.929 ;
     RECT  18.615 102.413 19.134 102.929 ;
     RECT  41.544 75.505 41.562 103.001 ;
     RECT  0.468 103.009 0.486 103.045 ;
     RECT  4.284 102.929 4.59 103.045 ;
     RECT  5.76 102.299 14.454 103.045 ;
     RECT  2.304 102.739 2.697 103.081 ;
     RECT  15.876 102.389 15.894 103.171 ;
     RECT  16.956 101.759 16.974 103.171 ;
     RECT  86.472 96.629 86.49 103.199 ;
     RECT  15.876 103.171 16.974 103.229 ;
     RECT  4.284 103.045 14.454 103.243 ;
     RECT  0.468 103.045 0.558 103.277 ;
     RECT  4.284 103.243 15.03 103.315 ;
     RECT  15.876 103.229 15.894 103.315 ;
     RECT  4.284 103.315 15.894 103.541 ;
     RECT  0.468 103.277 0.486 103.565 ;
     RECT  2.304 103.081 3.222 103.723 ;
     RECT  2.268 103.723 3.222 103.819 ;
     RECT  4.284 103.541 15.066 103.819 ;
     RECT  99.615 47.315 99.897 103.981 ;
     RECT  99.216 103.981 99.897 104.161 ;
     RECT  98.892 104.161 99.897 104.237 ;
     RECT  2.268 103.819 15.066 104.279 ;
     RECT  15.876 103.541 15.894 104.279 ;
     RECT  16.956 103.229 16.974 104.287 ;
     RECT  0.54 104.287 0.558 104.333 ;
     RECT  4.356 104.279 15.066 104.431 ;
     RECT  4.356 104.431 15.102 104.549 ;
     RECT  87.48 96.629 87.894 104.729 ;
     RECT  4.356 104.549 14.958 104.819 ;
     RECT  16.956 104.287 17.694 104.819 ;
     RECT  2.268 104.279 3.618 105.205 ;
     RECT  4.356 104.819 14.886 105.205 ;
     RECT  16.092 104.875 16.11 105.205 ;
     RECT  15.84 105.205 16.11 105.359 ;
     RECT  17.676 104.819 17.694 105.431 ;
     RECT  16.092 105.359 16.11 105.511 ;
     RECT  16.884 105.451 16.902 105.511 ;
     RECT  16.092 105.511 16.902 105.629 ;
     RECT  2.268 105.205 14.886 105.637 ;
     RECT  16.416 105.629 16.902 105.637 ;
     RECT  34.815 54.605 35.097 105.643 ;
     RECT  16.416 105.637 17.01 105.677 ;
     RECT  2.268 105.637 14.922 105.745 ;
     RECT  16.992 105.677 17.01 105.809 ;
     RECT  45.615 70.829 45.897 105.871 ;
     RECT  56.415 54.608 56.697 105.871 ;
     RECT  67.215 54.608 67.497 105.871 ;
     RECT  78.015 54.608 78.297 105.871 ;
     RECT  88.815 69.989 89.802 105.871 ;
     RECT  2.268 105.745 15.354 105.899 ;
     RECT  34.815 105.643 35.73 105.899 ;
     RECT  36.828 105.871 36.846 105.917 ;
     RECT  45.504 105.871 45.897 105.917 ;
     RECT  56.304 105.871 56.697 105.917 ;
     RECT  67.104 105.871 67.497 105.917 ;
     RECT  77.904 105.871 78.297 105.917 ;
     RECT  88.704 105.871 89.802 105.917 ;
     RECT  2.268 105.899 14.922 106.205 ;
     RECT  2.268 106.205 14.814 106.313 ;
     RECT  2.268 106.313 14.634 106.411 ;
     RECT  87.876 104.729 87.894 106.709 ;
     RECT  0.54 106.447 0.558 106.987 ;
     RECT  15.696 106.603 15.714 107.015 ;
     RECT  2.232 106.411 14.634 107.059 ;
     RECT  0.324 106.987 0.558 107.095 ;
     RECT  2.232 107.059 15.462 107.159 ;
     RECT  15.444 107.159 15.462 107.249 ;
     RECT  2.232 107.159 14.67 107.285 ;
     RECT  0.108 107.095 0.558 107.309 ;
     RECT  0.108 107.309 0.522 107.597 ;
     RECT  87.696 106.861 87.714 107.789 ;
     RECT  88.815 105.917 89.802 107.825 ;
     RECT  86.436 107.797 87.39 107.905 ;
     RECT  2.304 107.285 14.67 107.941 ;
     RECT  15.84 107.899 15.858 108.059 ;
     RECT  85.572 107.905 87.39 108.059 ;
     RECT  91.656 75.389 92.178 108.059 ;
     RECT  86.256 108.059 87.39 108.095 ;
     RECT  0.144 107.597 0.522 108.125 ;
     RECT  2.304 107.941 14.742 108.131 ;
     RECT  0.468 108.125 0.522 108.175 ;
     RECT  86.256 108.095 87.174 108.203 ;
     RECT  15.12 108.139 15.138 108.239 ;
     RECT  86.436 108.203 86.454 108.317 ;
     RECT  0.468 108.175 0.558 108.461 ;
     RECT  0.504 108.461 0.558 108.715 ;
     RECT  0.504 108.715 0.666 108.845 ;
     RECT  2.304 108.131 14.238 108.913 ;
     RECT  2.304 108.913 14.742 109.021 ;
     RECT  91.656 108.059 91.674 109.111 ;
     RECT  91.656 109.111 92.25 109.139 ;
     RECT  105.015 47.315 105.297 109.147 ;
     RECT  2.304 109.021 14.886 109.175 ;
     RECT  0.504 108.845 0.558 109.219 ;
     RECT  2.304 109.175 10.71 109.219 ;
     RECT  92.232 109.139 92.25 109.229 ;
     RECT  70.056 107.761 70.074 109.247 ;
     RECT  93.24 53.021 94.497 109.247 ;
     RECT  11.556 109.175 14.886 109.291 ;
     RECT  91.44 109.255 91.458 109.525 ;
     RECT  91.116 109.525 91.458 109.715 ;
     RECT  93.924 109.247 94.497 109.715 ;
     RECT  93.996 109.715 94.497 109.751 ;
     RECT  11.556 109.291 14.958 109.859 ;
     RECT  86.652 109.723 86.67 109.859 ;
     RECT  91.116 109.715 91.134 109.859 ;
     RECT  2.268 109.219 10.71 109.867 ;
     RECT  11.556 109.859 14.67 109.912 ;
     RECT  2.232 109.867 10.71 109.921 ;
     RECT  11.52 109.912 14.67 109.921 ;
     RECT  65.412 109.435 65.43 109.949 ;
     RECT  65.088 109.957 65.106 109.997 ;
     RECT  2.232 109.921 14.67 110.255 ;
     RECT  2.268 110.255 14.67 110.489 ;
     RECT  0.468 109.219 0.558 110.635 ;
     RECT  2.304 110.489 14.67 110.641 ;
     RECT  0.144 110.635 0.558 110.813 ;
     RECT  2.304 110.641 14.742 111.101 ;
     RECT  0.324 110.813 0.558 111.245 ;
     RECT  2.304 111.101 14.67 111.335 ;
     RECT  0.324 111.245 0.342 111.595 ;
     RECT  0.108 111.595 0.342 111.629 ;
     RECT  2.304 111.335 14.598 111.713 ;
     RECT  2.304 111.713 14.562 111.787 ;
     RECT  1.152 111.691 1.17 111.979 ;
     RECT  0.108 111.629 0.162 112.301 ;
     RECT  1.152 111.979 1.278 112.363 ;
     RECT  1.152 112.363 1.314 112.555 ;
     RECT  2.196 111.787 14.562 112.555 ;
     RECT  1.152 112.555 14.562 113.531 ;
     RECT  1.728 113.531 14.562 113.801 ;
     RECT  14.544 113.801 14.562 113.873 ;
     RECT  1.728 113.801 13.662 113.909 ;
     RECT  1.728 113.909 13.518 113.999 ;
     RECT  1.728 113.999 13.497 114.071 ;
     RECT  1.728 114.071 12.222 114.107 ;
     RECT  1.728 114.107 5.238 114.143 ;
     RECT  1.728 114.143 5.13 114.179 ;
     RECT  2.304 114.179 5.13 114.269 ;
     RECT  5.976 114.107 12.222 114.269 ;
     RECT  5.976 114.269 12.186 114.305 ;
     RECT  12.168 114.305 12.186 114.377 ;
     RECT  5.976 114.305 11.394 114.449 ;
     RECT  5.976 114.449 8.262 114.539 ;
     RECT  0.108 112.301 0.126 114.547 ;
     RECT  0.036 114.547 0.126 114.575 ;
     RECT  5.976 114.539 8.154 114.575 ;
     RECT  9.432 114.449 11.394 114.647 ;
     RECT  2.304 114.269 4.734 114.809 ;
     RECT  6.084 114.575 8.154 114.809 ;
     RECT  9.432 114.647 10.026 114.809 ;
     RECT  2.304 114.809 4.23 114.845 ;
     RECT  9.432 114.809 9.882 114.845 ;
     RECT  9.432 114.845 9.558 114.881 ;
     RECT  9.54 114.881 9.558 114.917 ;
     RECT  0.036 114.575 0.054 114.989 ;
     RECT  2.415 114.845 4.23 114.989 ;
     RECT  12.96 114.071 13.497 114.989 ;
     RECT  2.415 114.989 2.97 115.079 ;
     RECT  6.768 114.809 8.154 115.079 ;
     RECT  6.768 115.079 6.786 115.151 ;
     RECT  7.596 115.079 8.097 115.223 ;
     RECT  94.215 109.751 94.497 117.979 ;
     RECT  93.888 117.979 94.497 118.049 ;
     RECT  94.176 118.049 94.497 118.157 ;
     RECT  99.615 104.237 99.897 121.963 ;
     RECT  99.18 121.963 99.897 122.521 ;
     RECT  97.2 109.687 97.218 122.635 ;
     RECT  99.108 122.521 99.897 122.639 ;
     RECT  97.2 122.635 97.83 122.719 ;
     RECT  97.2 122.719 98.298 122.755 ;
     RECT  97.2 122.755 98.622 123.089 ;
     RECT  97.2 123.089 97.362 123.323 ;
     RECT  98.136 123.089 98.622 123.449 ;
     RECT  98.28 123.449 98.622 123.529 ;
     RECT  98.28 123.529 98.766 123.557 ;
     RECT  98.604 123.557 98.766 123.565 ;
     RECT  99.615 122.639 99.897 123.565 ;
     RECT  98.604 123.565 99.897 123.989 ;
     RECT  98.712 123.989 99.897 124.061 ;
     RECT  99.072 124.061 99.897 169.889 ;
     RECT  97.2 123.323 97.218 184.469 ;
     RECT  105.015 109.147 105.714 186.359 ;
     RECT  109.044 107.761 109.062 186.367 ;
     RECT  107.784 109.723 107.802 193.189 ;
     RECT  103.5 170.005 103.518 193.217 ;
     RECT  106.56 193.117 106.578 193.217 ;
     RECT  107.424 193.189 107.802 211.081 ;
     RECT  108.576 186.367 109.062 211.081 ;
     RECT  107.424 211.081 109.386 211.549 ;
     RECT  97.056 184.585 97.074 211.649 ;
     RECT  107.424 211.549 109.602 211.919 ;
     RECT  108.18 211.919 109.602 212.009 ;
     RECT  108.18 212.009 109.314 212.288 ;
     RECT  108.18 212.288 109.17 212.855 ;
     RECT  107.424 211.919 107.442 212.935 ;
     RECT  108.18 212.855 109.062 212.935 ;
     RECT  2.415 115.079 2.697 213.587 ;
     RECT  7.815 115.223 8.097 213.587 ;
     RECT  13.215 114.989 13.497 213.587 ;
     RECT  18.615 102.929 18.897 213.587 ;
     RECT  24.015 96.179 24.297 213.587 ;
     RECT  29.415 101.405 29.697 213.587 ;
     RECT  34.815 105.899 35.097 213.587 ;
     RECT  40.215 2.413 40.497 213.587 ;
     RECT  45.615 105.917 45.897 213.587 ;
     RECT  51.015 2.413 51.297 213.587 ;
     RECT  56.415 105.917 56.697 213.587 ;
     RECT  61.815 78.629 62.097 213.587 ;
     RECT  67.215 105.917 67.497 213.587 ;
     RECT  72.615 2.413 72.897 213.587 ;
     RECT  78.015 105.917 78.297 213.587 ;
     RECT  83.415 92.129 83.697 213.587 ;
     RECT  88.815 107.825 89.097 213.587 ;
     RECT  94.215 118.157 94.497 213.587 ;
     RECT  99.615 169.889 99.897 213.587 ;
     RECT  105.015 186.359 105.297 213.587 ;
     RECT  110.415 72.419 110.697 213.587 ;
     RECT  115.815 44.609 116.097 213.587 ;
     RECT  121.215 26.159 121.497 213.587 ;
     RECT  126.615 21.533 126.897 213.587 ;
     RECT  132.015 2.413 132.297 213.587 ;
     RECT  137.415 2.413 137.697 213.587 ;
     RECT  142.815 2.413 143.097 213.587 ;
     RECT  148.215 2.413 148.497 213.587 ;
     RECT  153.615 2.413 153.897 213.587 ;
     RECT  159.015 2.413 159.297 213.587 ;
     RECT  164.415 2.413 164.697 213.587 ;
     RECT  169.815 2.413 170.097 213.587 ;
     RECT  175.215 2.413 175.497 213.587 ;
     RECT  180.615 2.413 180.897 213.587 ;
     RECT  186.015 2.413 186.297 213.587 ;
     RECT  191.415 2.413 191.697 213.587 ;
     RECT  196.815 2.413 197.097 213.587 ;
     RECT  202.215 2.413 202.497 213.587 ;
     RECT  207.615 2.413 207.897 213.587 ;
     RECT  213.015 2.413 213.297 213.587 ;
     RECT  107.424 212.935 109.062 213.629 ;
     RECT  107.424 213.629 108.198 213.665 ;
     RECT  107.424 213.665 107.946 213.677 ;
     RECT  107.424 213.677 107.766 213.737 ;
     RECT  2.415 213.587 2.505 213.857 ;
     RECT  7.815 213.587 7.905 213.857 ;
     RECT  13.215 213.587 13.305 213.857 ;
     RECT  18.615 213.587 18.705 213.857 ;
     RECT  24.015 213.587 24.105 213.857 ;
     RECT  29.415 213.587 29.505 213.857 ;
     RECT  34.815 213.587 34.905 213.857 ;
     RECT  40.215 213.587 40.305 213.857 ;
     RECT  45.615 213.587 45.705 213.857 ;
     RECT  51.015 213.587 51.105 213.857 ;
     RECT  56.415 213.587 56.505 213.857 ;
     RECT  61.815 213.587 61.905 213.857 ;
     RECT  67.215 213.587 67.305 213.857 ;
     RECT  72.615 213.587 72.705 213.857 ;
     RECT  78.015 213.587 78.105 213.857 ;
     RECT  83.415 213.587 83.505 213.857 ;
     RECT  88.815 213.587 88.905 213.857 ;
     RECT  94.215 213.587 94.305 213.857 ;
     RECT  99.615 213.587 99.705 213.857 ;
     RECT  105.015 213.587 105.105 213.857 ;
     RECT  110.415 213.587 110.505 213.857 ;
     RECT  115.815 213.587 115.905 213.857 ;
     RECT  121.215 213.587 121.305 213.857 ;
     RECT  126.615 213.587 126.705 213.857 ;
     RECT  132.015 213.587 132.105 213.857 ;
     RECT  137.415 213.587 137.505 213.857 ;
     RECT  142.815 213.587 142.905 213.857 ;
     RECT  148.215 213.587 148.305 213.857 ;
     RECT  153.615 213.587 153.705 213.857 ;
     RECT  159.015 213.587 159.105 213.857 ;
     RECT  164.415 213.587 164.505 213.857 ;
     RECT  169.815 213.587 169.905 213.857 ;
     RECT  175.215 213.587 175.305 213.857 ;
     RECT  180.615 213.587 180.705 213.857 ;
     RECT  186.015 213.587 186.105 213.857 ;
     RECT  191.415 213.587 191.505 213.857 ;
     RECT  196.815 213.587 196.905 213.857 ;
     RECT  202.215 213.587 202.305 213.857 ;
     RECT  207.615 213.587 207.705 213.857 ;
     RECT  213.015 213.587 213.105 213.857 ;
     RECT  107.424 213.737 107.442 214.349 ;
    LAYER M4 ;
     RECT  0.06 103.056 2.257 112.968 ;
     RECT  2.257 103.056 2.408 113.832 ;
     RECT  2.408 2.148 2.512 213.852 ;
     RECT  2.512 2.418 2.704 213.582 ;
     RECT  2.704 103.824 2.765 113.976 ;
     RECT  2.765 104.016 2.801 113.976 ;
     RECT  2.801 104.4 2.837 113.976 ;
     RECT  2.837 105.456 2.845 113.976 ;
     RECT  2.845 105.456 2.873 113.832 ;
     RECT  2.873 105.456 2.945 112.776 ;
     RECT  2.945 105.456 3.089 112.488 ;
     RECT  2.873 113.808 3.197 113.832 ;
     RECT  3.089 105.456 3.305 106.536 ;
     RECT  3.089 107.52 4.021 112.488 ;
     RECT  2.837 104.4 4.417 104.424 ;
     RECT  3.305 105.456 4.525 105.48 ;
     RECT  3.305 106.512 4.525 106.536 ;
     RECT  4.021 107.52 4.525 113.256 ;
     RECT  4.417 103.632 4.597 104.424 ;
     RECT  4.525 105.456 4.597 106.536 ;
     RECT  4.525 107.52 4.669 113.64 ;
     RECT  4.597 103.632 4.849 106.536 ;
     RECT  4.849 103.536 5.101 106.536 ;
     RECT  5.101 103.152 5.209 106.536 ;
     RECT  4.669 107.52 5.209 114.12 ;
     RECT  5.209 103.152 6.073 114.12 ;
     RECT  6.073 103.152 6.157 114.6 ;
     RECT  6.524 77.184 6.611 77.208 ;
     RECT  6.157 103.152 6.757 114.552 ;
     RECT  6.085 101.568 7.541 101.592 ;
     RECT  6.757 102.672 7.541 114.552 ;
     RECT  7.109 82.608 7.573 82.632 ;
     RECT  7.573 81.792 7.621 82.632 ;
     RECT  6.757 99.936 7.621 99.96 ;
     RECT  7.541 101.568 7.621 114.552 ;
     RECT  7.621 80.928 7.669 82.632 ;
     RECT  6.901 24.912 7.808 24.936 ;
     RECT  6.901 76.944 7.808 76.968 ;
     RECT  7.153 78.624 7.808 78.648 ;
     RECT  7.669 80.928 7.808 82.968 ;
     RECT  7.525 96.192 7.808 96.216 ;
     RECT  7.009 97.488 7.808 97.512 ;
     RECT  5.893 98.592 7.808 98.616 ;
     RECT  7.621 99.936 7.808 114.552 ;
     RECT  7.808 2.148 7.912 213.852 ;
     RECT  7.912 2.418 8.104 213.582 ;
     RECT  8.104 103.056 8.129 114.12 ;
     RECT  8.104 80.4 8.281 80.424 ;
     RECT  8.104 78.096 8.353 78.12 ;
     RECT  8.104 81.456 8.387 82.968 ;
     RECT  8.129 103.056 8.417 114.024 ;
     RECT  8.417 103.2 8.453 114.024 ;
     RECT  8.387 82.944 8.921 82.968 ;
     RECT  8.387 81.456 8.965 81.48 ;
     RECT  9.421 86.592 9.505 86.616 ;
     RECT  8.104 101.568 9.529 101.592 ;
     RECT  9.529 101.568 9.836 101.736 ;
     RECT  8.453 103.2 9.836 113.928 ;
     RECT  9.836 101.568 9.877 113.928 ;
     RECT  8.104 26.64 10.069 26.664 ;
     RECT  9.997 82.656 10.069 82.68 ;
     RECT  10.069 82.656 10.115 83.208 ;
     RECT  10.115 83.184 10.153 83.208 ;
     RECT  10.069 26.64 10.165 26.856 ;
     RECT  9.997 80.928 10.211 80.952 ;
     RECT  9.877 101.184 10.289 113.928 ;
     RECT  10.289 101.184 10.361 101.592 ;
     RECT  10.289 102.624 10.361 113.928 ;
     RECT  10.021 33.552 10.549 33.576 ;
     RECT  10.501 81.504 10.588 81.816 ;
     RECT  10.537 86.064 10.621 86.088 ;
     RECT  8.104 98.592 10.825 98.616 ;
     RECT  8.104 99.696 10.825 99.96 ;
     RECT  10.361 103.488 10.829 113.928 ;
     RECT  10.825 98.448 10.865 98.616 ;
     RECT  10.588 81.504 10.937 81.528 ;
     RECT  10.829 103.632 10.973 113.928 ;
     RECT  10.825 99.696 10.981 100.056 ;
     RECT  10.973 113.424 11.045 113.928 ;
     RECT  10.973 103.632 11.153 112.44 ;
     RECT  10.165 26.64 11.221 27.192 ;
     RECT  8.104 28.176 11.221 28.2 ;
     RECT  11.185 82.656 11.269 82.68 ;
     RECT  11.153 103.632 11.333 112.344 ;
     RECT  11.333 103.68 11.585 112.344 ;
     RECT  11.045 113.424 11.657 113.448 ;
     RECT  11.585 104.064 11.873 112.344 ;
     RECT  11.873 105.504 12.229 112.344 ;
     RECT  12.229 105.504 12.233 113.256 ;
     RECT  10.361 101.328 12.257 101.592 ;
     RECT  12.236 82.32 12.581 82.344 ;
     RECT  11.221 26.64 12.613 28.2 ;
     RECT  11.873 104.064 12.625 104.088 ;
     RECT  12.257 101.328 12.869 102.072 ;
     RECT  12.625 103.584 12.869 104.088 ;
     RECT  12.581 82.08 12.877 82.344 ;
     RECT  12.869 101.328 13.093 104.088 ;
     RECT  12.233 105.504 13.093 106.44 ;
     RECT  8.104 24.912 13.208 24.936 ;
     RECT  12.613 26.544 13.208 28.2 ;
     RECT  8.104 29.472 13.208 29.496 ;
     RECT  8.104 30.864 13.208 30.888 ;
     RECT  10.549 32.784 13.208 33.576 ;
     RECT  9.157 35.424 13.208 35.448 ;
     RECT  9.253 37.872 13.208 37.896 ;
     RECT  12.877 82.08 13.208 82.632 ;
     RECT  12.853 85.296 13.208 85.32 ;
     RECT  13.093 87.552 13.208 87.576 ;
     RECT  8.104 96.192 13.208 96.216 ;
     RECT  10.865 98.448 13.208 98.472 ;
     RECT  10.981 99.504 13.208 100.056 ;
     RECT  13.093 101.328 13.208 106.44 ;
     RECT  12.233 107.808 13.208 113.256 ;
     RECT  13.208 2.148 13.312 213.852 ;
     RECT  13.312 2.418 13.504 213.582 ;
     RECT  13.504 107.904 13.601 111.864 ;
     RECT  13.601 107.904 13.619 111.336 ;
     RECT  13.504 84.96 14.044 85.848 ;
     RECT  13.504 82.08 14.051 83.16 ;
     RECT  14.051 82.08 14.077 82.68 ;
     RECT  14.044 84.96 14.099 85.512 ;
     RECT  13.619 107.904 14.141 111 ;
     RECT  13.504 113.232 14.141 113.256 ;
     RECT  14.141 107.904 14.213 110.328 ;
     RECT  14.099 85.488 14.393 85.512 ;
     RECT  13.504 101.328 14.393 105.768 ;
     RECT  14.393 101.328 14.429 104.904 ;
     RECT  14.213 109.2 14.465 110.328 ;
     RECT  14.077 82.656 14.473 82.68 ;
     RECT  14.429 101.328 14.533 104.52 ;
     RECT  14.213 107.904 14.537 108.072 ;
     RECT  14.533 101.28 14.572 104.52 ;
     RECT  13.504 87.552 14.573 87.576 ;
     RECT  13.504 98.448 14.573 100.248 ;
     RECT  14.572 103.392 14.579 104.52 ;
     RECT  14.465 109.2 14.681 110.04 ;
     RECT  13.504 96.192 14.773 96.216 ;
     RECT  13.504 26.544 14.821 28.488 ;
     RECT  14.857 87.216 14.941 87.24 ;
     RECT  14.572 101.28 14.969 102.408 ;
     RECT  14.579 103.392 14.969 104.28 ;
     RECT  14.969 103.392 15.005 104.088 ;
     RECT  15.181 84.96 15.265 84.984 ;
     RECT  14.573 98.592 15.541 100.248 ;
     RECT  15.541 98.064 15.587 100.248 ;
     RECT  15.685 106.608 15.769 106.632 ;
     RECT  15.587 98.064 15.779 98.088 ;
     RECT  14.537 107.904 15.869 107.928 ;
     RECT  15.005 104.064 16.081 104.088 ;
     RECT  15.587 99.168 16.085 100.248 ;
     RECT  15.637 87.264 16.213 87.576 ;
     RECT  15.685 85.488 16.22 85.512 ;
     RECT  16.213 86.592 16.22 87.576 ;
     RECT  16.081 104.064 16.307 105.48 ;
     RECT  14.969 101.328 16.405 102.408 ;
     RECT  16.307 105.456 16.405 105.48 ;
     RECT  16.405 100.752 16.477 102.408 ;
     RECT  16.307 104.064 16.477 104.088 ;
     RECT  16.477 100.752 16.547 104.088 ;
     RECT  16.547 100.848 16.561 104.088 ;
     RECT  13.504 24.624 16.597 24.936 ;
     RECT  14.821 26.352 16.597 28.488 ;
     RECT  16.22 85.488 16.697 87.576 ;
     RECT  16.697 86.64 16.789 87.576 ;
     RECT  16.085 99.168 16.835 99.72 ;
     RECT  16.405 105.456 16.957 105.672 ;
     RECT  16.789 86.64 17.209 88.104 ;
     RECT  17.209 87.264 17.893 88.104 ;
     RECT  16.597 24.624 18.608 28.488 ;
     RECT  13.504 29.472 18.608 29.496 ;
     RECT  13.504 30.864 18.608 30.888 ;
     RECT  13.504 32.784 18.608 33.576 ;
     RECT  13.504 35.424 18.608 35.448 ;
     RECT  13.504 37.872 18.608 37.896 ;
     RECT  13.504 54.576 18.608 54.6 ;
     RECT  16.801 85.104 18.608 85.128 ;
     RECT  17.893 87.264 18.608 88.2 ;
     RECT  14.773 95.616 18.608 96.216 ;
     RECT  16.835 99.168 18.608 99.192 ;
     RECT  16.561 100.848 18.608 102.408 ;
     RECT  16.561 104.064 18.608 104.088 ;
     RECT  16.957 105.648 18.608 105.672 ;
     RECT  14.681 109.2 18.608 109.224 ;
     RECT  18.608 2.148 18.712 213.852 ;
     RECT  18.712 2.418 18.904 213.582 ;
     RECT  18.904 99.024 19.001 99.192 ;
     RECT  18.904 95.616 22.421 96.216 ;
     RECT  22.421 95.616 22.853 95.736 ;
     RECT  22.853 95.712 23.497 95.736 ;
     RECT  18.904 24.624 24.008 28.488 ;
     RECT  18.904 29.472 24.008 29.496 ;
     RECT  18.904 30.864 24.008 30.888 ;
     RECT  18.904 32.784 24.008 33.576 ;
     RECT  18.904 35.424 24.008 35.448 ;
     RECT  18.904 37.872 24.008 37.896 ;
     RECT  18.904 54.576 24.008 54.6 ;
     RECT  18.904 85.104 24.008 85.128 ;
     RECT  18.904 87.264 24.008 88.344 ;
     RECT  23.497 95.712 24.008 95.784 ;
     RECT  19.001 99.024 24.008 99.048 ;
     RECT  18.904 100.752 24.008 101.4 ;
     RECT  18.904 104.064 24.008 104.088 ;
     RECT  18.904 105.648 24.008 105.672 ;
     RECT  18.904 109.2 24.008 109.224 ;
     RECT  24.008 2.148 24.112 213.852 ;
     RECT  24.112 2.418 24.304 213.582 ;
     RECT  24.304 95.712 25.589 95.736 ;
     RECT  24.304 32.784 25.909 33.576 ;
     RECT  25.909 95.184 25.993 95.208 ;
     RECT  24.304 87.264 26.813 88.344 ;
     RECT  24.304 24.624 29.408 28.488 ;
     RECT  24.304 29.472 29.408 29.496 ;
     RECT  24.304 30.864 29.408 30.888 ;
     RECT  25.909 31.968 29.408 33.576 ;
     RECT  24.304 35.424 29.408 35.448 ;
     RECT  24.304 37.872 29.408 37.896 ;
     RECT  24.304 54.576 29.408 54.6 ;
     RECT  24.304 85.104 29.408 85.128 ;
     RECT  26.813 87.264 29.408 88.2 ;
     RECT  24.304 99.024 29.408 99.048 ;
     RECT  24.304 100.752 29.408 101.4 ;
     RECT  24.304 104.064 29.408 104.088 ;
     RECT  24.304 105.648 29.408 105.672 ;
     RECT  24.304 109.2 29.408 109.224 ;
     RECT  29.408 2.148 29.512 213.852 ;
     RECT  29.512 2.418 29.704 213.582 ;
     RECT  29.704 101.376 30.413 101.4 ;
     RECT  29.704 87.216 30.515 88.2 ;
     RECT  30.515 88.032 30.665 88.2 ;
     RECT  30.665 88.08 30.989 88.2 ;
     RECT  31.381 100.752 31.489 100.776 ;
     RECT  29.704 99.024 32.789 99.048 ;
     RECT  29.704 30.864 33.877 30.888 ;
     RECT  29.704 31.968 33.877 33.576 ;
     RECT  29.704 24.624 34.808 28.488 ;
     RECT  29.704 29.472 34.808 29.496 ;
     RECT  33.877 30.864 34.808 33.576 ;
     RECT  29.704 35.424 34.808 35.448 ;
     RECT  29.704 37.872 34.808 37.896 ;
     RECT  29.704 54.576 34.808 54.6 ;
     RECT  29.704 70.8 34.808 70.824 ;
     RECT  29.704 85.104 34.808 85.128 ;
     RECT  33.865 98.64 34.808 98.664 ;
     RECT  31.489 100.752 34.808 101.352 ;
     RECT  29.704 104.064 34.808 104.088 ;
     RECT  29.704 105.648 34.808 105.672 ;
     RECT  29.704 109.2 34.808 109.224 ;
     RECT  34.808 2.148 34.912 213.852 ;
     RECT  34.912 2.418 35.104 213.582 ;
     RECT  35.104 105.648 35.741 105.672 ;
     RECT  35.104 24.624 40.208 28.488 ;
     RECT  35.104 29.472 40.208 29.496 ;
     RECT  35.104 30.864 40.208 33.576 ;
     RECT  35.104 35.424 40.208 35.448 ;
     RECT  35.104 37.872 40.208 37.896 ;
     RECT  35.104 54.576 40.208 54.6 ;
     RECT  35.104 70.8 40.208 70.824 ;
     RECT  35.104 85.104 40.208 85.128 ;
     RECT  35.104 100.752 40.208 101.352 ;
     RECT  35.104 104.064 40.208 104.088 ;
     RECT  36.817 105.888 40.208 105.912 ;
     RECT  35.104 109.2 40.208 109.224 ;
     RECT  40.208 2.148 40.312 213.852 ;
     RECT  40.312 2.418 40.504 213.582 ;
     RECT  40.504 24.624 45.608 28.488 ;
     RECT  40.504 29.472 45.608 29.496 ;
     RECT  40.504 30.864 45.608 33.576 ;
     RECT  40.504 35.424 45.608 35.448 ;
     RECT  40.504 37.872 45.608 37.896 ;
     RECT  40.504 54.576 45.608 54.6 ;
     RECT  40.504 70.8 45.608 70.824 ;
     RECT  40.504 85.104 45.608 85.128 ;
     RECT  40.504 100.752 45.608 101.352 ;
     RECT  40.504 104.064 45.608 104.088 ;
     RECT  40.504 105.888 45.608 105.912 ;
     RECT  40.504 109.2 45.608 109.224 ;
     RECT  45.608 2.148 45.712 213.852 ;
     RECT  45.712 2.418 45.904 213.582 ;
     RECT  45.904 70.8 46.145 70.92 ;
     RECT  45.904 24.624 51.008 28.488 ;
     RECT  45.904 29.472 51.008 29.496 ;
     RECT  45.904 30.864 51.008 33.576 ;
     RECT  45.904 35.424 51.008 35.448 ;
     RECT  45.904 37.872 51.008 37.896 ;
     RECT  45.904 54.576 51.008 54.6 ;
     RECT  46.145 70.896 51.008 70.92 ;
     RECT  45.904 85.104 51.008 85.128 ;
     RECT  45.904 100.752 51.008 101.352 ;
     RECT  45.904 104.064 51.008 104.088 ;
     RECT  45.904 105.888 51.008 105.912 ;
     RECT  45.904 109.2 51.008 109.224 ;
     RECT  51.008 2.148 51.112 213.852 ;
     RECT  51.112 2.418 51.304 213.582 ;
     RECT  51.304 24.624 56.408 28.488 ;
     RECT  51.304 29.472 56.408 29.496 ;
     RECT  51.304 30.864 56.408 33.576 ;
     RECT  51.304 35.424 56.408 35.448 ;
     RECT  51.304 37.872 56.408 37.896 ;
     RECT  51.304 54.576 56.408 54.6 ;
     RECT  51.304 70.896 56.408 70.92 ;
     RECT  51.304 85.104 56.408 85.128 ;
     RECT  51.304 100.752 56.408 101.352 ;
     RECT  51.304 104.064 56.408 104.088 ;
     RECT  51.304 105.888 56.408 105.912 ;
     RECT  51.304 109.2 56.408 109.224 ;
     RECT  56.408 2.148 56.512 213.852 ;
     RECT  56.512 2.418 56.704 213.582 ;
     RECT  61.513 78.48 61.621 78.504 ;
     RECT  56.704 24.624 61.808 28.488 ;
     RECT  56.704 29.472 61.808 29.496 ;
     RECT  56.704 30.864 61.808 33.576 ;
     RECT  56.704 35.424 61.808 35.448 ;
     RECT  56.704 37.872 61.808 37.896 ;
     RECT  61.621 51.696 61.808 51.72 ;
     RECT  56.704 54.576 61.808 54.6 ;
     RECT  56.704 70.896 61.808 70.92 ;
     RECT  61.621 78.384 61.808 78.504 ;
     RECT  56.704 85.104 61.808 85.128 ;
     RECT  56.704 100.752 61.808 101.352 ;
     RECT  56.704 104.064 61.808 104.088 ;
     RECT  56.704 105.888 61.808 105.912 ;
     RECT  56.704 109.2 61.808 109.224 ;
     RECT  61.808 2.148 61.912 213.852 ;
     RECT  61.912 2.418 62.104 213.582 ;
     RECT  62.104 109.2 65.077 109.224 ;
     RECT  62.104 78.48 65.267 78.504 ;
     RECT  62.104 24.624 67.208 28.488 ;
     RECT  62.104 29.472 67.208 29.496 ;
     RECT  62.104 30.864 67.208 33.576 ;
     RECT  62.104 35.424 67.208 35.448 ;
     RECT  62.104 37.872 67.208 37.896 ;
     RECT  62.104 51.696 67.208 51.72 ;
     RECT  62.104 54.576 67.208 54.6 ;
     RECT  62.104 85.104 67.208 85.128 ;
     RECT  65.221 92.16 67.208 92.184 ;
     RECT  62.104 100.752 67.208 101.352 ;
     RECT  62.104 104.064 67.208 104.088 ;
     RECT  62.104 105.888 67.208 105.912 ;
     RECT  65.077 109.2 67.208 109.992 ;
     RECT  67.208 2.148 67.312 213.852 ;
     RECT  67.312 2.418 67.504 213.582 ;
     RECT  67.504 30.864 68.821 33.576 ;
     RECT  67.504 24.624 72.608 28.488 ;
     RECT  67.504 29.472 72.608 29.496 ;
     RECT  68.821 30.864 72.608 33.624 ;
     RECT  67.504 35.424 72.608 35.448 ;
     RECT  67.504 37.872 72.608 37.896 ;
     RECT  67.504 51.696 72.608 51.72 ;
     RECT  67.504 54.576 72.608 54.6 ;
     RECT  67.504 85.104 72.608 85.128 ;
     RECT  67.504 92.16 72.608 92.184 ;
     RECT  67.504 100.752 72.608 101.352 ;
     RECT  67.504 104.064 72.608 104.088 ;
     RECT  67.504 105.888 72.608 105.912 ;
     RECT  67.504 109.2 72.608 109.992 ;
     RECT  72.608 2.148 72.712 213.852 ;
     RECT  72.712 2.418 72.904 213.582 ;
     RECT  72.904 51.696 75.269 51.72 ;
     RECT  72.904 35.424 76.309 35.448 ;
     RECT  76.309 35.328 76.393 35.448 ;
     RECT  76.393 35.424 76.673 35.448 ;
     RECT  72.904 24.624 78.008 28.488 ;
     RECT  72.904 29.472 78.008 29.496 ;
     RECT  72.904 30.864 78.008 33.624 ;
     RECT  72.904 37.872 78.008 37.896 ;
     RECT  76.777 51.648 78.008 51.672 ;
     RECT  72.904 54.576 78.008 54.6 ;
     RECT  72.904 85.104 78.008 85.128 ;
     RECT  72.904 92.16 78.008 92.184 ;
     RECT  72.904 100.752 78.008 101.352 ;
     RECT  72.904 104.064 78.008 104.088 ;
     RECT  72.904 105.888 78.008 105.912 ;
     RECT  72.904 109.2 78.008 109.992 ;
     RECT  78.008 2.148 78.112 213.852 ;
     RECT  78.112 2.418 78.304 213.582 ;
     RECT  78.304 37.632 78.419 37.896 ;
     RECT  78.419 37.872 78.653 37.896 ;
     RECT  78.304 92.16 82.397 92.184 ;
     RECT  78.304 24.624 83.408 28.488 ;
     RECT  78.304 29.472 83.408 29.544 ;
     RECT  78.304 30.864 83.408 33.624 ;
     RECT  78.304 51.648 83.408 51.672 ;
     RECT  78.304 54.576 83.408 54.6 ;
     RECT  78.304 85.104 83.408 85.128 ;
     RECT  78.304 100.752 83.408 101.352 ;
     RECT  78.304 104.064 83.408 104.088 ;
     RECT  78.304 105.888 83.408 105.912 ;
     RECT  78.304 109.2 83.408 109.992 ;
     RECT  83.408 2.148 83.512 213.852 ;
     RECT  83.512 2.418 83.704 213.582 ;
     RECT  83.704 24.624 85.021 28.488 ;
     RECT  83.704 29.472 85.021 29.544 ;
     RECT  85.772 11.136 85.813 11.16 ;
     RECT  85.813 10.224 85.859 12.024 ;
     RECT  85.859 10.224 85.925 10.248 ;
     RECT  85.813 18.432 86.099 18.456 ;
     RECT  85.859 12 86.209 12.024 ;
     RECT  86.053 19.584 86.249 19.608 ;
     RECT  86.053 20.832 86.285 20.856 ;
     RECT  86.209 12 86.393 12.984 ;
     RECT  83.704 109.2 86.425 109.992 ;
     RECT  85.021 24.624 86.501 29.544 ;
     RECT  86.425 108.288 86.509 109.992 ;
     RECT  86.053 16.512 86.821 16.536 ;
     RECT  86.821 15.792 86.897 16.536 ;
     RECT  86.897 15.792 86.908 15.816 ;
     RECT  86.821 10.272 86.965 10.824 ;
     RECT  87.217 16.8 87.289 16.824 ;
     RECT  86.749 20.88 87.289 20.904 ;
     RECT  87.289 16.8 87.325 16.872 ;
     RECT  86.965 10.272 87.361 10.872 ;
     RECT  86.605 7.344 87.397 7.368 ;
     RECT  87.361 9.984 87.433 10.872 ;
     RECT  87.325 16.8 87.433 16.968 ;
     RECT  86.393 12.528 87.469 12.984 ;
     RECT  86.785 22.272 87.721 22.296 ;
     RECT  87.433 9.792 87.731 10.872 ;
     RECT  87.397 6.912 87.781 7.368 ;
     RECT  87.433 16.8 87.788 17.112 ;
     RECT  87.781 6.672 87.827 7.368 ;
     RECT  87.788 11.28 87.829 11.304 ;
     RECT  87.469 12.528 87.829 13.368 ;
     RECT  87.793 19.392 87.865 19.416 ;
     RECT  87.289 20.88 87.865 21 ;
     RECT  87.865 19.392 87.937 21 ;
     RECT  87.829 11.28 87.973 13.368 ;
     RECT  83.704 30.864 88.021 33.624 ;
     RECT  87.973 11.28 88.261 14.136 ;
     RECT  87.788 16.8 88.268 17.448 ;
     RECT  87.937 19.392 88.297 21.096 ;
     RECT  87.721 22.176 88.297 22.296 ;
     RECT  88.261 11.28 88.309 14.424 ;
     RECT  88.021 30.864 88.46 34.152 ;
     RECT  88.268 16.272 88.513 17.448 ;
     RECT  88.513 16.272 88.621 18.216 ;
     RECT  88.297 19.392 88.621 22.296 ;
     RECT  88.309 11.28 88.657 15.24 ;
     RECT  88.621 16.272 88.693 22.296 ;
     RECT  87.827 6.672 88.808 6.888 ;
     RECT  86.569 8.784 88.808 8.808 ;
     RECT  87.731 9.792 88.808 10.296 ;
     RECT  88.657 11.28 88.808 15.288 ;
     RECT  88.693 16.272 88.808 22.824 ;
     RECT  86.677 23.952 88.808 23.976 ;
     RECT  86.501 25.152 88.808 29.544 ;
     RECT  88.46 30.576 88.808 34.152 ;
     RECT  83.704 51.648 88.808 51.672 ;
     RECT  83.704 54.576 88.808 54.6 ;
     RECT  83.704 85.104 88.808 85.128 ;
     RECT  83.704 91.92 88.808 91.944 ;
     RECT  83.704 100.752 88.808 101.352 ;
     RECT  83.704 104.064 88.808 104.088 ;
     RECT  83.704 105.888 88.808 105.912 ;
     RECT  86.509 109.2 88.808 109.992 ;
     RECT  86.437 118.032 88.808 118.056 ;
     RECT  88.808 2.148 88.912 213.852 ;
     RECT  88.912 2.418 89.104 213.582 ;
     RECT  89.104 23.52 89.237 25.944 ;
     RECT  89.104 18.816 89.273 21.816 ;
     RECT  89.273 18.816 89.525 21.288 ;
     RECT  89.104 4.512 89.555 4.536 ;
     RECT  89.104 5.568 89.597 6.312 ;
     RECT  89.104 15.216 89.597 15.288 ;
     RECT  89.104 9.792 89.741 13.608 ;
     RECT  89.597 15.216 90.029 15.24 ;
     RECT  89.597 6.144 90.085 6.312 ;
     RECT  90.085 6.144 90.133 7.176 ;
     RECT  89.104 8.496 90.133 8.52 ;
     RECT  90.133 6.144 90.14 8.52 ;
     RECT  89.741 9.792 90.14 13.416 ;
     RECT  90.14 6.144 90.173 13.416 ;
     RECT  89.525 19.248 90.179 21.288 ;
     RECT  89.104 16.656 90.205 16.68 ;
     RECT  90.173 7.92 90.227 13.416 ;
     RECT  89.104 27.36 90.305 34.152 ;
     RECT  89.104 91.92 90.323 91.944 ;
     RECT  90.277 63.36 90.325 63.384 ;
     RECT  90.305 27.36 90.389 34.248 ;
     RECT  90.313 59.808 90.397 59.832 ;
     RECT  90.325 62.736 90.467 63.384 ;
     RECT  90.205 16.656 90.493 17.16 ;
     RECT  89.237 23.52 90.493 25.848 ;
     RECT  90.493 23.52 90.565 26.376 ;
     RECT  90.389 27.36 90.565 33.48 ;
     RECT  90.179 19.296 90.569 21.288 ;
     RECT  90.227 7.92 90.611 8.52 ;
     RECT  90.569 19.296 90.677 19.32 ;
     RECT  90.227 9.792 90.713 13.416 ;
     RECT  90.173 6.144 90.785 6.696 ;
     RECT  90.565 23.52 90.857 33.48 ;
     RECT  90.493 16.464 90.893 17.16 ;
     RECT  90.857 23.52 90.929 25.8 ;
     RECT  89.104 54.576 90.961 54.6 ;
     RECT  90.857 26.832 90.965 33.48 ;
     RECT  90.961 54.144 91.045 54.6 ;
     RECT  90.965 26.832 91.073 30.072 ;
     RECT  90.713 9.792 91.181 11.544 ;
     RECT  90.713 12.816 91.217 13.416 ;
     RECT  91.133 52.464 91.217 52.488 ;
     RECT  90.611 7.92 91.249 8.472 ;
     RECT  91.045 54.576 91.289 54.6 ;
     RECT  91.181 11.52 91.325 11.544 ;
     RECT  90.785 6.144 91.357 6.168 ;
     RECT  90.569 20.496 91.469 21.288 ;
     RECT  90.965 31.392 91.573 33.48 ;
     RECT  91.217 13.104 91.681 13.416 ;
     RECT  91.285 14.736 91.681 14.76 ;
     RECT  91.357 5.328 91.753 6.168 ;
     RECT  91.249 7.344 91.753 8.472 ;
     RECT  91.469 20.496 91.753 20.856 ;
     RECT  91.681 13.104 92.077 14.76 ;
     RECT  91.753 5.328 92.153 8.472 ;
     RECT  91.573 31.392 92.185 34.104 ;
     RECT  92.185 31.296 92.225 34.104 ;
     RECT  89.104 109.2 92.261 109.992 ;
     RECT  92.153 7.44 92.293 8.472 ;
     RECT  91.181 9.792 92.293 10.248 ;
     RECT  92.077 13.104 92.365 14.856 ;
     RECT  91.753 20.448 92.365 20.856 ;
     RECT  91.073 26.832 92.365 29.544 ;
     RECT  92.365 26.832 92.401 29.88 ;
     RECT  92.225 31.296 92.401 32.76 ;
     RECT  91.141 49.392 92.401 49.416 ;
     RECT  92.401 49.056 92.441 49.416 ;
     RECT  90.893 16.464 92.473 17.064 ;
     RECT  92.293 7.44 92.485 10.248 ;
     RECT  92.257 11.424 92.485 11.448 ;
     RECT  92.365 13.056 92.545 14.856 ;
     RECT  92.437 2.304 92.617 2.328 ;
     RECT  91.177 22.752 92.653 22.776 ;
     RECT  90.929 24.048 92.653 25.8 ;
     RECT  92.401 26.832 92.657 32.76 ;
     RECT  92.365 19.872 92.693 20.856 ;
     RECT  92.657 26.832 92.693 30.84 ;
     RECT  92.485 7.44 92.725 11.448 ;
     RECT  92.441 49.056 92.725 49.08 ;
     RECT  89.104 118.032 92.725 118.056 ;
     RECT  92.473 15.984 92.773 17.064 ;
     RECT  92.725 49.008 92.809 49.08 ;
     RECT  92.725 52.992 92.809 53.016 ;
     RECT  92.657 31.968 92.819 32.76 ;
     RECT  92.725 7.44 92.833 11.544 ;
     RECT  92.653 22.752 92.833 25.8 ;
     RECT  92.693 26.832 92.833 30.696 ;
     RECT  92.773 15.984 92.869 17.448 ;
     RECT  92.153 5.328 92.905 6.312 ;
     RECT  92.545 12.912 92.905 14.856 ;
     RECT  92.693 19.968 92.915 20.856 ;
     RECT  92.905 5.232 92.941 6.312 ;
     RECT  92.833 7.44 92.941 11.592 ;
     RECT  92.905 12.768 92.941 14.856 ;
     RECT  92.915 20.448 92.945 20.856 ;
     RECT  92.833 22.752 92.945 30.696 ;
     RECT  92.005 18.864 92.972 18.888 ;
     RECT  92.545 0.528 93.013 0.552 ;
     RECT  92.869 15.984 93.013 17.64 ;
     RECT  92.972 18.768 93.013 18.888 ;
     RECT  93.013 15.984 93.017 18.888 ;
     RECT  92.941 7.44 93.059 14.856 ;
     RECT  93.059 7.44 93.089 14.76 ;
     RECT  93.013 0.528 93.097 0.6 ;
     RECT  93.089 13.152 93.161 14.76 ;
     RECT  93.017 15.984 93.193 18.792 ;
     RECT  92.617 2.304 93.205 2.376 ;
     RECT  92.945 23.856 93.233 30.696 ;
     RECT  92.945 20.832 93.253 20.856 ;
     RECT  93.253 20.832 93.337 21.672 ;
     RECT  92.945 22.752 93.337 22.776 ;
     RECT  92.941 3.408 93.365 3.432 ;
     RECT  93.205 1.728 93.445 2.376 ;
     RECT  93.365 3.408 93.445 3.672 ;
     RECT  93.445 1.728 93.589 3.672 ;
     RECT  92.941 5.136 93.589 6.312 ;
     RECT  93.233 25.632 93.661 30.696 ;
     RECT  93.089 7.44 93.733 12.072 ;
     RECT  92.819 31.968 93.877 32.472 ;
     RECT  93.877 31.92 93.913 32.472 ;
     RECT  92.225 34.08 93.913 34.104 ;
     RECT  93.097 0.528 94.049 0.552 ;
     RECT  93.733 7.296 94.057 12.072 ;
     RECT  93.193 15.84 94.069 18.792 ;
     RECT  93.337 20.832 94.069 22.776 ;
     RECT  94.049 0.144 94.165 0.552 ;
     RECT  92.725 117.984 94.165 118.056 ;
     RECT  93.589 1.728 94.208 6.312 ;
     RECT  94.057 7.296 94.208 12.264 ;
     RECT  93.161 13.872 94.208 14.76 ;
     RECT  94.069 15.84 94.208 18.984 ;
     RECT  94.069 20.064 94.208 22.776 ;
     RECT  93.233 23.856 94.208 24.6 ;
     RECT  93.661 25.632 94.208 30.84 ;
     RECT  93.913 31.872 94.208 34.104 ;
     RECT  92.809 49.056 94.208 49.08 ;
     RECT  91.861 59.808 94.208 59.832 ;
     RECT  90.467 63.216 94.208 63.24 ;
     RECT  89.104 85.104 94.208 85.128 ;
     RECT  89.104 100.752 94.208 101.352 ;
     RECT  89.104 104.064 94.208 104.088 ;
     RECT  89.104 105.888 94.208 105.912 ;
     RECT  92.261 109.968 94.208 109.992 ;
     RECT  94.165 117.984 94.208 118.152 ;
     RECT  94.208 1.728 94.312 213.852 ;
     RECT  94.312 1.728 94.357 213.582 ;
     RECT  94.357 1.68 94.504 213.582 ;
     RECT  94.165 0.096 94.565 0.552 ;
     RECT  94.504 7.872 94.565 13.512 ;
     RECT  94.565 0.096 94.595 0.168 ;
     RECT  94.504 1.68 94.601 6.888 ;
     RECT  94.504 14.64 94.637 30.84 ;
     RECT  94.565 7.872 94.643 11.928 ;
     RECT  94.637 14.64 94.889 30.696 ;
     RECT  94.504 49.056 94.925 49.08 ;
     RECT  94.889 23.376 94.931 30.696 ;
     RECT  94.601 1.92 94.997 6.888 ;
     RECT  94.997 6.864 95.033 6.888 ;
     RECT  94.931 23.376 95.033 30.264 ;
     RECT  94.504 31.92 95.141 32.472 ;
     RECT  94.565 13.104 95.213 13.512 ;
     RECT  94.595 0.144 95.219 0.168 ;
     RECT  95.033 28.224 95.401 30.264 ;
     RECT  94.997 1.92 95.597 5.736 ;
     RECT  94.889 14.64 95.651 21.768 ;
     RECT  95.033 23.376 95.651 27.096 ;
     RECT  95.651 24.384 95.689 24.648 ;
     RECT  94.643 7.872 95.717 11.448 ;
     RECT  95.777 0.096 95.861 0.12 ;
     RECT  95.651 23.376 96.077 23.4 ;
     RECT  95.401 28.224 96.077 29.832 ;
     RECT  95.213 13.104 96.109 13.416 ;
     RECT  95.141 31.968 96.181 32.472 ;
     RECT  96.109 12.528 96.428 13.416 ;
     RECT  95.651 14.64 96.428 20.856 ;
     RECT  96.181 31.92 96.481 32.472 ;
     RECT  95.717 7.872 96.509 11.4 ;
     RECT  96.509 7.968 96.685 11.4 ;
     RECT  96.428 12.528 96.685 20.856 ;
     RECT  95.651 25.68 96.721 27.096 ;
     RECT  96.077 28.224 96.721 29.016 ;
     RECT  96.685 7.968 96.757 20.856 ;
     RECT  95.597 1.728 96.865 5.736 ;
     RECT  95.689 24.384 96.865 24.408 ;
     RECT  96.865 23.664 96.901 24.408 ;
     RECT  96.757 7.968 96.941 21.144 ;
     RECT  96.805 0.144 96.997 0.168 ;
     RECT  96.941 18.096 97.045 21.144 ;
     RECT  96.361 22.272 97.045 22.296 ;
     RECT  96.901 23.664 97.045 24.648 ;
     RECT  96.997 0.144 97.085 0.264 ;
     RECT  97.045 18.096 97.091 22.296 ;
     RECT  97.085 0.144 97.129 0.168 ;
     RECT  94.504 118.128 97.187 118.152 ;
     RECT  97.091 21.936 97.265 22.296 ;
     RECT  97.265 22.272 97.297 22.296 ;
     RECT  97.045 23.376 97.297 24.648 ;
     RECT  96.941 7.968 97.301 17.064 ;
     RECT  97.141 122.64 97.373 123.288 ;
     RECT  97.301 8.016 97.409 17.064 ;
     RECT  97.297 22.272 97.517 24.648 ;
     RECT  97.091 18.096 97.561 20.856 ;
     RECT  97.409 8.016 97.589 15.048 ;
     RECT  94.504 34.08 97.717 34.104 ;
     RECT  96.481 31.968 97.763 32.472 ;
     RECT  94.504 59.808 97.763 59.832 ;
     RECT  97.717 34.08 97.805 35.064 ;
     RECT  95.533 62.736 97.811 62.76 ;
     RECT  96.865 1.728 97.841 6.312 ;
     RECT  96.721 25.68 97.841 29.016 ;
     RECT  97.373 122.64 97.841 122.664 ;
     RECT  97.517 23.376 97.949 24.648 ;
     RECT  94.504 40.224 97.964 40.248 ;
     RECT  97.949 23.712 97.981 24.648 ;
     RECT  97.841 25.68 97.981 27.72 ;
     RECT  97.589 9.36 97.985 15.048 ;
     RECT  97.985 9.36 98.051 12.552 ;
     RECT  97.964 40.224 98.051 40.44 ;
     RECT  97.589 8.016 98.273 8.328 ;
     RECT  98.051 40.224 98.309 40.296 ;
     RECT  97.561 20.592 98.341 20.856 ;
     RECT  97.517 22.272 98.492 22.296 ;
     RECT  98.492 22.272 98.579 22.536 ;
     RECT  98.273 8.304 98.593 8.328 ;
     RECT  98.051 9.36 98.593 12.12 ;
     RECT  97.561 18.096 98.593 19.512 ;
     RECT  98.593 18.096 98.809 19.56 ;
     RECT  98.341 20.592 98.809 20.904 ;
     RECT  98.579 22.272 98.828 22.296 ;
     RECT  97.981 23.712 98.869 27.72 ;
     RECT  97.841 28.704 98.869 29.016 ;
     RECT  94.504 104.064 98.876 104.088 ;
     RECT  97.409 16.08 99.133 17.064 ;
     RECT  97.841 1.728 99.205 5.784 ;
     RECT  98.333 6.864 99.205 6.888 ;
     RECT  99.133 16.08 99.308 17.112 ;
     RECT  98.809 18.096 99.308 20.904 ;
     RECT  99.301 0.24 99.397 0.264 ;
     RECT  99.397 0.192 99.493 0.264 ;
     RECT  99.493 0.192 99.541 0.312 ;
     RECT  99.205 1.728 99.608 6.888 ;
     RECT  98.593 8.304 99.608 12.12 ;
     RECT  97.985 13.968 99.608 15.048 ;
     RECT  99.308 16.08 99.608 20.904 ;
     RECT  98.828 21.888 99.608 22.296 ;
     RECT  98.869 23.712 99.608 29.016 ;
     RECT  97.763 31.968 99.608 31.992 ;
     RECT  97.805 34.08 99.608 34.488 ;
     RECT  97.717 37.872 99.608 37.896 ;
     RECT  98.309 40.272 99.608 40.296 ;
     RECT  97.765 47.28 99.608 47.304 ;
     RECT  98.876 104.064 99.608 104.232 ;
     RECT  94.504 109.968 99.608 109.992 ;
     RECT  98.917 121.968 99.608 121.992 ;
     RECT  99.608 1.728 99.712 213.852 ;
     RECT  99.541 0.096 99.829 0.312 ;
     RECT  99.712 1.728 99.904 213.582 ;
     RECT  99.829 0.096 99.925 0.36 ;
     RECT  99.904 12.24 100.019 16.104 ;
     RECT  99.925 0.096 100.115 0.456 ;
     RECT  100.019 12.24 100.145 13.608 ;
     RECT  100.115 0.096 100.211 0.216 ;
     RECT  100.019 14.832 100.253 16.104 ;
     RECT  99.904 17.088 100.361 17.112 ;
     RECT  99.904 18.384 100.613 29.016 ;
     RECT  100.613 18.384 100.901 28.536 ;
     RECT  100.145 12.24 100.933 12.456 ;
     RECT  100.253 15.024 100.937 16.104 ;
     RECT  100.145 13.584 101.045 13.608 ;
     RECT  99.904 34.08 101.171 34.488 ;
     RECT  100.937 15.024 101.257 15.48 ;
     RECT  99.904 1.728 101.357 6.264 ;
     RECT  101.257 14.976 101.401 15.48 ;
     RECT  101.357 1.728 101.429 6.312 ;
     RECT  99.904 37.872 101.473 37.896 ;
     RECT  99.904 7.968 101.509 10.968 ;
     RECT  100.901 18.72 101.513 28.536 ;
     RECT  101.513 22.176 101.585 28.536 ;
     RECT  101.473 37.488 101.747 38.424 ;
     RECT  101.509 7.44 101.833 10.968 ;
     RECT  100.933 11.952 101.833 12.456 ;
     RECT  101.833 7.44 101.873 12.456 ;
     RECT  100.211 0.096 101.909 0.168 ;
     RECT  101.873 7.44 101.909 11.976 ;
     RECT  101.585 22.224 102.017 28.536 ;
     RECT  101.401 14.208 102.044 15.48 ;
     RECT  102.044 14.208 102.131 15.624 ;
     RECT  101.909 7.44 102.193 9.768 ;
     RECT  102.157 16.992 102.229 17.016 ;
     RECT  102.085 13.104 102.233 13.128 ;
     RECT  101.429 1.728 102.373 6.36 ;
     RECT  102.193 7.392 102.373 9.768 ;
     RECT  102.301 13.152 102.373 13.176 ;
     RECT  102.131 14.208 102.373 15.528 ;
     RECT  102.373 13.152 102.377 15.528 ;
     RECT  99.904 31.968 102.449 31.992 ;
     RECT  102.229 16.992 102.553 17.064 ;
     RECT  102.373 1.728 102.557 9.768 ;
     RECT  101.513 18.72 102.613 20.904 ;
     RECT  102.553 16.656 102.697 17.064 ;
     RECT  101.545 30.24 102.841 30.264 ;
     RECT  101.909 10.944 102.941 11.976 ;
     RECT  102.841 30.192 102.949 30.264 ;
     RECT  102.557 7.392 103.093 9.768 ;
     RECT  102.941 10.848 103.093 11.976 ;
     RECT  101.909 0.144 103.138 0.168 ;
     RECT  103.093 7.392 103.141 11.976 ;
     RECT  102.613 18.24 103.165 20.904 ;
     RECT  102.017 23.088 103.165 28.536 ;
     RECT  102.949 30.192 103.165 30.696 ;
     RECT  102.697 16.656 103.201 17.16 ;
     RECT  103.165 18.24 103.201 22.104 ;
     RECT  103.141 7.392 103.205 12.024 ;
     RECT  103.205 7.392 103.277 7.992 ;
     RECT  103.205 9.024 103.301 12.024 ;
     RECT  103.301 9.024 103.345 12.072 ;
     RECT  102.377 13.152 103.345 15.48 ;
     RECT  102.557 1.728 103.421 6.312 ;
     RECT  99.904 40.272 103.421 40.296 ;
     RECT  103.138 0.096 103.427 0.216 ;
     RECT  103.427 0.192 103.475 0.216 ;
     RECT  103.345 9.024 103.525 15.48 ;
     RECT  103.165 23.088 103.529 30.696 ;
     RECT  103.201 16.656 103.597 22.104 ;
     RECT  103.529 23.088 103.597 29.256 ;
     RECT  103.525 9.024 103.637 15.576 ;
     RECT  103.597 16.656 103.709 29.256 ;
     RECT  103.709 16.752 103.763 29.256 ;
     RECT  103.421 2.208 103.813 6.312 ;
     RECT  103.529 30.24 103.993 30.696 ;
     RECT  101.171 34.08 104.003 34.104 ;
     RECT  103.813 2.208 104.165 6.36 ;
     RECT  104.165 2.208 104.389 6.6 ;
     RECT  104.389 2.064 104.533 6.6 ;
     RECT  103.993 30.24 104.641 30.84 ;
     RECT  103.489 31.92 104.641 31.944 ;
     RECT  104.293 0.576 104.725 0.6 ;
     RECT  103.637 9.024 104.749 15.336 ;
     RECT  103.763 16.752 104.749 21.528 ;
     RECT  104.533 1.728 104.773 6.6 ;
     RECT  103.277 7.776 104.773 7.8 ;
     RECT  104.725 0.096 104.825 0.6 ;
     RECT  103.763 23.088 104.849 29.256 ;
     RECT  104.641 30.24 104.849 31.944 ;
     RECT  104.749 9.024 104.869 21.96 ;
     RECT  104.849 23.088 104.869 31.944 ;
     RECT  104.825 0.144 104.963 0.6 ;
     RECT  104.773 1.728 105.008 7.8 ;
     RECT  104.869 8.88 105.008 31.944 ;
     RECT  101.747 38.4 105.008 38.424 ;
     RECT  99.904 47.28 105.008 47.304 ;
     RECT  99.904 109.968 105.008 109.992 ;
     RECT  105.008 1.728 105.112 213.852 ;
     RECT  105.112 1.728 105.304 213.582 ;
     RECT  105.304 7.392 105.437 20.184 ;
     RECT  105.437 7.392 105.443 20.04 ;
     RECT  105.304 38.4 105.443 38.424 ;
     RECT  105.304 21.408 105.509 31.944 ;
     RECT  105.443 7.488 105.545 20.04 ;
     RECT  104.963 0.144 105.58 0.408 ;
     RECT  105.545 7.872 105.923 20.04 ;
     RECT  105.304 1.728 106.049 6.312 ;
     RECT  105.923 7.872 106.163 12.024 ;
     RECT  105.509 21.408 106.265 23.592 ;
     RECT  105.923 13.056 106.301 20.04 ;
     RECT  106.163 8.448 106.337 12.024 ;
     RECT  106.049 1.728 106.357 5.88 ;
     RECT  106.357 1.152 106.553 5.88 ;
     RECT  105.509 24.672 106.595 29.064 ;
     RECT  106.595 24.672 106.625 27.24 ;
     RECT  106.301 13.632 106.739 20.04 ;
     RECT  106.739 17.664 106.945 20.04 ;
     RECT  106.265 21.408 106.945 21.528 ;
     RECT  105.509 30.576 106.985 31.944 ;
     RECT  106.739 13.632 107.201 16.68 ;
     RECT  106.945 17.664 107.201 21.528 ;
     RECT  106.595 28.224 107.201 29.064 ;
     RECT  106.985 30.576 107.201 31.848 ;
     RECT  106.265 22.608 107.269 23.592 ;
     RECT  106.625 24.672 107.269 26.808 ;
     RECT  106.337 9.12 107.273 12.024 ;
     RECT  107.269 22.608 107.353 26.808 ;
     RECT  107.201 18.144 107.413 21.528 ;
     RECT  107.353 22.608 107.413 23.592 ;
     RECT  107.413 18.144 107.417 23.592 ;
     RECT  107.201 28.416 107.417 29.064 ;
     RECT  107.273 9.168 107.561 12.024 ;
     RECT  107.413 214.32 107.737 214.344 ;
     RECT  105.58 0.144 107.747 0.168 ;
     RECT  107.201 13.632 107.809 14.76 ;
     RECT  107.201 15.744 107.813 16.68 ;
     RECT  107.353 24.624 107.813 26.808 ;
     RECT  105.304 109.968 107.843 109.992 ;
     RECT  107.813 15.84 107.917 16.68 ;
     RECT  107.737 213.696 107.917 214.344 ;
     RECT  107.917 15.84 107.932 17.16 ;
     RECT  107.917 213.648 107.939 214.344 ;
     RECT  107.939 213.648 108.035 213.72 ;
     RECT  106.553 1.728 108.101 5.88 ;
     RECT  108.035 213.648 108.131 213.672 ;
     RECT  107.561 10.272 108.209 12.024 ;
     RECT  107.813 24.672 108.209 26.808 ;
     RECT  108.14 213.168 108.227 213.192 ;
     RECT  107.201 30.576 108.241 30.744 ;
     RECT  107.201 31.824 108.241 31.848 ;
     RECT  108.241 30.576 108.281 31.848 ;
     RECT  107.809 13.2 108.313 14.76 ;
     RECT  107.417 18.144 108.317 19.176 ;
     RECT  108.284 212.016 108.325 212.04 ;
     RECT  108.325 212.016 108.371 212.28 ;
     RECT  108.277 1.248 108.373 1.272 ;
     RECT  108.101 2.544 108.373 5.88 ;
     RECT  108.373 2.544 108.385 6.312 ;
     RECT  108.373 1.152 108.419 1.272 ;
     RECT  107.932 16.08 108.421 17.16 ;
     RECT  108.317 18.144 108.421 18.984 ;
     RECT  108.313 13.104 108.461 14.76 ;
     RECT  108.419 1.152 108.563 1.176 ;
     RECT  108.385 2.544 108.563 6.36 ;
     RECT  108.209 24.72 108.601 26.808 ;
     RECT  107.417 28.416 108.601 29.016 ;
     RECT  108.601 24.72 108.637 29.016 ;
     RECT  108.281 30.576 108.637 31.368 ;
     RECT  108.563 2.544 108.641 6.312 ;
     RECT  107.561 9.168 108.673 9.192 ;
     RECT  108.209 11.232 108.745 12.024 ;
     RECT  108.461 13.104 108.745 13.608 ;
     RECT  108.853 0.288 108.917 0.456 ;
     RECT  108.421 16.08 108.929 18.984 ;
     RECT  108.917 0.192 108.994 0.456 ;
     RECT  108.637 24.72 109.073 31.368 ;
     RECT  108.371 212.112 109.081 212.28 ;
     RECT  107.417 20.256 109.249 23.592 ;
     RECT  109.073 24.72 109.276 30.408 ;
     RECT  108.994 0.096 109.289 0.456 ;
     RECT  109.081 212.256 109.325 212.28 ;
     RECT  108.929 16.992 109.357 18.984 ;
     RECT  109.249 20.064 109.357 23.592 ;
     RECT  108.673 8.976 109.381 9.672 ;
     RECT  108.641 2.592 109.397 6.312 ;
     RECT  108.745 11.232 109.501 13.608 ;
     RECT  108.461 14.64 109.501 14.76 ;
     RECT  109.397 2.592 109.621 5.928 ;
     RECT  109.289 0.144 109.717 0.456 ;
     RECT  109.621 1.728 109.717 5.928 ;
     RECT  109.501 11.232 109.753 14.76 ;
     RECT  109.669 7.728 109.765 7.752 ;
     RECT  109.381 8.976 109.765 9.72 ;
     RECT  109.753 10.992 109.897 14.76 ;
     RECT  109.717 0.144 110.003 5.928 ;
     RECT  109.357 16.992 110.101 23.592 ;
     RECT  109.276 24.72 110.101 29.832 ;
     RECT  109.765 7.728 110.149 9.72 ;
     RECT  109.897 10.992 110.149 15 ;
     RECT  110.101 16.992 110.257 29.832 ;
     RECT  110.149 7.728 110.293 15 ;
     RECT  110.257 16.08 110.293 29.832 ;
     RECT  110.003 1.728 110.408 5.928 ;
     RECT  110.293 7.728 110.408 29.832 ;
     RECT  105.304 40.272 110.408 40.296 ;
     RECT  105.304 47.28 110.408 47.304 ;
     RECT  108.997 72.432 110.408 72.456 ;
     RECT  110.408 1.728 110.512 213.852 ;
     RECT  110.512 1.728 110.704 213.582 ;
     RECT  110.704 12.864 110.765 16.92 ;
     RECT  110.003 0.144 110.869 0.408 ;
     RECT  110.704 27.6 110.873 29.016 ;
     RECT  110.869 0.096 110.909 0.408 ;
     RECT  110.909 0.096 110.953 0.168 ;
     RECT  110.704 7.392 111.059 11.784 ;
     RECT  110.704 18.192 111.125 19.08 ;
     RECT  110.704 1.728 111.157 5.832 ;
     RECT  110.953 0.144 111.251 0.168 ;
     RECT  110.765 16.08 111.269 16.92 ;
     RECT  110.873 27.6 111.557 28.536 ;
     RECT  111.557 27.6 111.665 28.008 ;
     RECT  111.059 7.392 111.683 7.992 ;
     RECT  110.704 72.384 111.701 72.456 ;
     RECT  110.765 12.864 111.781 15.096 ;
     RECT  111.269 16.08 111.781 16.872 ;
     RECT  111.683 7.44 111.917 7.992 ;
     RECT  110.704 24.912 111.917 26.52 ;
     RECT  110.704 20.16 111.925 22.488 ;
     RECT  111.125 18.528 111.932 19.08 ;
     RECT  111.925 20.16 111.932 21.096 ;
     RECT  111.059 8.976 111.949 11.784 ;
     RECT  111.925 22.464 111.949 22.488 ;
     RECT  110.704 23.568 111.949 23.928 ;
     RECT  111.932 18.528 112.019 21.096 ;
     RECT  111.949 8.976 112.021 11.832 ;
     RECT  111.781 12.864 112.021 16.872 ;
     RECT  111.917 7.728 112.069 7.992 ;
     RECT  112.021 8.976 112.069 16.872 ;
     RECT  111.157 1.152 112.165 5.832 ;
     RECT  112.22 68.256 112.307 68.28 ;
     RECT  111.701 72.384 112.307 72.408 ;
     RECT  112.069 7.728 112.309 16.872 ;
     RECT  112.019 20.256 112.355 21.096 ;
     RECT  112.019 18.528 112.385 18.792 ;
     RECT  111.949 22.464 112.453 23.928 ;
     RECT  111.917 24.912 112.453 26.424 ;
     RECT  112.309 7.728 112.457 17.256 ;
     RECT  112.457 12.864 112.529 17.256 ;
     RECT  112.165 1.152 112.835 6.312 ;
     RECT  112.529 12.864 112.853 17.064 ;
     RECT  112.835 1.728 112.925 6.312 ;
     RECT  111.665 27.6 112.957 27.72 ;
     RECT  112.457 7.728 113.065 11.832 ;
     RECT  112.453 22.464 113.084 26.424 ;
     RECT  113.101 42.72 113.173 42.744 ;
     RECT  112.355 20.304 113.245 21.096 ;
     RECT  113.084 22.176 113.245 26.424 ;
     RECT  112.853 12.864 113.249 16.728 ;
     RECT  113.245 20.304 113.249 26.424 ;
     RECT  112.957 27.6 113.249 28.44 ;
     RECT  113.077 0.144 113.266 0.168 ;
     RECT  112.385 18.528 113.269 18.552 ;
     RECT  113.173 42.432 113.315 42.744 ;
     RECT  110.704 46.752 113.315 47.208 ;
     RECT  113.249 12.864 113.321 16.248 ;
     RECT  113.249 24.096 113.353 26.424 ;
     RECT  113.266 0.096 113.363 0.216 ;
     RECT  113.363 0.096 113.411 0.168 ;
     RECT  113.315 42.432 113.429 42.456 ;
     RECT  113.249 27.696 113.501 28.44 ;
     RECT  113.501 28.416 113.645 28.44 ;
     RECT  113.353 24.096 113.789 26.664 ;
     RECT  113.785 67.824 113.869 67.848 ;
     RECT  113.249 20.304 113.996 22.872 ;
     RECT  112.925 1.728 114.037 5.928 ;
     RECT  113.065 7.2 114.037 11.832 ;
     RECT  113.269 18.144 114.073 18.552 ;
     RECT  113.996 19.536 114.073 22.872 ;
     RECT  114.037 1.728 114.085 11.832 ;
     RECT  114.073 18.144 114.181 22.872 ;
     RECT  114.181 17.952 114.293 22.872 ;
     RECT  113.789 24.528 114.365 26.664 ;
     RECT  114.293 17.952 114.373 18.552 ;
     RECT  114.365 25.152 114.397 26.664 ;
     RECT  114.293 19.824 114.419 22.872 ;
     RECT  114.419 19.824 114.467 19.848 ;
     RECT  114.373 17.904 114.505 18.552 ;
     RECT  114.085 1.152 114.541 11.832 ;
     RECT  114.541 1.152 114.577 11.88 ;
     RECT  113.321 12.864 114.577 15.96 ;
     RECT  113.315 47.184 114.577 47.208 ;
     RECT  114.505 17.76 114.581 18.552 ;
     RECT  114.577 47.088 114.617 47.208 ;
     RECT  114.419 20.832 114.653 22.872 ;
     RECT  114.397 25.152 114.721 26.808 ;
     RECT  114.577 1.152 114.757 15.96 ;
     RECT  113.411 0.144 114.803 0.168 ;
     RECT  114.653 22.848 114.829 22.872 ;
     RECT  114.757 1.152 114.865 16.392 ;
     RECT  114.865 1.152 114.899 16.632 ;
     RECT  114.899 1.728 115.405 16.632 ;
     RECT  114.581 17.76 115.405 18.216 ;
     RECT  114.829 22.848 115.405 23.832 ;
     RECT  114.721 25.152 115.405 27.096 ;
     RECT  115.333 19.632 115.477 19.656 ;
     RECT  114.653 20.832 115.477 21.672 ;
     RECT  115.405 1.728 115.808 18.216 ;
     RECT  115.477 19.632 115.808 21.672 ;
     RECT  115.405 22.848 115.808 27.096 ;
     RECT  113.269 44.544 115.808 44.568 ;
     RECT  114.617 47.088 115.808 47.112 ;
     RECT  115.808 1.728 115.912 213.852 ;
     RECT  114.997 0.096 115.957 0.12 ;
     RECT  115.957 0.096 116.053 0.312 ;
     RECT  115.912 1.728 116.104 213.582 ;
     RECT  116.053 0.096 116.149 0.456 ;
     RECT  116.104 17.904 116.317 27.912 ;
     RECT  116.317 24.624 116.627 27.912 ;
     RECT  116.104 47.088 116.627 47.112 ;
     RECT  116.104 1.728 116.633 16.584 ;
     RECT  116.627 24.624 116.633 27.336 ;
     RECT  116.633 8.064 116.669 16.584 ;
     RECT  116.317 17.904 116.885 23.592 ;
     RECT  116.633 1.728 116.993 6.888 ;
     RECT  116.669 14.832 116.993 16.584 ;
     RECT  116.104 44.448 117.001 44.472 ;
     RECT  116.993 16.368 117.169 16.584 ;
     RECT  116.885 17.904 117.245 22.872 ;
     RECT  117.169 16.368 117.277 16.872 ;
     RECT  117.245 17.904 117.277 22.728 ;
     RECT  116.669 8.064 117.317 13.752 ;
     RECT  116.633 24.624 117.317 26.28 ;
     RECT  116.633 27.312 117.389 27.336 ;
     RECT  116.149 0.096 117.541 0.6 ;
     RECT  117.541 0.096 117.569 0.648 ;
     RECT  117.569 0.432 117.683 0.648 ;
     RECT  117.683 0.432 117.731 0.552 ;
     RECT  117.317 24.624 117.781 25.752 ;
     RECT  117.731 0.528 117.923 0.552 ;
     RECT  116.993 14.832 117.997 15.048 ;
     RECT  117.277 16.368 117.997 22.728 ;
     RECT  116.993 1.728 118.033 6.648 ;
     RECT  117.781 24.288 118.073 25.752 ;
     RECT  118.033 1.728 118.165 6.888 ;
     RECT  118.105 27.408 118.189 27.432 ;
     RECT  118.165 1.728 118.253 6.936 ;
     RECT  117.997 14.832 118.285 22.728 ;
     RECT  117.317 8.256 118.549 13.752 ;
     RECT  118.285 14.832 118.549 22.824 ;
     RECT  118.073 25.296 118.549 25.752 ;
     RECT  118.549 8.256 118.604 22.824 ;
     RECT  118.549 25.296 118.636 26.232 ;
     RECT  118.604 8.256 118.757 23.016 ;
     RECT  118.757 8.256 118.969 17.112 ;
     RECT  118.757 18.096 119.041 23.016 ;
     RECT  118.465 24.144 119.041 24.168 ;
     RECT  118.636 25.296 119.077 25.656 ;
     RECT  119.041 18.096 119.171 24.168 ;
     RECT  119.171 20.496 119.189 24.168 ;
     RECT  119.189 24.144 119.605 24.168 ;
     RECT  119.077 25.152 119.605 25.656 ;
     RECT  118.253 1.728 119.617 6.888 ;
     RECT  118.969 7.872 119.617 17.112 ;
     RECT  119.605 24.144 119.653 25.656 ;
     RECT  119.617 1.728 119.701 17.112 ;
     RECT  119.701 8.256 119.9 17.112 ;
     RECT  119.171 18.096 119.9 19.416 ;
     RECT  119.653 24.144 120.236 25.704 ;
     RECT  119.9 8.256 120.257 19.416 ;
     RECT  119.189 20.496 120.257 22.824 ;
     RECT  120.257 8.256 120.877 22.824 ;
     RECT  118.817 0.096 120.997 0.12 ;
     RECT  119.701 1.728 121.021 6.888 ;
     RECT  121.021 1.728 121.093 6.936 ;
     RECT  121.093 1.728 121.208 7.128 ;
     RECT  120.877 8.208 121.208 22.824 ;
     RECT  120.236 24.096 121.208 25.752 ;
     RECT  121.208 1.728 121.312 213.852 ;
     RECT  121.312 1.728 121.504 213.582 ;
     RECT  121.504 1.728 121.565 20.664 ;
     RECT  121.565 7.92 121.619 20.664 ;
     RECT  121.504 21.648 121.753 23.448 ;
     RECT  121.619 7.92 121.781 17.544 ;
     RECT  121.781 7.92 121.889 14.232 ;
     RECT  120.997 0.096 122.005 0.168 ;
     RECT  121.753 21.648 122.285 23.112 ;
     RECT  122.005 0.096 122.293 0.6 ;
     RECT  122.293 0.096 122.533 0.648 ;
     RECT  121.565 1.728 122.533 6.936 ;
     RECT  121.504 24.432 122.579 24.456 ;
     RECT  121.619 18.576 122.605 20.664 ;
     RECT  122.285 22.464 122.681 23.112 ;
     RECT  121.889 8.064 122.785 14.232 ;
     RECT  121.781 15.456 122.785 17.544 ;
     RECT  122.785 8.064 122.861 17.544 ;
     RECT  122.861 8.064 122.933 16.632 ;
     RECT  122.533 1.728 123.037 6.984 ;
     RECT  122.933 8.064 123.037 15.528 ;
     RECT  123.037 1.728 123.107 15.528 ;
     RECT  122.605 18.576 123.107 21.096 ;
     RECT  123.107 18.576 123.112 20.52 ;
     RECT  122.681 22.464 123.148 22.488 ;
     RECT  123.107 1.728 123.149 14.472 ;
     RECT  123.107 15.456 123.221 15.528 ;
     RECT  122.533 0.096 123.347 0.696 ;
     RECT  123.149 1.776 123.365 14.472 ;
     RECT  123.365 5.136 123.373 14.472 ;
     RECT  123.112 18.528 123.587 20.52 ;
     RECT  123.221 15.456 123.689 15.48 ;
     RECT  123.373 5.904 123.725 14.472 ;
     RECT  123.587 20.112 123.761 20.52 ;
     RECT  123.365 1.776 123.827 3.864 ;
     RECT  123.347 0.096 123.875 0.6 ;
     RECT  122.933 16.608 123.905 16.632 ;
     RECT  123.725 6.096 123.923 14.472 ;
     RECT  123.587 18.528 123.923 18.984 ;
     RECT  123.827 1.776 123.941 3.528 ;
     RECT  123.941 1.776 123.971 3.336 ;
     RECT  123.923 6.096 123.971 6.12 ;
     RECT  123.971 1.824 124.403 3.336 ;
     RECT  123.923 7.488 124.481 14.472 ;
     RECT  124.225 15.6 124.625 15.624 ;
     RECT  123.829 21.648 124.697 21.672 ;
     RECT  124.481 7.488 124.876 14.232 ;
     RECT  123.761 20.112 124.877 20.232 ;
     RECT  124.876 9.312 124.883 14.232 ;
     RECT  123.875 0.576 124.913 0.6 ;
     RECT  124.883 9.312 124.931 10.296 ;
     RECT  124.403 1.824 124.979 3.048 ;
     RECT  124.876 7.488 124.979 8.28 ;
     RECT  124.979 1.92 125.021 3.048 ;
     RECT  123.923 18.528 125.057 18.552 ;
     RECT  124.931 9.696 125.165 10.296 ;
     RECT  124.877 20.112 125.201 20.136 ;
     RECT  125.165 10.272 125.273 10.296 ;
     RECT  124.883 13.488 125.309 14.232 ;
     RECT  125.021 2.16 125.459 3.048 ;
     RECT  124.883 11.28 125.459 12.312 ;
     RECT  125.309 14.208 125.516 14.232 ;
     RECT  125.459 2.304 125.555 3.048 ;
     RECT  125.516 14.208 125.603 14.808 ;
     RECT  125.516 15.792 125.603 15.816 ;
     RECT  125.413 17.04 125.603 17.064 ;
     RECT  125.555 2.304 126.608 2.424 ;
     RECT  124.979 7.488 126.608 7.512 ;
     RECT  125.459 11.664 126.608 12.312 ;
     RECT  126.608 2.148 126.712 213.852 ;
     RECT  126.712 2.418 126.904 213.582 ;
     RECT  132.008 2.148 132.112 213.852 ;
     RECT  132.112 2.418 132.304 213.582 ;
     RECT  137.408 2.148 137.512 213.852 ;
     RECT  137.512 2.418 137.704 213.582 ;
     RECT  142.808 2.148 142.912 213.852 ;
     RECT  142.912 2.418 143.104 213.582 ;
     RECT  148.208 2.148 148.312 213.852 ;
     RECT  148.312 2.418 148.504 213.582 ;
     RECT  153.608 2.148 153.712 213.852 ;
     RECT  153.712 2.418 153.904 213.582 ;
     RECT  159.008 2.148 159.112 213.852 ;
     RECT  159.112 2.418 159.304 213.582 ;
     RECT  164.408 2.148 164.512 213.852 ;
     RECT  164.512 2.418 164.704 213.582 ;
     RECT  169.808 2.148 169.912 213.852 ;
     RECT  169.912 2.418 170.104 213.582 ;
     RECT  175.208 2.148 175.312 213.852 ;
     RECT  175.312 2.418 175.504 213.582 ;
     RECT  180.608 2.148 180.712 213.852 ;
     RECT  180.712 2.418 180.904 213.582 ;
     RECT  186.008 2.148 186.112 213.852 ;
     RECT  186.112 2.418 186.304 213.582 ;
     RECT  191.408 2.148 191.512 213.852 ;
     RECT  191.512 2.418 191.704 213.582 ;
     RECT  196.808 2.148 196.912 213.852 ;
     RECT  196.912 2.418 197.104 213.582 ;
     RECT  202.208 2.148 202.312 213.852 ;
     RECT  202.312 2.418 202.504 213.582 ;
     RECT  207.608 2.148 207.712 213.852 ;
     RECT  207.712 2.418 207.904 213.582 ;
     RECT  213.008 2.148 213.112 213.852 ;
     RECT  213.112 2.418 213.304 213.582 ;
    LAYER M5 ;
     RECT  92.64 0.016 123.384 0.085 ;
     RECT  92.64 0.085 123.864 1.765 ;
     RECT  124.944 1.813 124.968 2.149 ;
     RECT  2.4 2.137 2.52 2.151 ;
     RECT  7.8 2.137 7.92 2.151 ;
     RECT  13.2 2.137 13.32 2.151 ;
     RECT  18.6 2.137 18.72 2.151 ;
     RECT  24 2.137 24.12 2.151 ;
     RECT  29.4 2.137 29.52 2.151 ;
     RECT  34.8 2.137 34.92 2.151 ;
     RECT  40.2 2.137 40.32 2.151 ;
     RECT  45.6 2.137 45.72 2.151 ;
     RECT  51 2.137 51.12 2.151 ;
     RECT  56.4 2.137 56.52 2.151 ;
     RECT  61.8 2.137 61.92 2.151 ;
     RECT  67.2 2.137 67.32 2.151 ;
     RECT  72.6 2.137 72.72 2.151 ;
     RECT  78 2.137 78.12 2.151 ;
     RECT  83.4 2.137 83.52 2.151 ;
     RECT  88.8 2.137 88.92 2.151 ;
     RECT  126.6 2.137 126.72 2.151 ;
     RECT  132 2.137 132.12 2.151 ;
     RECT  137.4 2.137 137.52 2.151 ;
     RECT  142.8 2.137 142.92 2.151 ;
     RECT  148.2 2.137 148.32 2.151 ;
     RECT  153.6 2.137 153.72 2.151 ;
     RECT  159 2.137 159.12 2.151 ;
     RECT  164.4 2.137 164.52 2.151 ;
     RECT  169.8 2.137 169.92 2.151 ;
     RECT  175.2 2.137 175.32 2.151 ;
     RECT  180.6 2.137 180.72 2.151 ;
     RECT  186 2.137 186.12 2.151 ;
     RECT  191.4 2.137 191.52 2.151 ;
     RECT  196.8 2.137 196.92 2.151 ;
     RECT  202.2 2.137 202.32 2.151 ;
     RECT  207.6 2.137 207.72 2.151 ;
     RECT  213 2.137 213.12 2.151 ;
     RECT  92.64 1.765 123.96 2.387 ;
     RECT  93.12 2.387 123.96 2.485 ;
     RECT  124.944 2.149 125.448 2.485 ;
     RECT  93.12 2.485 125.448 2.725 ;
     RECT  93.12 2.725 125.496 3.013 ;
     RECT  93.12 3.013 125.544 3.443 ;
     RECT  93.408 3.443 125.544 3.683 ;
     RECT  88.8 2.151 89.112 4.501 ;
     RECT  93.456 3.683 125.544 5.843 ;
     RECT  93.456 5.843 107.256 5.891 ;
     RECT  88.8 4.501 89.544 6.277 ;
     RECT  88.8 6.277 90.12 6.323 ;
     RECT  108.384 5.843 125.544 6.323 ;
     RECT  108.528 6.323 116.28 6.371 ;
     RECT  117.36 6.323 125.544 6.371 ;
     RECT  109.296 6.371 116.28 6.419 ;
     RECT  93.456 5.891 106.728 6.611 ;
     RECT  93.456 6.611 103.416 6.899 ;
     RECT  90.096 6.323 90.12 7.187 ;
     RECT  114.672 6.419 116.28 8.003 ;
     RECT  115.536 8.003 116.28 8.293 ;
     RECT  117.36 6.371 119.784 8.293 ;
     RECT  93.456 6.899 97.848 8.485 ;
     RECT  90.576 7.909 90.6 8.531 ;
     RECT  98.928 6.899 103.416 8.579 ;
     RECT  109.296 6.419 113.4 8.579 ;
     RECT  109.296 8.579 111.432 9.155 ;
     RECT  115.536 8.293 119.784 9.155 ;
     RECT  92.592 8.485 97.848 9.539 ;
     RECT  93.744 9.539 97.848 9.731 ;
     RECT  109.392 9.155 111.432 9.731 ;
     RECT  115.536 9.155 119.064 9.731 ;
     RECT  120.864 6.371 125.544 9.731 ;
     RECT  92.592 9.539 92.616 9.781 ;
     RECT  123.696 9.731 125.544 9.875 ;
     RECT  99.6 8.579 103.416 9.925 ;
     RECT  104.592 6.611 106.728 9.925 ;
     RECT  87.792 6.661 87.816 10.019 ;
     RECT  123.744 9.875 125.544 10.115 ;
     RECT  112.704 8.579 113.4 10.307 ;
     RECT  93.744 9.731 96.312 10.355 ;
     RECT  123.792 10.115 125.544 10.451 ;
     RECT  92.496 9.781 92.616 10.595 ;
     RECT  99.6 9.925 106.728 10.597 ;
     RECT  90.192 9.397 90.216 10.643 ;
     RECT  92.544 10.595 92.616 10.741 ;
     RECT  87.696 10.213 87.72 10.789 ;
     RECT  86.832 10.789 87.72 10.883 ;
     RECT  99.504 10.597 106.728 10.883 ;
     RECT  109.68 9.731 111.432 10.883 ;
     RECT  112.992 10.307 113.4 10.883 ;
     RECT  99.504 10.883 100.104 10.931 ;
     RECT  124.368 10.451 125.544 10.931 ;
     RECT  93.984 10.355 96.312 10.979 ;
     RECT  113.04 10.883 113.208 10.979 ;
     RECT  113.136 10.979 113.208 11.027 ;
     RECT  94.2 10.979 96.312 11.029 ;
     RECT  124.368 10.931 124.392 11.267 ;
     RECT  88.8 6.323 89.112 11.269 ;
     RECT  125.424 10.931 125.544 11.315 ;
     RECT  101.232 10.883 106.728 11.459 ;
     RECT  115.8 9.731 119.064 11.459 ;
     RECT  99.504 10.931 99.912 11.555 ;
     RECT  125.472 11.315 125.544 11.653 ;
     RECT  126.6 2.151 126.912 11.653 ;
     RECT  125.472 11.653 126.912 11.795 ;
     RECT  125.472 11.795 125.496 11.843 ;
     RECT  120.864 9.731 121.992 11.891 ;
     RECT  121.104 11.891 121.992 11.987 ;
     RECT  85.824 10.213 85.848 12.035 ;
     RECT  101.232 11.459 101.256 12.035 ;
     RECT  102.24 11.459 106.728 12.035 ;
     RECT  121.104 11.987 121.512 12.035 ;
     RECT  103.344 12.035 106.152 12.083 ;
     RECT  109.68 10.883 110.712 12.277 ;
     RECT  115.8 11.459 117.72 12.517 ;
     RECT  119.04 11.459 119.064 12.517 ;
     RECT  94.2 11.029 96.84 12.563 ;
     RECT  98.016 11.365 98.04 12.563 ;
     RECT  103.392 12.083 106.152 12.563 ;
     RECT  109.344 12.277 110.712 12.659 ;
     RECT  115.8 12.517 119.064 12.899 ;
     RECT  109.92 12.659 110.712 12.901 ;
     RECT  112.032 12.517 112.056 12.901 ;
     RECT  92.544 10.741 92.904 13.187 ;
     RECT  124.848 12.757 124.872 13.523 ;
     RECT  99.6 11.555 99.912 13.573 ;
     RECT  104.256 12.563 106.152 13.957 ;
     RECT  92.592 13.187 92.904 14.197 ;
     RECT  94.2 12.563 96.216 14.197 ;
     RECT  99.6 13.573 100.008 14.197 ;
     RECT  115.8 12.899 118.584 14.197 ;
     RECT  97.536 13.045 97.56 14.243 ;
     RECT  109.92 12.901 112.056 14.387 ;
     RECT  98.976 14.197 100.008 14.629 ;
     RECT  121.2 12.035 121.512 14.677 ;
     RECT  113.184 11.027 113.208 14.725 ;
     RECT  120.96 14.677 121.512 14.725 ;
     RECT  98.592 14.629 100.008 14.821 ;
     RECT  92.592 14.197 93.048 14.867 ;
     RECT  103.632 13.957 106.152 14.867 ;
     RECT  109.92 14.387 111.912 14.963 ;
     RECT  115.8 14.197 118.728 15.011 ;
     RECT  120.96 14.725 121.608 15.061 ;
     RECT  102.24 12.035 102.264 15.205 ;
     RECT  98.592 14.821 100.056 15.251 ;
     RECT  111.792 14.963 111.912 15.299 ;
     RECT  111.888 15.299 111.912 15.349 ;
     RECT  123.072 12.997 123.096 15.491 ;
     RECT  120.576 15.061 121.608 15.493 ;
     RECT  115.8 15.011 118.152 15.541 ;
     RECT  102.096 15.205 102.264 15.635 ;
     RECT  86.832 10.883 86.856 15.827 ;
     RECT  113.136 14.725 113.208 15.971 ;
     RECT  92.592 14.867 92.904 16.019 ;
     RECT  94.2 14.197 96.504 16.019 ;
     RECT  103.632 14.867 105.96 16.021 ;
     RECT  107.856 15.829 107.88 16.021 ;
     RECT  115.632 15.541 118.152 16.069 ;
     RECT  98.592 15.251 99.912 16.163 ;
     RECT  120.096 15.493 121.608 16.501 ;
     RECT  109.92 14.963 110.712 16.597 ;
     RECT  111.888 15.349 112.008 16.597 ;
     RECT  115.536 16.069 118.152 16.837 ;
     RECT  109.92 16.597 112.008 16.931 ;
     RECT  102.24 15.635 102.264 16.981 ;
     RECT  102.24 16.981 102.648 17.075 ;
     RECT  125.568 14.197 125.592 17.075 ;
     RECT  108.864 16.981 108.888 17.123 ;
     RECT  115.488 16.837 118.152 17.509 ;
     RECT  92.592 16.019 92.808 17.605 ;
     RECT  98.592 16.163 98.616 17.605 ;
     RECT  99.6 16.163 99.912 17.605 ;
     RECT  109.92 16.931 110.712 17.605 ;
     RECT  113.184 15.971 113.208 18.133 ;
     RECT  103.632 16.021 107.88 18.181 ;
     RECT  109.68 17.605 110.712 18.181 ;
     RECT  114.384 17.893 114.408 18.181 ;
     RECT  119.952 16.501 121.608 18.181 ;
     RECT  115.44 17.509 118.152 18.227 ;
     RECT  92.592 17.605 92.904 18.229 ;
     RECT  94.2 16.019 96.216 18.229 ;
     RECT  102.624 17.075 102.648 18.275 ;
     RECT  103.632 18.181 108.216 18.275 ;
     RECT  92.592 18.229 93.048 18.517 ;
     RECT  94.08 18.229 96.216 18.517 ;
     RECT  98.592 17.605 99.912 18.709 ;
     RECT  92.592 18.517 96.216 18.757 ;
     RECT  111.888 16.931 112.008 18.757 ;
     RECT  113.184 18.133 113.304 18.757 ;
     RECT  115.488 18.227 118.152 18.757 ;
     RECT  119.856 18.181 121.608 18.757 ;
     RECT  123.888 18.709 123.912 18.995 ;
     RECT  115.488 18.757 121.608 18.997 ;
     RECT  109.68 18.181 110.808 19.091 ;
     RECT  92.592 18.757 97.08 19.141 ;
     RECT  103.68 18.275 108.216 19.235 ;
     RECT  111.888 18.757 113.304 19.525 ;
     RECT  114.384 18.181 114.456 19.525 ;
     RECT  109.68 19.091 110.712 19.715 ;
     RECT  115.488 18.997 121.848 19.811 ;
     RECT  92.592 19.141 97.224 19.909 ;
     RECT  90.144 19.237 90.168 20.003 ;
     RECT  103.68 19.235 106.152 20.051 ;
     RECT  111.888 19.525 114.456 20.051 ;
     RECT  123.552 19.237 123.576 20.243 ;
     RECT  107.136 19.235 108.216 20.291 ;
     RECT  111.888 20.051 113.304 20.291 ;
     RECT  115.488 19.811 121.512 20.579 ;
     RECT  115.488 20.579 119.4 20.627 ;
     RECT  86.064 16.501 86.088 20.867 ;
     RECT  107.712 20.291 108.216 20.963 ;
     RECT  110.256 19.715 110.712 21.109 ;
     RECT  114.384 20.051 114.456 21.205 ;
     RECT  113.136 20.291 113.304 21.635 ;
     RECT  111.888 20.291 111.912 21.683 ;
     RECT  109.632 21.109 110.712 21.779 ;
     RECT  115.536 20.627 119.4 21.925 ;
     RECT  114.384 21.205 114.552 22.403 ;
     RECT  121.2 20.579 121.512 22.453 ;
     RECT  123.072 21.061 123.096 22.499 ;
     RECT  110.256 21.779 110.712 22.741 ;
     RECT  115.536 21.925 119.64 22.789 ;
     RECT  121.2 22.453 121.704 22.789 ;
     RECT  107.856 20.963 108.216 22.835 ;
     RECT  107.856 22.835 108.12 22.883 ;
     RECT  115.536 22.789 121.704 23.077 ;
     RECT  103.68 20.051 105.96 23.123 ;
     RECT  108.096 22.883 108.12 23.123 ;
     RECT  101.712 23.077 101.736 23.317 ;
     RECT  115.536 23.077 122.568 23.459 ;
     RECT  92.592 19.909 97.512 23.651 ;
     RECT  110.112 22.741 110.712 23.891 ;
     RECT  101.712 23.317 101.928 23.939 ;
     RECT  115.536 23.459 121.512 24.179 ;
     RECT  115.536 24.179 118.152 24.371 ;
     RECT  98.544 18.709 99.912 24.419 ;
     RECT  122.544 23.459 122.568 24.467 ;
     RECT  92.592 23.651 97.224 24.611 ;
     RECT  13.2 2.151 13.512 24.613 ;
     RECT  113.136 21.635 113.208 24.659 ;
     RECT  7.8 2.151 8.112 24.901 ;
     RECT  101.712 23.939 101.736 24.901 ;
     RECT  103.68 23.123 105.432 24.947 ;
     RECT  113.184 24.659 113.208 25.141 ;
     RECT  114.528 22.403 114.552 25.141 ;
     RECT  107.28 24.469 107.304 25.189 ;
     RECT  106.752 25.189 107.304 25.235 ;
     RECT  24 2.151 24.312 25.237 ;
     RECT  103.776 24.947 105.432 25.285 ;
     RECT  119.616 24.179 121.512 25.331 ;
     RECT  103.776 25.285 105.528 25.475 ;
     RECT  115.8 24.371 118.152 25.621 ;
     RECT  87.84 11.269 89.112 25.715 ;
     RECT  119.664 25.331 121.512 25.715 ;
     RECT  113.184 25.141 114.552 25.763 ;
     RECT  120.288 25.715 121.512 25.763 ;
     RECT  106.752 25.235 106.776 26.099 ;
     RECT  111.792 25.621 111.816 26.243 ;
     RECT  115.8 25.621 118.584 26.243 ;
     RECT  115.8 26.243 118.152 26.291 ;
     RECT  13.2 24.613 14.04 26.533 ;
     RECT  12.624 26.533 14.04 26.581 ;
     RECT  16.608 25.717 16.632 26.581 ;
     RECT  6.912 24.901 8.112 26.629 ;
     RECT  94.2 24.611 97.224 26.773 ;
     RECT  10.08 26.821 10.104 27.109 ;
     RECT  16.608 26.581 16.68 27.109 ;
     RECT  101.136 24.901 101.736 27.253 ;
     RECT  103.776 25.475 105.432 27.395 ;
     RECT  94.08 26.773 97.224 27.443 ;
     RECT  118.128 26.291 118.152 27.443 ;
     RECT  91.392 16.453 91.416 27.491 ;
     RECT  12.624 26.581 14.424 27.685 ;
     RECT  10.08 27.109 10.92 27.877 ;
     RECT  104.784 27.395 105.432 27.923 ;
     RECT  101.136 27.253 102.696 28.451 ;
     RECT  106.56 27.589 106.584 28.979 ;
     RECT  98.88 24.419 99.912 29.027 ;
     RECT  88.512 25.715 89.112 29.029 ;
     RECT  90.384 20.821 90.408 29.029 ;
     RECT  86.592 25.141 86.616 29.123 ;
     RECT  92.592 24.611 92.808 29.363 ;
     RECT  108.72 28.405 108.744 29.507 ;
     RECT  78 2.151 78.312 29.509 ;
     RECT  94.08 27.443 97.176 29.557 ;
     RECT  88.512 29.029 90.408 29.699 ;
     RECT  105 27.923 105.432 30.181 ;
     RECT  103.776 27.395 103.8 30.229 ;
     RECT  104.88 30.181 105.432 30.229 ;
     RECT  93.936 29.557 97.176 30.275 ;
     RECT  103.776 30.229 105.432 30.275 ;
     RECT  109.2 29.797 109.224 30.419 ;
     RECT  88.512 29.699 89.112 30.611 ;
     RECT  103.968 30.275 105.432 30.851 ;
     RECT  6.912 26.629 8.328 30.853 ;
     RECT  105 30.851 105.432 30.949 ;
     RECT  34.8 2.151 35.112 31.141 ;
     RECT  90.336 29.699 90.408 31.141 ;
     RECT  93.936 30.275 94.92 31.909 ;
     RECT  96.192 30.275 97.176 31.955 ;
     RECT  105 30.949 105.672 31.955 ;
     RECT  93.888 31.909 94.92 32.149 ;
     RECT  93.792 32.149 94.92 32.339 ;
     RECT  97.152 31.955 97.176 32.387 ;
     RECT  90.336 31.141 90.792 32.435 ;
     RECT  92.736 29.363 92.808 32.771 ;
     RECT  88.8 30.611 89.112 32.917 ;
     RECT  90.336 32.435 90.36 33.445 ;
     RECT  10.08 27.877 11.256 33.541 ;
     RECT  103.968 30.851 103.992 34.115 ;
     RECT  90.336 33.445 91.032 34.259 ;
     RECT  101.136 28.451 101.736 34.499 ;
     RECT  76.32 28.213 76.344 35.363 ;
     RECT  6.912 30.853 8.376 35.413 ;
     RECT  10.032 33.541 11.256 35.413 ;
     RECT  101.712 34.499 101.736 37.523 ;
     RECT  78 29.509 78.408 37.667 ;
     RECT  105 31.955 105.432 38.435 ;
     RECT  97.728 32.437 97.752 40.261 ;
     RECT  110.256 23.891 110.712 40.307 ;
     RECT  113.184 25.763 113.832 42.467 ;
     RECT  115.8 26.291 116.952 44.483 ;
     RECT  113.28 42.467 113.832 46.787 ;
     RECT  115.8 44.483 116.616 47.123 ;
     RECT  97.728 40.261 98.04 47.315 ;
     RECT  92.736 32.771 92.76 49.043 ;
     RECT  91.008 34.259 91.032 49.381 ;
     RECT  88.032 32.917 89.112 51.683 ;
     RECT  61.8 2.151 62.112 51.685 ;
     RECT  91.008 49.381 91.176 52.499 ;
     RECT  91.008 52.499 91.032 54.179 ;
     RECT  97.728 47.315 97.8 59.843 ;
     RECT  90.336 59.797 90.36 62.725 ;
     RECT  97.776 59.843 97.8 62.771 ;
     RECT  90.336 62.725 90.456 63.349 ;
     RECT  90.288 63.349 90.456 63.395 ;
     RECT  113.808 46.787 113.832 67.859 ;
     RECT  29.4 2.151 29.712 70.789 ;
     RECT  112.272 46.741 112.296 72.419 ;
     RECT  6.912 35.413 11.256 76.979 ;
     RECT  61.632 51.685 62.112 78.419 ;
     RECT  6.576 77.173 6.6 78.613 ;
     RECT  7.8 76.979 11.256 78.613 ;
     RECT  12.624 27.685 15.24 82.309 ;
     RECT  6.576 78.613 11.256 82.691 ;
     RECT  12.288 82.309 15.24 85.477 ;
     RECT  16.608 27.109 17.16 85.477 ;
     RECT  6.576 82.691 10.584 86.099 ;
     RECT  12.288 85.477 17.16 86.675 ;
     RECT  12.288 86.675 16.92 87.251 ;
     RECT  29.4 70.789 30.504 88.067 ;
     RECT  18.6 2.151 18.912 88.165 ;
     RECT  90.288 63.395 90.312 91.955 ;
     RECT  65.232 78.469 65.256 92.149 ;
     RECT  65.232 92.149 65.448 92.195 ;
     RECT  25.92 31.957 25.944 95.219 ;
     RECT  12.288 87.251 14.136 95.605 ;
     RECT  15.648 87.251 16.92 95.605 ;
     RECT  23.52 25.237 24.312 95.795 ;
     RECT  6.576 86.099 10.536 98.581 ;
     RECT  33.888 31.141 35.112 98.675 ;
     RECT  5.904 98.581 10.536 99.493 ;
     RECT  93.792 32.339 94.512 101.363 ;
     RECT  12.288 95.605 16.92 102.083 ;
     RECT  17.904 88.165 18.912 102.371 ;
     RECT  12.912 102.083 16.92 102.659 ;
     RECT  13.104 102.659 16.92 103.475 ;
     RECT  5.904 99.493 11.016 103.763 ;
     RECT  13.104 103.475 14.568 103.957 ;
     RECT  12.912 103.957 14.568 104.099 ;
     RECT  99.072 29.027 99.912 104.197 ;
     RECT  13.104 104.099 14.568 104.531 ;
     RECT  5.904 103.763 10.536 104.915 ;
     RECT  5.904 104.915 6.792 105.491 ;
     RECT  15.696 103.475 16.92 105.491 ;
     RECT  7.8 104.915 10.536 105.539 ;
     RECT  7.8 105.539 10.248 105.635 ;
     RECT  93.936 101.363 94.512 105.923 ;
     RECT  7.8 105.635 8.712 106.067 ;
     RECT  15.696 105.491 15.72 106.643 ;
     RECT  9.888 105.635 10.248 106.691 ;
     RECT  11.376 106.021 11.4 106.691 ;
     RECT  0.144 106.933 0.168 107.123 ;
     RECT  10.032 106.691 10.248 107.365 ;
     RECT  6.096 105.491 6.792 107.653 ;
     RECT  13.104 104.531 14.136 107.843 ;
     RECT  7.8 106.067 8.112 108.133 ;
     RECT  10.032 107.365 11.016 108.227 ;
     RECT  5.424 107.653 6.792 108.323 ;
     RECT  7.8 108.133 8.232 108.323 ;
     RECT  13.2 107.843 14.136 108.899 ;
     RECT  10.032 108.227 10.248 109.475 ;
     RECT  65.424 92.195 65.448 109.475 ;
     RECT  7.8 108.323 8.112 110.485 ;
     RECT  10.224 109.475 10.248 110.581 ;
     RECT  6.096 108.323 6.792 110.627 ;
     RECT  0.192 110.581 0.216 110.867 ;
     RECT  11.568 109.957 11.592 110.867 ;
     RECT  7.8 110.485 8.52 110.915 ;
     RECT  9.888 110.581 10.248 111.203 ;
     RECT  13.2 108.899 13.608 111.347 ;
     RECT  9.888 111.203 9.912 111.875 ;
     RECT  1.152 112.117 1.176 112.259 ;
     RECT  6.096 110.627 6.12 112.741 ;
     RECT  7.8 110.915 8.112 112.741 ;
     RECT  2.4 2.151 2.712 113.605 ;
     RECT  2.4 113.605 2.808 113.987 ;
     RECT  6.096 112.741 8.112 114.563 ;
     RECT  6.096 114.563 6.12 114.611 ;
     RECT  92.736 52.981 92.76 118.019 ;
     RECT  86.448 108.277 86.472 118.067 ;
     RECT  98.928 104.197 99.912 122.003 ;
     RECT  97.152 118.117 97.176 123.299 ;
     RECT  107.808 109.957 107.832 212.005 ;
     RECT  109.008 72.421 109.032 212.005 ;
     RECT  107.808 212.005 109.032 212.147 ;
     RECT  107.808 212.147 108.36 212.291 ;
     RECT  2.4 113.987 2.712 213.849 ;
     RECT  7.8 114.563 8.112 213.849 ;
     RECT  13.2 111.347 13.512 213.849 ;
     RECT  18.6 102.371 18.912 213.849 ;
     RECT  24 95.795 24.312 213.849 ;
     RECT  29.4 88.067 29.712 213.849 ;
     RECT  34.8 98.675 35.112 213.849 ;
     RECT  40.2 2.151 40.512 213.849 ;
     RECT  45.6 2.151 45.912 213.849 ;
     RECT  51 2.151 51.312 213.849 ;
     RECT  56.4 2.151 56.712 213.849 ;
     RECT  61.8 78.419 62.112 213.849 ;
     RECT  67.2 2.151 67.512 213.849 ;
     RECT  72.6 2.151 72.912 213.849 ;
     RECT  78 37.667 78.312 213.849 ;
     RECT  83.4 2.151 83.712 213.849 ;
     RECT  88.8 51.683 89.112 213.849 ;
     RECT  94.2 105.923 94.512 213.849 ;
     RECT  99.6 122.003 99.912 213.849 ;
     RECT  105 38.435 105.312 213.849 ;
     RECT  110.4 40.307 110.712 213.849 ;
     RECT  115.8 47.123 116.112 213.849 ;
     RECT  121.2 25.763 121.512 213.849 ;
     RECT  126.6 11.795 126.912 213.849 ;
     RECT  132 2.151 132.312 213.849 ;
     RECT  137.4 2.151 137.712 213.849 ;
     RECT  142.8 2.151 143.112 213.849 ;
     RECT  148.2 2.151 148.512 213.849 ;
     RECT  153.6 2.151 153.912 213.849 ;
     RECT  159 2.151 159.312 213.849 ;
     RECT  164.4 2.151 164.712 213.849 ;
     RECT  169.8 2.151 170.112 213.849 ;
     RECT  175.2 2.151 175.512 213.849 ;
     RECT  180.6 2.151 180.912 213.849 ;
     RECT  186 2.151 186.312 213.849 ;
     RECT  191.4 2.151 191.712 213.849 ;
     RECT  196.8 2.151 197.112 213.849 ;
     RECT  202.2 2.151 202.512 213.849 ;
     RECT  207.6 2.151 207.912 213.849 ;
     RECT  213 2.151 213.312 213.849 ;
     RECT  2.4 213.849 2.52 213.863 ;
     RECT  7.8 213.849 7.92 213.863 ;
     RECT  13.2 213.849 13.32 213.863 ;
     RECT  18.6 213.849 18.72 213.863 ;
     RECT  24 213.849 24.12 213.863 ;
     RECT  29.4 213.849 29.52 213.863 ;
     RECT  34.8 213.849 34.92 213.863 ;
     RECT  40.2 213.849 40.32 213.863 ;
     RECT  45.6 213.849 45.72 213.863 ;
     RECT  51 213.849 51.12 213.863 ;
     RECT  56.4 213.849 56.52 213.863 ;
     RECT  61.8 213.849 61.92 213.863 ;
     RECT  67.2 213.849 67.32 213.863 ;
     RECT  72.6 213.849 72.72 213.863 ;
     RECT  78 213.849 78.12 213.863 ;
     RECT  83.4 213.849 83.52 213.863 ;
     RECT  88.8 213.849 88.92 213.863 ;
     RECT  94.2 213.849 94.32 213.863 ;
     RECT  99.6 213.849 99.72 213.863 ;
     RECT  105 213.849 105.12 213.863 ;
     RECT  110.4 213.849 110.52 213.863 ;
     RECT  115.8 213.849 115.92 213.863 ;
     RECT  121.2 213.849 121.32 213.863 ;
     RECT  126.6 213.849 126.72 213.863 ;
     RECT  132 213.849 132.12 213.863 ;
     RECT  137.4 213.849 137.52 213.863 ;
     RECT  142.8 213.849 142.92 213.863 ;
     RECT  148.2 213.849 148.32 213.863 ;
     RECT  153.6 213.849 153.72 213.863 ;
     RECT  159 213.849 159.12 213.863 ;
     RECT  164.4 213.849 164.52 213.863 ;
     RECT  169.8 213.849 169.92 213.863 ;
     RECT  175.2 213.849 175.32 213.863 ;
     RECT  180.6 213.849 180.72 213.863 ;
     RECT  186 213.849 186.12 213.863 ;
     RECT  191.4 213.849 191.52 213.863 ;
     RECT  196.8 213.849 196.92 213.863 ;
     RECT  202.2 213.849 202.32 213.863 ;
     RECT  207.6 213.849 207.72 213.863 ;
     RECT  213 213.849 213.12 213.863 ;
     RECT  107.808 212.291 108.216 215.952 ;
     RECT  123.96 1.813 124.944 2.485 ;
     RECT  125.448 2.149 126.6 2.725 ;
     RECT  125.496 2.725 126.6 3.013 ;
     RECT  125.544 3.013 126.6 11.653 ;
     RECT  107.256 5.843 108.384 5.891 ;
     RECT  89.112 6.323 90.096 7.187 ;
     RECT  116.28 6.323 117.36 8.293 ;
     RECT  119.784 6.371 120.864 9.155 ;
     RECT  113.4 6.419 114.672 8.003 ;
     RECT  103.416 6.611 104.592 9.925 ;
     RECT  87.816 6.661 88.8 10.019 ;
     RECT  97.848 6.899 98.928 8.579 ;
     RECT  89.112 7.187 90.12 7.909 ;
     RECT  89.112 7.909 90.576 8.531 ;
     RECT  89.112 8.531 90.216 9.397 ;
     RECT  111.432 8.579 112.704 10.307 ;
     RECT  89.112 9.397 90.192 10.643 ;
     RECT  92.616 9.539 93.744 10.355 ;
     RECT  96.312 9.731 96.84 11.029 ;
     RECT  87.792 10.019 88.8 10.213 ;
     RECT  87.72 10.213 88.8 10.883 ;
     RECT  92.616 10.355 93.984 10.741 ;
     RECT  92.904 10.741 93.984 10.979 ;
     RECT  85.848 10.789 86.832 12.035 ;
     RECT  86.856 10.883 88.8 11.269 ;
     RECT  100.104 10.883 101.232 10.931 ;
     RECT  99.912 10.931 101.232 12.035 ;
     RECT  124.392 10.931 125.424 11.267 ;
     RECT  92.904 10.979 94.2 14.197 ;
     RECT  113.136 11.027 113.184 12.517 ;
     RECT  124.848 11.267 125.424 11.315 ;
     RECT  86.856 11.269 87.84 15.827 ;
     RECT  124.848 11.315 125.472 11.843 ;
     RECT  96.84 11.365 98.016 12.563 ;
     RECT  98.04 11.365 99.504 11.555 ;
     RECT  101.256 11.459 102.24 12.035 ;
     RECT  117.72 11.459 119.04 12.517 ;
     RECT  125.496 11.795 126.6 11.843 ;
     RECT  124.848 11.843 124.872 12.757 ;
     RECT  102.264 12.035 103.344 12.083 ;
     RECT  102.264 12.083 103.392 12.563 ;
     RECT  110.712 12.517 112.032 12.901 ;
     RECT  112.056 12.517 113.184 14.387 ;
     RECT  96.216 12.563 97.56 13.045 ;
     RECT  102.264 12.563 104.256 13.957 ;
     RECT  118.584 12.899 118.728 14.197 ;
     RECT  96.216 13.045 97.536 14.197 ;
     RECT  102.264 13.957 103.632 16.981 ;
     RECT  93.048 14.197 94.2 14.867 ;
     RECT  96.504 14.197 97.536 14.243 ;
     RECT  97.56 14.197 98.976 14.243 ;
     RECT  125.592 14.197 126.6 17.075 ;
     RECT  98.592 14.243 98.976 14.629 ;
     RECT  111.912 14.387 113.184 14.725 ;
     RECT  111.912 14.725 113.136 15.349 ;
     RECT  121.608 14.725 123.072 15.491 ;
     RECT  92.904 14.867 94.2 16.019 ;
     RECT  105.96 14.867 106.152 16.021 ;
     RECT  110.712 14.963 111.792 15.299 ;
     RECT  110.712 15.299 111.888 16.597 ;
     RECT  112.008 15.349 113.136 15.971 ;
     RECT  112.008 15.971 113.184 18.757 ;
     RECT  92.808 16.019 94.2 17.605 ;
     RECT  98.616 16.163 99.6 17.605 ;
     RECT  91.416 16.453 92.592 27.491 ;
     RECT  110.712 16.931 111.888 18.181 ;
     RECT  102.648 16.981 103.632 18.275 ;
     RECT  107.88 16.981 108.864 17.123 ;
     RECT  108.888 16.981 109.92 17.123 ;
     RECT  107.88 17.123 109.92 17.605 ;
     RECT  92.904 17.605 94.2 18.229 ;
     RECT  107.88 17.605 109.68 18.181 ;
     RECT  113.208 17.893 114.384 18.133 ;
     RECT  114.408 17.893 115.44 18.181 ;
     RECT  113.304 18.133 114.384 19.525 ;
     RECT  108.216 18.181 109.68 19.715 ;
     RECT  110.808 18.181 111.888 19.091 ;
     RECT  114.456 18.181 115.44 18.227 ;
     RECT  114.456 18.227 115.488 20.627 ;
     RECT  93.048 18.229 94.08 18.517 ;
     RECT  97.08 18.757 98.544 19.141 ;
     RECT  110.712 19.091 111.888 21.683 ;
     RECT  97.224 19.141 98.544 19.909 ;
     RECT  106.152 19.235 107.136 20.051 ;
     RECT  89.112 19.237 90.144 20.003 ;
     RECT  90.168 19.237 91.392 20.003 ;
     RECT  108.216 19.715 110.256 21.109 ;
     RECT  97.512 19.909 98.544 23.651 ;
     RECT  89.112 20.003 91.392 20.821 ;
     RECT  105.96 20.051 107.136 20.291 ;
     RECT  113.304 20.051 114.384 21.635 ;
     RECT  111.912 20.291 113.136 21.683 ;
     RECT  119.4 20.579 119.64 21.925 ;
     RECT  114.456 20.627 115.536 21.205 ;
     RECT  89.112 20.821 90.384 29.029 ;
     RECT  90.408 20.821 91.392 27.491 ;
     RECT  108.216 21.109 109.632 21.779 ;
     RECT  114.552 21.205 115.536 24.371 ;
     RECT  113.208 21.635 114.384 22.403 ;
     RECT  110.112 21.779 110.256 22.741 ;
     RECT  113.208 22.403 114.528 25.141 ;
     RECT  121.704 22.453 123.072 22.499 ;
     RECT  121.704 22.499 122.568 23.077 ;
     RECT  121.512 23.459 122.544 24.467 ;
     RECT  97.224 23.651 98.544 24.419 ;
     RECT  118.152 24.179 119.616 25.331 ;
     RECT  114.552 24.371 115.8 25.763 ;
     RECT  92.808 24.611 94.2 26.773 ;
     RECT  113.136 24.659 113.184 25.621 ;
     RECT  99.912 24.901 101.136 34.499 ;
     RECT  86.616 25.141 87.84 25.715 ;
     RECT  105.432 25.189 106.752 25.285 ;
     RECT  105.528 25.285 106.752 25.475 ;
     RECT  118.152 25.331 119.664 25.621 ;
     RECT  105.432 25.475 106.752 26.099 ;
     RECT  110.712 25.621 111.792 26.243 ;
     RECT  111.816 25.621 113.184 26.243 ;
     RECT  118.584 25.621 119.664 25.715 ;
     RECT  105.432 26.099 106.584 27.589 ;
     RECT  116.952 26.291 118.128 27.443 ;
     RECT  92.808 26.773 94.08 29.557 ;
     RECT  17.16 27.109 18.6 86.675 ;
     RECT  102.696 27.253 103.776 28.451 ;
     RECT  103.8 27.395 104.784 27.923 ;
     RECT  105.432 27.589 106.56 28.979 ;
     RECT  15.24 27.685 16.608 85.477 ;
     RECT  11.256 27.877 12.624 82.309 ;
     RECT  103.8 27.923 105 30.181 ;
     RECT  108.744 28.405 110.256 29.507 ;
     RECT  109.2 29.507 110.256 29.797 ;
     RECT  92.808 29.557 93.936 31.909 ;
     RECT  89.112 29.699 90.336 34.259 ;
     RECT  109.224 29.797 110.256 30.419 ;
     RECT  103.8 30.181 104.88 30.229 ;
     RECT  94.92 30.275 96.192 31.955 ;
     RECT  103.992 30.851 105 34.115 ;
     RECT  92.808 31.909 93.888 32.149 ;
     RECT  92.808 32.149 93.792 32.771 ;
     RECT  90.36 32.435 90.792 33.445 ;
     RECT  97.752 32.437 99.072 40.261 ;
     RECT  92.76 32.771 93.792 49.043 ;
     RECT  98.04 40.261 99.072 47.315 ;
     RECT  112.296 46.741 113.28 46.787 ;
     RECT  112.296 46.787 113.808 67.859 ;
     RECT  97.8 47.315 99.072 62.771 ;
     RECT  92.76 52.981 93.792 101.363 ;
     RECT  89.112 59.797 90.336 63.349 ;
     RECT  89.112 63.349 90.288 91.955 ;
     RECT  109.032 72.421 110.4 212.147 ;
     RECT  6.912 76.979 7.8 77.173 ;
     RECT  6.6 77.173 7.8 78.613 ;
     RECT  11.256 82.309 12.288 82.691 ;
     RECT  16.92 86.675 18.6 88.165 ;
     RECT  14.136 87.251 15.648 95.605 ;
     RECT  16.92 88.165 17.904 102.371 ;
     RECT  11.016 99.493 12.288 102.083 ;
     RECT  92.76 101.363 93.936 105.923 ;
     RECT  12.912 102.659 13.104 103.957 ;
     RECT  14.568 103.475 15.696 104.531 ;
     RECT  6.792 104.915 7.8 110.627 ;
     RECT  10.248 105.539 10.536 106.021 ;
     RECT  8.712 105.635 9.888 106.067 ;
     RECT  92.76 105.923 94.2 118.019 ;
     RECT  10.248 106.021 11.376 106.691 ;
     RECT  10.248 106.691 11.016 107.365 ;
     RECT  10.032 109.475 10.224 110.485 ;
     RECT  10.248 109.957 11.568 110.867 ;
     RECT  107.832 109.957 109.008 212.005 ;
     RECT  8.52 110.485 10.224 110.581 ;
     RECT  8.52 110.581 9.888 110.915 ;
     RECT  1.176 112.117 2.4 112.259 ;
  END
END ot_hbm_host_static_ingress
END LIBRARY
